VERSION 5.8 ;
BUSBITCHARS "[]" ;
DIVIDERCHAR "/" ;
UNITS
    DATABASE MICRONS 1000 ;
END UNITS

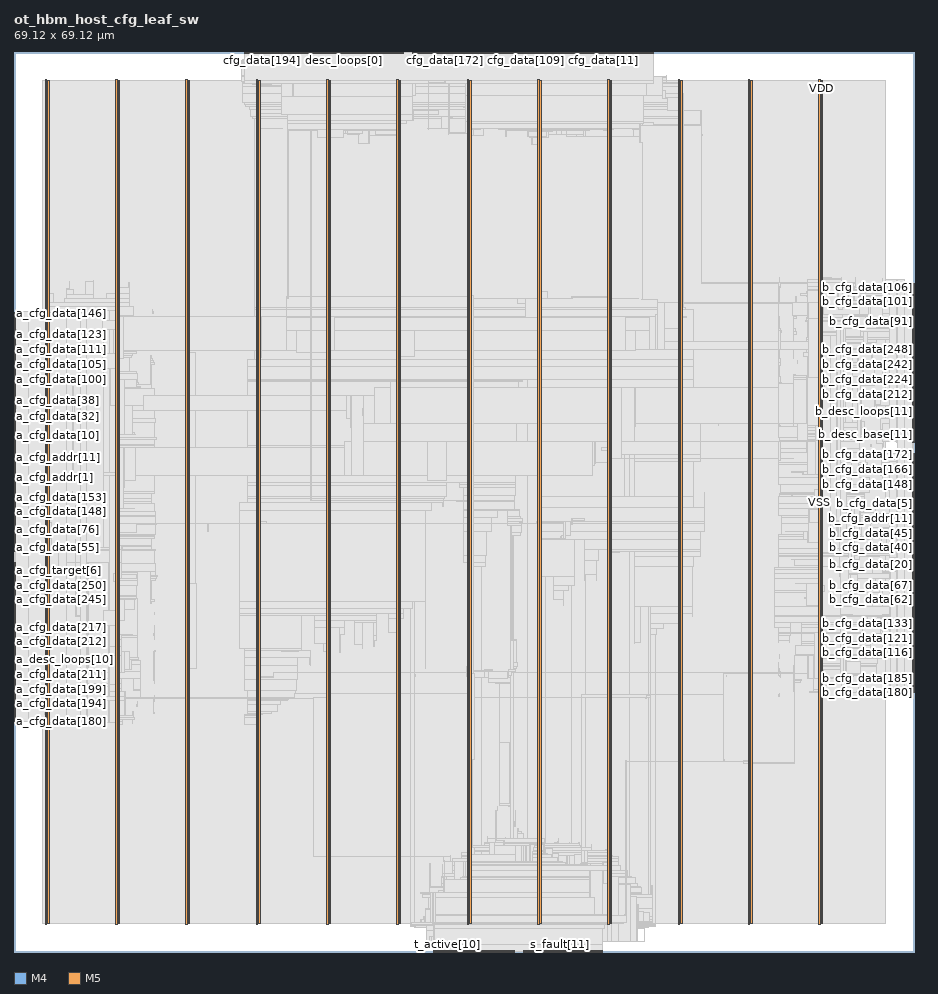
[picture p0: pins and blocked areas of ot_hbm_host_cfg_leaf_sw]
MACRO ot_hbm_host_cfg_leaf_sw
  FOREIGN ot_hbm_host_cfg_leaf_sw 0 0 ;
  CLASS BLOCK ;
  SIZE 69.12 BY 69.12 ;
  PIN a_cfg_addr[0]
    DIRECTION OUTPUT ;
    USE SIGNAL ;
    PORT
      LAYER M4 ;
        RECT  0 36.912 0.084 36.936 ;
    END
  END a_cfg_addr[0]
  PIN a_cfg_addr[10]
    DIRECTION OUTPUT ;
    USE SIGNAL ;
    PORT
      LAYER M4 ;
        RECT  0 37.872 0.084 37.896 ;
    END
  END a_cfg_addr[10]
  PIN a_cfg_addr[11]
    DIRECTION OUTPUT ;
    USE SIGNAL ;
    PORT
      LAYER M4 ;
        RECT  0 37.968 0.084 37.992 ;
    END
  END a_cfg_addr[11]
  PIN a_cfg_addr[1]
    DIRECTION OUTPUT ;
    USE SIGNAL ;
    PORT
      LAYER M4 ;
        RECT  0 37.008 0.084 37.032 ;
    END
  END a_cfg_addr[1]
  PIN a_cfg_addr[2]
    DIRECTION OUTPUT ;
    USE SIGNAL ;
    PORT
      LAYER M4 ;
        RECT  0 37.104 0.084 37.128 ;
    END
  END a_cfg_addr[2]
  PIN a_cfg_addr[3]
    DIRECTION OUTPUT ;
    USE SIGNAL ;
    PORT
      LAYER M4 ;
        RECT  0 37.2 0.084 37.224 ;
    END
  END a_cfg_addr[3]
  PIN a_cfg_addr[4]
    DIRECTION OUTPUT ;
    USE SIGNAL ;
    PORT
      LAYER M4 ;
        RECT  0 37.296 0.084 37.32 ;
    END
  END a_cfg_addr[4]
  PIN a_cfg_addr[5]
    DIRECTION OUTPUT ;
    USE SIGNAL ;
    PORT
      LAYER M4 ;
        RECT  0 37.392 0.084 37.416 ;
    END
  END a_cfg_addr[5]
  PIN a_cfg_addr[6]
    DIRECTION OUTPUT ;
    USE SIGNAL ;
    PORT
      LAYER M4 ;
        RECT  0 37.488 0.084 37.512 ;
    END
  END a_cfg_addr[6]
  PIN a_cfg_addr[7]
    DIRECTION OUTPUT ;
    USE SIGNAL ;
    PORT
      LAYER M4 ;
        RECT  0 37.584 0.084 37.608 ;
    END
  END a_cfg_addr[7]
  PIN a_cfg_addr[8]
    DIRECTION OUTPUT ;
    USE SIGNAL ;
    PORT
      LAYER M4 ;
        RECT  0 37.68 0.084 37.704 ;
    END
  END a_cfg_addr[8]
  PIN a_cfg_addr[9]
    DIRECTION OUTPUT ;
    USE SIGNAL ;
    PORT
      LAYER M4 ;
        RECT  0 37.776 0.084 37.8 ;
    END
  END a_cfg_addr[9]
  PIN a_cfg_data[0]
    DIRECTION OUTPUT ;
    USE SIGNAL ;
    PORT
      LAYER M4 ;
        RECT  0 38.064 0.084 38.088 ;
    END
  END a_cfg_data[0]
  PIN a_cfg_data[100]
    DIRECTION OUTPUT ;
    USE SIGNAL ;
    PORT
      LAYER M4 ;
        RECT  0 44.592 0.084 44.616 ;
    END
  END a_cfg_data[100]
  PIN a_cfg_data[101]
    DIRECTION OUTPUT ;
    USE SIGNAL ;
    PORT
      LAYER M4 ;
        RECT  0 44.688 0.084 44.712 ;
    END
  END a_cfg_data[101]
  PIN a_cfg_data[102]
    DIRECTION OUTPUT ;
    USE SIGNAL ;
    PORT
      LAYER M4 ;
        RECT  0 44.784 0.084 44.808 ;
    END
  END a_cfg_data[102]
  PIN a_cfg_data[103]
    DIRECTION OUTPUT ;
    USE SIGNAL ;
    PORT
      LAYER M4 ;
        RECT  0 44.88 0.084 44.904 ;
    END
  END a_cfg_data[103]
  PIN a_cfg_data[104]
    DIRECTION OUTPUT ;
    USE SIGNAL ;
    PORT
      LAYER M4 ;
        RECT  0 44.976 0.084 45 ;
    END
  END a_cfg_data[104]
  PIN a_cfg_data[105]
    DIRECTION OUTPUT ;
    USE SIGNAL ;
    PORT
      LAYER M4 ;
        RECT  0 45.072 0.084 45.096 ;
    END
  END a_cfg_data[105]
  PIN a_cfg_data[106]
    DIRECTION OUTPUT ;
    USE SIGNAL ;
    PORT
      LAYER M4 ;
        RECT  0 45.168 0.084 45.192 ;
    END
  END a_cfg_data[106]
  PIN a_cfg_data[107]
    DIRECTION OUTPUT ;
    USE SIGNAL ;
    PORT
      LAYER M4 ;
        RECT  0 45.264 0.084 45.288 ;
    END
  END a_cfg_data[107]
  PIN a_cfg_data[108]
    DIRECTION OUTPUT ;
    USE SIGNAL ;
    PORT
      LAYER M4 ;
        RECT  0 45.36 0.084 45.384 ;
    END
  END a_cfg_data[108]
  PIN a_cfg_data[109]
    DIRECTION OUTPUT ;
    USE SIGNAL ;
    PORT
      LAYER M4 ;
        RECT  0 45.456 0.084 45.48 ;
    END
  END a_cfg_data[109]
  PIN a_cfg_data[10]
    DIRECTION OUTPUT ;
    USE SIGNAL ;
    PORT
      LAYER M4 ;
        RECT  0 39.024 0.084 39.048 ;
    END
  END a_cfg_data[10]
  PIN a_cfg_data[110]
    DIRECTION OUTPUT ;
    USE SIGNAL ;
    PORT
      LAYER M4 ;
        RECT  0 45.552 0.084 45.576 ;
    END
  END a_cfg_data[110]
  PIN a_cfg_data[111]
    DIRECTION OUTPUT ;
    USE SIGNAL ;
    PORT
      LAYER M4 ;
        RECT  0 45.648 0.084 45.672 ;
    END
  END a_cfg_data[111]
  PIN a_cfg_data[112]
    DIRECTION OUTPUT ;
    USE SIGNAL ;
    PORT
      LAYER M4 ;
        RECT  0 45.744 0.084 45.768 ;
    END
  END a_cfg_data[112]
  PIN a_cfg_data[113]
    DIRECTION OUTPUT ;
    USE SIGNAL ;
    PORT
      LAYER M4 ;
        RECT  0 45.84 0.084 45.864 ;
    END
  END a_cfg_data[113]
  PIN a_cfg_data[114]
    DIRECTION OUTPUT ;
    USE SIGNAL ;
    PORT
      LAYER M4 ;
        RECT  0 45.936 0.084 45.96 ;
    END
  END a_cfg_data[114]
  PIN a_cfg_data[115]
    DIRECTION OUTPUT ;
    USE SIGNAL ;
    PORT
      LAYER M4 ;
        RECT  0 46.032 0.084 46.056 ;
    END
  END a_cfg_data[115]
  PIN a_cfg_data[116]
    DIRECTION OUTPUT ;
    USE SIGNAL ;
    PORT
      LAYER M4 ;
        RECT  0 46.128 0.084 46.152 ;
    END
  END a_cfg_data[116]
  PIN a_cfg_data[117]
    DIRECTION OUTPUT ;
    USE SIGNAL ;
    PORT
      LAYER M4 ;
        RECT  0 46.224 0.084 46.248 ;
    END
  END a_cfg_data[117]
  PIN a_cfg_data[118]
    DIRECTION OUTPUT ;
    USE SIGNAL ;
    PORT
      LAYER M4 ;
        RECT  0 46.32 0.084 46.344 ;
    END
  END a_cfg_data[118]
  PIN a_cfg_data[119]
    DIRECTION OUTPUT ;
    USE SIGNAL ;
    PORT
      LAYER M4 ;
        RECT  0 46.416 0.084 46.44 ;
    END
  END a_cfg_data[119]
  PIN a_cfg_data[11]
    DIRECTION OUTPUT ;
    USE SIGNAL ;
    PORT
      LAYER M4 ;
        RECT  0 39.12 0.084 39.144 ;
    END
  END a_cfg_data[11]
  PIN a_cfg_data[120]
    DIRECTION OUTPUT ;
    USE SIGNAL ;
    PORT
      LAYER M4 ;
        RECT  0 46.512 0.084 46.536 ;
    END
  END a_cfg_data[120]
  PIN a_cfg_data[121]
    DIRECTION OUTPUT ;
    USE SIGNAL ;
    PORT
      LAYER M4 ;
        RECT  0 46.608 0.084 46.632 ;
    END
  END a_cfg_data[121]
  PIN a_cfg_data[122]
    DIRECTION OUTPUT ;
    USE SIGNAL ;
    PORT
      LAYER M4 ;
        RECT  0 46.704 0.084 46.728 ;
    END
  END a_cfg_data[122]
  PIN a_cfg_data[123]
    DIRECTION OUTPUT ;
    USE SIGNAL ;
    PORT
      LAYER M4 ;
        RECT  0 46.8 0.084 46.824 ;
    END
  END a_cfg_data[123]
  PIN a_cfg_data[124]
    DIRECTION OUTPUT ;
    USE SIGNAL ;
    PORT
      LAYER M4 ;
        RECT  0 46.896 0.084 46.92 ;
    END
  END a_cfg_data[124]
  PIN a_cfg_data[125]
    DIRECTION OUTPUT ;
    USE SIGNAL ;
    PORT
      LAYER M4 ;
        RECT  0 46.992 0.084 47.016 ;
    END
  END a_cfg_data[125]
  PIN a_cfg_data[126]
    DIRECTION OUTPUT ;
    USE SIGNAL ;
    PORT
      LAYER M4 ;
        RECT  0 47.088 0.084 47.112 ;
    END
  END a_cfg_data[126]
  PIN a_cfg_data[127]
    DIRECTION OUTPUT ;
    USE SIGNAL ;
    PORT
      LAYER M4 ;
        RECT  0 47.184 0.084 47.208 ;
    END
  END a_cfg_data[127]
  PIN a_cfg_data[128]
    DIRECTION OUTPUT ;
    USE SIGNAL ;
    PORT
      LAYER M4 ;
        RECT  0 47.28 0.084 47.304 ;
    END
  END a_cfg_data[128]
  PIN a_cfg_data[129]
    DIRECTION OUTPUT ;
    USE SIGNAL ;
    PORT
      LAYER M4 ;
        RECT  0 47.376 0.084 47.4 ;
    END
  END a_cfg_data[129]
  PIN a_cfg_data[12]
    DIRECTION OUTPUT ;
    USE SIGNAL ;
    PORT
      LAYER M4 ;
        RECT  0 39.216 0.084 39.24 ;
    END
  END a_cfg_data[12]
  PIN a_cfg_data[130]
    DIRECTION OUTPUT ;
    USE SIGNAL ;
    PORT
      LAYER M4 ;
        RECT  0 47.472 0.084 47.496 ;
    END
  END a_cfg_data[130]
  PIN a_cfg_data[131]
    DIRECTION OUTPUT ;
    USE SIGNAL ;
    PORT
      LAYER M4 ;
        RECT  0 47.568 0.084 47.592 ;
    END
  END a_cfg_data[131]
  PIN a_cfg_data[132]
    DIRECTION OUTPUT ;
    USE SIGNAL ;
    PORT
      LAYER M4 ;
        RECT  0 47.664 0.084 47.688 ;
    END
  END a_cfg_data[132]
  PIN a_cfg_data[133]
    DIRECTION OUTPUT ;
    USE SIGNAL ;
    PORT
      LAYER M4 ;
        RECT  0 47.76 0.084 47.784 ;
    END
  END a_cfg_data[133]
  PIN a_cfg_data[134]
    DIRECTION OUTPUT ;
    USE SIGNAL ;
    PORT
      LAYER M4 ;
        RECT  0 47.856 0.084 47.88 ;
    END
  END a_cfg_data[134]
  PIN a_cfg_data[135]
    DIRECTION OUTPUT ;
    USE SIGNAL ;
    PORT
      LAYER M4 ;
        RECT  0 47.952 0.084 47.976 ;
    END
  END a_cfg_data[135]
  PIN a_cfg_data[136]
    DIRECTION OUTPUT ;
    USE SIGNAL ;
    PORT
      LAYER M4 ;
        RECT  0 48.048 0.084 48.072 ;
    END
  END a_cfg_data[136]
  PIN a_cfg_data[137]
    DIRECTION OUTPUT ;
    USE SIGNAL ;
    PORT
      LAYER M4 ;
        RECT  0 48.144 0.084 48.168 ;
    END
  END a_cfg_data[137]
  PIN a_cfg_data[138]
    DIRECTION OUTPUT ;
    USE SIGNAL ;
    PORT
      LAYER M4 ;
        RECT  0 48.24 0.084 48.264 ;
    END
  END a_cfg_data[138]
  PIN a_cfg_data[139]
    DIRECTION OUTPUT ;
    USE SIGNAL ;
    PORT
      LAYER M4 ;
        RECT  0 48.336 0.084 48.36 ;
    END
  END a_cfg_data[139]
  PIN a_cfg_data[13]
    DIRECTION OUTPUT ;
    USE SIGNAL ;
    PORT
      LAYER M4 ;
        RECT  0 39.312 0.084 39.336 ;
    END
  END a_cfg_data[13]
  PIN a_cfg_data[140]
    DIRECTION OUTPUT ;
    USE SIGNAL ;
    PORT
      LAYER M4 ;
        RECT  0 48.432 0.084 48.456 ;
    END
  END a_cfg_data[140]
  PIN a_cfg_data[141]
    DIRECTION OUTPUT ;
    USE SIGNAL ;
    PORT
      LAYER M4 ;
        RECT  0 48.528 0.084 48.552 ;
    END
  END a_cfg_data[141]
  PIN a_cfg_data[142]
    DIRECTION OUTPUT ;
    USE SIGNAL ;
    PORT
      LAYER M4 ;
        RECT  0 48.624 0.084 48.648 ;
    END
  END a_cfg_data[142]
  PIN a_cfg_data[143]
    DIRECTION OUTPUT ;
    USE SIGNAL ;
    PORT
      LAYER M4 ;
        RECT  0 48.72 0.084 48.744 ;
    END
  END a_cfg_data[143]
  PIN a_cfg_data[144]
    DIRECTION OUTPUT ;
    USE SIGNAL ;
    PORT
      LAYER M4 ;
        RECT  0 48.816 0.084 48.84 ;
    END
  END a_cfg_data[144]
  PIN a_cfg_data[145]
    DIRECTION OUTPUT ;
    USE SIGNAL ;
    PORT
      LAYER M4 ;
        RECT  0 48.912 0.084 48.936 ;
    END
  END a_cfg_data[145]
  PIN a_cfg_data[146]
    DIRECTION OUTPUT ;
    USE SIGNAL ;
    PORT
      LAYER M4 ;
        RECT  0 49.008 0.084 49.032 ;
    END
  END a_cfg_data[146]
  PIN a_cfg_data[147]
    DIRECTION OUTPUT ;
    USE SIGNAL ;
    PORT
      LAYER M4 ;
        RECT  0 49.104 0.084 49.128 ;
    END
  END a_cfg_data[147]
  PIN a_cfg_data[148]
    DIRECTION OUTPUT ;
    USE SIGNAL ;
    PORT
      LAYER M4 ;
        RECT  0 33.84 0.084 33.864 ;
    END
  END a_cfg_data[148]
  PIN a_cfg_data[149]
    DIRECTION OUTPUT ;
    USE SIGNAL ;
    PORT
      LAYER M4 ;
        RECT  0 33.936 0.084 33.96 ;
    END
  END a_cfg_data[149]
  PIN a_cfg_data[14]
    DIRECTION OUTPUT ;
    USE SIGNAL ;
    PORT
      LAYER M4 ;
        RECT  0 39.408 0.084 39.432 ;
    END
  END a_cfg_data[14]
  PIN a_cfg_data[150]
    DIRECTION OUTPUT ;
    USE SIGNAL ;
    PORT
      LAYER M4 ;
        RECT  0 34.032 0.084 34.056 ;
    END
  END a_cfg_data[150]
  PIN a_cfg_data[151]
    DIRECTION OUTPUT ;
    USE SIGNAL ;
    PORT
      LAYER M4 ;
        RECT  0 34.128 0.084 34.152 ;
    END
  END a_cfg_data[151]
  PIN a_cfg_data[152]
    DIRECTION OUTPUT ;
    USE SIGNAL ;
    PORT
      LAYER M4 ;
        RECT  0 34.224 0.084 34.248 ;
    END
  END a_cfg_data[152]
  PIN a_cfg_data[153]
    DIRECTION OUTPUT ;
    USE SIGNAL ;
    PORT
      LAYER M4 ;
        RECT  0 34.32 0.084 34.344 ;
    END
  END a_cfg_data[153]
  PIN a_cfg_data[154]
    DIRECTION OUTPUT ;
    USE SIGNAL ;
    PORT
      LAYER M4 ;
        RECT  0 34.416 0.084 34.44 ;
    END
  END a_cfg_data[154]
  PIN a_cfg_data[155]
    DIRECTION OUTPUT ;
    USE SIGNAL ;
    PORT
      LAYER M4 ;
        RECT  0 34.512 0.084 34.536 ;
    END
  END a_cfg_data[155]
  PIN a_cfg_data[156]
    DIRECTION OUTPUT ;
    USE SIGNAL ;
    PORT
      LAYER M4 ;
        RECT  0 34.608 0.084 34.632 ;
    END
  END a_cfg_data[156]
  PIN a_cfg_data[157]
    DIRECTION OUTPUT ;
    USE SIGNAL ;
    PORT
      LAYER M4 ;
        RECT  0 34.704 0.084 34.728 ;
    END
  END a_cfg_data[157]
  PIN a_cfg_data[158]
    DIRECTION OUTPUT ;
    USE SIGNAL ;
    PORT
      LAYER M4 ;
        RECT  0 34.8 0.084 34.824 ;
    END
  END a_cfg_data[158]
  PIN a_cfg_data[159]
    DIRECTION OUTPUT ;
    USE SIGNAL ;
    PORT
      LAYER M4 ;
        RECT  0 34.896 0.084 34.92 ;
    END
  END a_cfg_data[159]
  PIN a_cfg_data[15]
    DIRECTION OUTPUT ;
    USE SIGNAL ;
    PORT
      LAYER M4 ;
        RECT  0 39.504 0.084 39.528 ;
    END
  END a_cfg_data[15]
  PIN a_cfg_data[160]
    DIRECTION OUTPUT ;
    USE SIGNAL ;
    PORT
      LAYER M4 ;
        RECT  0 34.992 0.084 35.016 ;
    END
  END a_cfg_data[160]
  PIN a_cfg_data[161]
    DIRECTION OUTPUT ;
    USE SIGNAL ;
    PORT
      LAYER M4 ;
        RECT  0 35.088 0.084 35.112 ;
    END
  END a_cfg_data[161]
  PIN a_cfg_data[162]
    DIRECTION OUTPUT ;
    USE SIGNAL ;
    PORT
      LAYER M4 ;
        RECT  0 35.184 0.084 35.208 ;
    END
  END a_cfg_data[162]
  PIN a_cfg_data[163]
    DIRECTION OUTPUT ;
    USE SIGNAL ;
    PORT
      LAYER M4 ;
        RECT  0 35.28 0.084 35.304 ;
    END
  END a_cfg_data[163]
  PIN a_cfg_data[164]
    DIRECTION OUTPUT ;
    USE SIGNAL ;
    PORT
      LAYER M4 ;
        RECT  0 35.376 0.084 35.4 ;
    END
  END a_cfg_data[164]
  PIN a_cfg_data[165]
    DIRECTION OUTPUT ;
    USE SIGNAL ;
    PORT
      LAYER M4 ;
        RECT  0 35.472 0.084 35.496 ;
    END
  END a_cfg_data[165]
  PIN a_cfg_data[166]
    DIRECTION OUTPUT ;
    USE SIGNAL ;
    PORT
      LAYER M4 ;
        RECT  0 35.568 0.084 35.592 ;
    END
  END a_cfg_data[166]
  PIN a_cfg_data[167]
    DIRECTION OUTPUT ;
    USE SIGNAL ;
    PORT
      LAYER M4 ;
        RECT  0 35.664 0.084 35.688 ;
    END
  END a_cfg_data[167]
  PIN a_cfg_data[168]
    DIRECTION OUTPUT ;
    USE SIGNAL ;
    PORT
      LAYER M4 ;
        RECT  0 35.76 0.084 35.784 ;
    END
  END a_cfg_data[168]
  PIN a_cfg_data[169]
    DIRECTION OUTPUT ;
    USE SIGNAL ;
    PORT
      LAYER M4 ;
        RECT  0 35.856 0.084 35.88 ;
    END
  END a_cfg_data[169]
  PIN a_cfg_data[16]
    DIRECTION OUTPUT ;
    USE SIGNAL ;
    PORT
      LAYER M4 ;
        RECT  0 39.6 0.084 39.624 ;
    END
  END a_cfg_data[16]
  PIN a_cfg_data[170]
    DIRECTION OUTPUT ;
    USE SIGNAL ;
    PORT
      LAYER M4 ;
        RECT  0 35.952 0.084 35.976 ;
    END
  END a_cfg_data[170]
  PIN a_cfg_data[171]
    DIRECTION OUTPUT ;
    USE SIGNAL ;
    PORT
      LAYER M4 ;
        RECT  0 36.048 0.084 36.072 ;
    END
  END a_cfg_data[171]
  PIN a_cfg_data[172]
    DIRECTION OUTPUT ;
    USE SIGNAL ;
    PORT
      LAYER M4 ;
        RECT  0 36.144 0.084 36.168 ;
    END
  END a_cfg_data[172]
  PIN a_cfg_data[173]
    DIRECTION OUTPUT ;
    USE SIGNAL ;
    PORT
      LAYER M4 ;
        RECT  0 36.24 0.084 36.264 ;
    END
  END a_cfg_data[173]
  PIN a_cfg_data[174]
    DIRECTION OUTPUT ;
    USE SIGNAL ;
    PORT
      LAYER M4 ;
        RECT  0 36.336 0.084 36.36 ;
    END
  END a_cfg_data[174]
  PIN a_cfg_data[175]
    DIRECTION OUTPUT ;
    USE SIGNAL ;
    PORT
      LAYER M4 ;
        RECT  0 36.432 0.084 36.456 ;
    END
  END a_cfg_data[175]
  PIN a_cfg_data[176]
    DIRECTION OUTPUT ;
    USE SIGNAL ;
    PORT
      LAYER M4 ;
        RECT  0 36.528 0.084 36.552 ;
    END
  END a_cfg_data[176]
  PIN a_cfg_data[177]
    DIRECTION OUTPUT ;
    USE SIGNAL ;
    PORT
      LAYER M4 ;
        RECT  0 36.624 0.084 36.648 ;
    END
  END a_cfg_data[177]
  PIN a_cfg_data[178]
    DIRECTION OUTPUT ;
    USE SIGNAL ;
    PORT
      LAYER M4 ;
        RECT  0 36.72 0.084 36.744 ;
    END
  END a_cfg_data[178]
  PIN a_cfg_data[179]
    DIRECTION OUTPUT ;
    USE SIGNAL ;
    PORT
      LAYER M4 ;
        RECT  0 36.816 0.084 36.84 ;
    END
  END a_cfg_data[179]
  PIN a_cfg_data[17]
    DIRECTION OUTPUT ;
    USE SIGNAL ;
    PORT
      LAYER M4 ;
        RECT  0 39.696 0.084 39.72 ;
    END
  END a_cfg_data[17]
  PIN a_cfg_data[180]
    DIRECTION OUTPUT ;
    USE SIGNAL ;
    PORT
      LAYER M4 ;
        RECT  0 17.712 0.084 17.736 ;
    END
  END a_cfg_data[180]
  PIN a_cfg_data[181]
    DIRECTION OUTPUT ;
    USE SIGNAL ;
    PORT
      LAYER M4 ;
        RECT  0 17.808 0.084 17.832 ;
    END
  END a_cfg_data[181]
  PIN a_cfg_data[182]
    DIRECTION OUTPUT ;
    USE SIGNAL ;
    PORT
      LAYER M4 ;
        RECT  0 17.904 0.084 17.928 ;
    END
  END a_cfg_data[182]
  PIN a_cfg_data[183]
    DIRECTION OUTPUT ;
    USE SIGNAL ;
    PORT
      LAYER M4 ;
        RECT  0 18 0.084 18.024 ;
    END
  END a_cfg_data[183]
  PIN a_cfg_data[184]
    DIRECTION OUTPUT ;
    USE SIGNAL ;
    PORT
      LAYER M4 ;
        RECT  0 18.096 0.084 18.12 ;
    END
  END a_cfg_data[184]
  PIN a_cfg_data[185]
    DIRECTION OUTPUT ;
    USE SIGNAL ;
    PORT
      LAYER M4 ;
        RECT  0 18.192 0.084 18.216 ;
    END
  END a_cfg_data[185]
  PIN a_cfg_data[186]
    DIRECTION OUTPUT ;
    USE SIGNAL ;
    PORT
      LAYER M4 ;
        RECT  0 18.288 0.084 18.312 ;
    END
  END a_cfg_data[186]
  PIN a_cfg_data[187]
    DIRECTION OUTPUT ;
    USE SIGNAL ;
    PORT
      LAYER M4 ;
        RECT  0 18.384 0.084 18.408 ;
    END
  END a_cfg_data[187]
  PIN a_cfg_data[188]
    DIRECTION OUTPUT ;
    USE SIGNAL ;
    PORT
      LAYER M4 ;
        RECT  0 18.48 0.084 18.504 ;
    END
  END a_cfg_data[188]
  PIN a_cfg_data[189]
    DIRECTION OUTPUT ;
    USE SIGNAL ;
    PORT
      LAYER M4 ;
        RECT  0 18.576 0.084 18.6 ;
    END
  END a_cfg_data[189]
  PIN a_cfg_data[18]
    DIRECTION OUTPUT ;
    USE SIGNAL ;
    PORT
      LAYER M4 ;
        RECT  0 39.792 0.084 39.816 ;
    END
  END a_cfg_data[18]
  PIN a_cfg_data[190]
    DIRECTION OUTPUT ;
    USE SIGNAL ;
    PORT
      LAYER M4 ;
        RECT  0 18.672 0.084 18.696 ;
    END
  END a_cfg_data[190]
  PIN a_cfg_data[191]
    DIRECTION OUTPUT ;
    USE SIGNAL ;
    PORT
      LAYER M4 ;
        RECT  0 18.768 0.084 18.792 ;
    END
  END a_cfg_data[191]
  PIN a_cfg_data[192]
    DIRECTION OUTPUT ;
    USE SIGNAL ;
    PORT
      LAYER M4 ;
        RECT  0 18.864 0.084 18.888 ;
    END
  END a_cfg_data[192]
  PIN a_cfg_data[193]
    DIRECTION OUTPUT ;
    USE SIGNAL ;
    PORT
      LAYER M4 ;
        RECT  0 18.96 0.084 18.984 ;
    END
  END a_cfg_data[193]
  PIN a_cfg_data[194]
    DIRECTION OUTPUT ;
    USE SIGNAL ;
    PORT
      LAYER M4 ;
        RECT  0 19.056 0.084 19.08 ;
    END
  END a_cfg_data[194]
  PIN a_cfg_data[195]
    DIRECTION OUTPUT ;
    USE SIGNAL ;
    PORT
      LAYER M4 ;
        RECT  0 19.152 0.084 19.176 ;
    END
  END a_cfg_data[195]
  PIN a_cfg_data[196]
    DIRECTION OUTPUT ;
    USE SIGNAL ;
    PORT
      LAYER M4 ;
        RECT  0 19.248 0.084 19.272 ;
    END
  END a_cfg_data[196]
  PIN a_cfg_data[197]
    DIRECTION OUTPUT ;
    USE SIGNAL ;
    PORT
      LAYER M4 ;
        RECT  0 19.344 0.084 19.368 ;
    END
  END a_cfg_data[197]
  PIN a_cfg_data[198]
    DIRECTION OUTPUT ;
    USE SIGNAL ;
    PORT
      LAYER M4 ;
        RECT  0 19.44 0.084 19.464 ;
    END
  END a_cfg_data[198]
  PIN a_cfg_data[199]
    DIRECTION OUTPUT ;
    USE SIGNAL ;
    PORT
      LAYER M4 ;
        RECT  0 19.536 0.084 19.56 ;
    END
  END a_cfg_data[199]
  PIN a_cfg_data[19]
    DIRECTION OUTPUT ;
    USE SIGNAL ;
    PORT
      LAYER M4 ;
        RECT  0 39.888 0.084 39.912 ;
    END
  END a_cfg_data[19]
  PIN a_cfg_data[1]
    DIRECTION OUTPUT ;
    USE SIGNAL ;
    PORT
      LAYER M4 ;
        RECT  0 38.16 0.084 38.184 ;
    END
  END a_cfg_data[1]
  PIN a_cfg_data[200]
    DIRECTION OUTPUT ;
    USE SIGNAL ;
    PORT
      LAYER M4 ;
        RECT  0 19.632 0.084 19.656 ;
    END
  END a_cfg_data[200]
  PIN a_cfg_data[201]
    DIRECTION OUTPUT ;
    USE SIGNAL ;
    PORT
      LAYER M4 ;
        RECT  0 19.728 0.084 19.752 ;
    END
  END a_cfg_data[201]
  PIN a_cfg_data[202]
    DIRECTION OUTPUT ;
    USE SIGNAL ;
    PORT
      LAYER M4 ;
        RECT  0 19.824 0.084 19.848 ;
    END
  END a_cfg_data[202]
  PIN a_cfg_data[203]
    DIRECTION OUTPUT ;
    USE SIGNAL ;
    PORT
      LAYER M4 ;
        RECT  0 19.92 0.084 19.944 ;
    END
  END a_cfg_data[203]
  PIN a_cfg_data[204]
    DIRECTION OUTPUT ;
    USE SIGNAL ;
    PORT
      LAYER M4 ;
        RECT  0 20.016 0.084 20.04 ;
    END
  END a_cfg_data[204]
  PIN a_cfg_data[205]
    DIRECTION OUTPUT ;
    USE SIGNAL ;
    PORT
      LAYER M4 ;
        RECT  0 20.112 0.084 20.136 ;
    END
  END a_cfg_data[205]
  PIN a_cfg_data[206]
    DIRECTION OUTPUT ;
    USE SIGNAL ;
    PORT
      LAYER M4 ;
        RECT  0 20.208 0.084 20.232 ;
    END
  END a_cfg_data[206]
  PIN a_cfg_data[207]
    DIRECTION OUTPUT ;
    USE SIGNAL ;
    PORT
      LAYER M4 ;
        RECT  0 20.304 0.084 20.328 ;
    END
  END a_cfg_data[207]
  PIN a_cfg_data[208]
    DIRECTION OUTPUT ;
    USE SIGNAL ;
    PORT
      LAYER M4 ;
        RECT  0 20.4 0.084 20.424 ;
    END
  END a_cfg_data[208]
  PIN a_cfg_data[209]
    DIRECTION OUTPUT ;
    USE SIGNAL ;
    PORT
      LAYER M4 ;
        RECT  0 20.496 0.084 20.52 ;
    END
  END a_cfg_data[209]
  PIN a_cfg_data[20]
    DIRECTION OUTPUT ;
    USE SIGNAL ;
    PORT
      LAYER M4 ;
        RECT  0 39.984 0.084 40.008 ;
    END
  END a_cfg_data[20]
  PIN a_cfg_data[210]
    DIRECTION OUTPUT ;
    USE SIGNAL ;
    PORT
      LAYER M4 ;
        RECT  0 20.592 0.084 20.616 ;
    END
  END a_cfg_data[210]
  PIN a_cfg_data[211]
    DIRECTION OUTPUT ;
    USE SIGNAL ;
    PORT
      LAYER M4 ;
        RECT  0 20.688 0.084 20.712 ;
    END
  END a_cfg_data[211]
  PIN a_cfg_data[212]
    DIRECTION OUTPUT ;
    USE SIGNAL ;
    PORT
      LAYER M4 ;
        RECT  0 23.856 0.084 23.88 ;
    END
  END a_cfg_data[212]
  PIN a_cfg_data[213]
    DIRECTION OUTPUT ;
    USE SIGNAL ;
    PORT
      LAYER M4 ;
        RECT  0 23.952 0.084 23.976 ;
    END
  END a_cfg_data[213]
  PIN a_cfg_data[214]
    DIRECTION OUTPUT ;
    USE SIGNAL ;
    PORT
      LAYER M4 ;
        RECT  0 24.048 0.084 24.072 ;
    END
  END a_cfg_data[214]
  PIN a_cfg_data[215]
    DIRECTION OUTPUT ;
    USE SIGNAL ;
    PORT
      LAYER M4 ;
        RECT  0 24.144 0.084 24.168 ;
    END
  END a_cfg_data[215]
  PIN a_cfg_data[216]
    DIRECTION OUTPUT ;
    USE SIGNAL ;
    PORT
      LAYER M4 ;
        RECT  0 24.24 0.084 24.264 ;
    END
  END a_cfg_data[216]
  PIN a_cfg_data[217]
    DIRECTION OUTPUT ;
    USE SIGNAL ;
    PORT
      LAYER M4 ;
        RECT  0 24.336 0.084 24.36 ;
    END
  END a_cfg_data[217]
  PIN a_cfg_data[218]
    DIRECTION OUTPUT ;
    USE SIGNAL ;
    PORT
      LAYER M4 ;
        RECT  0 24.432 0.084 24.456 ;
    END
  END a_cfg_data[218]
  PIN a_cfg_data[219]
    DIRECTION OUTPUT ;
    USE SIGNAL ;
    PORT
      LAYER M4 ;
        RECT  0 24.528 0.084 24.552 ;
    END
  END a_cfg_data[219]
  PIN a_cfg_data[21]
    DIRECTION OUTPUT ;
    USE SIGNAL ;
    PORT
      LAYER M4 ;
        RECT  0 40.08 0.084 40.104 ;
    END
  END a_cfg_data[21]
  PIN a_cfg_data[220]
    DIRECTION OUTPUT ;
    USE SIGNAL ;
    PORT
      LAYER M4 ;
        RECT  0 24.624 0.084 24.648 ;
    END
  END a_cfg_data[220]
  PIN a_cfg_data[221]
    DIRECTION OUTPUT ;
    USE SIGNAL ;
    PORT
      LAYER M4 ;
        RECT  0 24.72 0.084 24.744 ;
    END
  END a_cfg_data[221]
  PIN a_cfg_data[222]
    DIRECTION OUTPUT ;
    USE SIGNAL ;
    PORT
      LAYER M4 ;
        RECT  0 24.816 0.084 24.84 ;
    END
  END a_cfg_data[222]
  PIN a_cfg_data[223]
    DIRECTION OUTPUT ;
    USE SIGNAL ;
    PORT
      LAYER M4 ;
        RECT  0 24.912 0.084 24.936 ;
    END
  END a_cfg_data[223]
  PIN a_cfg_data[224]
    DIRECTION OUTPUT ;
    USE SIGNAL ;
    PORT
      LAYER M4 ;
        RECT  0 25.008 0.084 25.032 ;
    END
  END a_cfg_data[224]
  PIN a_cfg_data[225]
    DIRECTION OUTPUT ;
    USE SIGNAL ;
    PORT
      LAYER M4 ;
        RECT  0 25.104 0.084 25.128 ;
    END
  END a_cfg_data[225]
  PIN a_cfg_data[226]
    DIRECTION OUTPUT ;
    USE SIGNAL ;
    PORT
      LAYER M4 ;
        RECT  0 25.2 0.084 25.224 ;
    END
  END a_cfg_data[226]
  PIN a_cfg_data[227]
    DIRECTION OUTPUT ;
    USE SIGNAL ;
    PORT
      LAYER M4 ;
        RECT  0 25.296 0.084 25.32 ;
    END
  END a_cfg_data[227]
  PIN a_cfg_data[228]
    DIRECTION OUTPUT ;
    USE SIGNAL ;
    PORT
      LAYER M4 ;
        RECT  0 25.392 0.084 25.416 ;
    END
  END a_cfg_data[228]
  PIN a_cfg_data[229]
    DIRECTION OUTPUT ;
    USE SIGNAL ;
    PORT
      LAYER M4 ;
        RECT  0 25.488 0.084 25.512 ;
    END
  END a_cfg_data[229]
  PIN a_cfg_data[22]
    DIRECTION OUTPUT ;
    USE SIGNAL ;
    PORT
      LAYER M4 ;
        RECT  0 40.176 0.084 40.2 ;
    END
  END a_cfg_data[22]
  PIN a_cfg_data[230]
    DIRECTION OUTPUT ;
    USE SIGNAL ;
    PORT
      LAYER M4 ;
        RECT  0 25.584 0.084 25.608 ;
    END
  END a_cfg_data[230]
  PIN a_cfg_data[231]
    DIRECTION OUTPUT ;
    USE SIGNAL ;
    PORT
      LAYER M4 ;
        RECT  0 25.68 0.084 25.704 ;
    END
  END a_cfg_data[231]
  PIN a_cfg_data[232]
    DIRECTION OUTPUT ;
    USE SIGNAL ;
    PORT
      LAYER M4 ;
        RECT  0 25.776 0.084 25.8 ;
    END
  END a_cfg_data[232]
  PIN a_cfg_data[233]
    DIRECTION OUTPUT ;
    USE SIGNAL ;
    PORT
      LAYER M4 ;
        RECT  0 25.872 0.084 25.896 ;
    END
  END a_cfg_data[233]
  PIN a_cfg_data[234]
    DIRECTION OUTPUT ;
    USE SIGNAL ;
    PORT
      LAYER M4 ;
        RECT  0 25.968 0.084 25.992 ;
    END
  END a_cfg_data[234]
  PIN a_cfg_data[235]
    DIRECTION OUTPUT ;
    USE SIGNAL ;
    PORT
      LAYER M4 ;
        RECT  0 26.064 0.084 26.088 ;
    END
  END a_cfg_data[235]
  PIN a_cfg_data[236]
    DIRECTION OUTPUT ;
    USE SIGNAL ;
    PORT
      LAYER M4 ;
        RECT  0 26.16 0.084 26.184 ;
    END
  END a_cfg_data[236]
  PIN a_cfg_data[237]
    DIRECTION OUTPUT ;
    USE SIGNAL ;
    PORT
      LAYER M4 ;
        RECT  0 26.256 0.084 26.28 ;
    END
  END a_cfg_data[237]
  PIN a_cfg_data[238]
    DIRECTION OUTPUT ;
    USE SIGNAL ;
    PORT
      LAYER M4 ;
        RECT  0 26.352 0.084 26.376 ;
    END
  END a_cfg_data[238]
  PIN a_cfg_data[239]
    DIRECTION OUTPUT ;
    USE SIGNAL ;
    PORT
      LAYER M4 ;
        RECT  0 26.448 0.084 26.472 ;
    END
  END a_cfg_data[239]
  PIN a_cfg_data[23]
    DIRECTION OUTPUT ;
    USE SIGNAL ;
    PORT
      LAYER M4 ;
        RECT  0 40.272 0.084 40.296 ;
    END
  END a_cfg_data[23]
  PIN a_cfg_data[240]
    DIRECTION OUTPUT ;
    USE SIGNAL ;
    PORT
      LAYER M4 ;
        RECT  0 26.544 0.084 26.568 ;
    END
  END a_cfg_data[240]
  PIN a_cfg_data[241]
    DIRECTION OUTPUT ;
    USE SIGNAL ;
    PORT
      LAYER M4 ;
        RECT  0 26.64 0.084 26.664 ;
    END
  END a_cfg_data[241]
  PIN a_cfg_data[242]
    DIRECTION OUTPUT ;
    USE SIGNAL ;
    PORT
      LAYER M4 ;
        RECT  0 26.736 0.084 26.76 ;
    END
  END a_cfg_data[242]
  PIN a_cfg_data[243]
    DIRECTION OUTPUT ;
    USE SIGNAL ;
    PORT
      LAYER M4 ;
        RECT  0 26.832 0.084 26.856 ;
    END
  END a_cfg_data[243]
  PIN a_cfg_data[244]
    DIRECTION OUTPUT ;
    USE SIGNAL ;
    PORT
      LAYER M4 ;
        RECT  0 26.928 0.084 26.952 ;
    END
  END a_cfg_data[244]
  PIN a_cfg_data[245]
    DIRECTION OUTPUT ;
    USE SIGNAL ;
    PORT
      LAYER M4 ;
        RECT  0 27.024 0.084 27.048 ;
    END
  END a_cfg_data[245]
  PIN a_cfg_data[246]
    DIRECTION OUTPUT ;
    USE SIGNAL ;
    PORT
      LAYER M4 ;
        RECT  0 27.12 0.084 27.144 ;
    END
  END a_cfg_data[246]
  PIN a_cfg_data[247]
    DIRECTION OUTPUT ;
    USE SIGNAL ;
    PORT
      LAYER M4 ;
        RECT  0 27.216 0.084 27.24 ;
    END
  END a_cfg_data[247]
  PIN a_cfg_data[248]
    DIRECTION OUTPUT ;
    USE SIGNAL ;
    PORT
      LAYER M4 ;
        RECT  0 27.312 0.084 27.336 ;
    END
  END a_cfg_data[248]
  PIN a_cfg_data[249]
    DIRECTION OUTPUT ;
    USE SIGNAL ;
    PORT
      LAYER M4 ;
        RECT  0 27.408 0.084 27.432 ;
    END
  END a_cfg_data[249]
  PIN a_cfg_data[24]
    DIRECTION OUTPUT ;
    USE SIGNAL ;
    PORT
      LAYER M4 ;
        RECT  0 40.368 0.084 40.392 ;
    END
  END a_cfg_data[24]
  PIN a_cfg_data[250]
    DIRECTION OUTPUT ;
    USE SIGNAL ;
    PORT
      LAYER M4 ;
        RECT  0 27.504 0.084 27.528 ;
    END
  END a_cfg_data[250]
  PIN a_cfg_data[251]
    DIRECTION OUTPUT ;
    USE SIGNAL ;
    PORT
      LAYER M4 ;
        RECT  0 27.6 0.084 27.624 ;
    END
  END a_cfg_data[251]
  PIN a_cfg_data[252]
    DIRECTION OUTPUT ;
    USE SIGNAL ;
    PORT
      LAYER M4 ;
        RECT  0 27.696 0.084 27.72 ;
    END
  END a_cfg_data[252]
  PIN a_cfg_data[253]
    DIRECTION OUTPUT ;
    USE SIGNAL ;
    PORT
      LAYER M4 ;
        RECT  0 27.792 0.084 27.816 ;
    END
  END a_cfg_data[253]
  PIN a_cfg_data[254]
    DIRECTION OUTPUT ;
    USE SIGNAL ;
    PORT
      LAYER M4 ;
        RECT  0 27.888 0.084 27.912 ;
    END
  END a_cfg_data[254]
  PIN a_cfg_data[255]
    DIRECTION OUTPUT ;
    USE SIGNAL ;
    PORT
      LAYER M4 ;
        RECT  0 27.984 0.084 28.008 ;
    END
  END a_cfg_data[255]
  PIN a_cfg_data[25]
    DIRECTION OUTPUT ;
    USE SIGNAL ;
    PORT
      LAYER M4 ;
        RECT  0 40.464 0.084 40.488 ;
    END
  END a_cfg_data[25]
  PIN a_cfg_data[26]
    DIRECTION OUTPUT ;
    USE SIGNAL ;
    PORT
      LAYER M4 ;
        RECT  0 40.56 0.084 40.584 ;
    END
  END a_cfg_data[26]
  PIN a_cfg_data[27]
    DIRECTION OUTPUT ;
    USE SIGNAL ;
    PORT
      LAYER M4 ;
        RECT  0 40.656 0.084 40.68 ;
    END
  END a_cfg_data[27]
  PIN a_cfg_data[28]
    DIRECTION OUTPUT ;
    USE SIGNAL ;
    PORT
      LAYER M4 ;
        RECT  0 40.752 0.084 40.776 ;
    END
  END a_cfg_data[28]
  PIN a_cfg_data[29]
    DIRECTION OUTPUT ;
    USE SIGNAL ;
    PORT
      LAYER M4 ;
        RECT  0 40.848 0.084 40.872 ;
    END
  END a_cfg_data[29]
  PIN a_cfg_data[2]
    DIRECTION OUTPUT ;
    USE SIGNAL ;
    PORT
      LAYER M4 ;
        RECT  0 38.256 0.084 38.28 ;
    END
  END a_cfg_data[2]
  PIN a_cfg_data[30]
    DIRECTION OUTPUT ;
    USE SIGNAL ;
    PORT
      LAYER M4 ;
        RECT  0 40.944 0.084 40.968 ;
    END
  END a_cfg_data[30]
  PIN a_cfg_data[31]
    DIRECTION OUTPUT ;
    USE SIGNAL ;
    PORT
      LAYER M4 ;
        RECT  0 41.04 0.084 41.064 ;
    END
  END a_cfg_data[31]
  PIN a_cfg_data[32]
    DIRECTION OUTPUT ;
    USE SIGNAL ;
    PORT
      LAYER M4 ;
        RECT  0 41.136 0.084 41.16 ;
    END
  END a_cfg_data[32]
  PIN a_cfg_data[33]
    DIRECTION OUTPUT ;
    USE SIGNAL ;
    PORT
      LAYER M4 ;
        RECT  0 41.232 0.084 41.256 ;
    END
  END a_cfg_data[33]
  PIN a_cfg_data[34]
    DIRECTION OUTPUT ;
    USE SIGNAL ;
    PORT
      LAYER M4 ;
        RECT  0 41.328 0.084 41.352 ;
    END
  END a_cfg_data[34]
  PIN a_cfg_data[35]
    DIRECTION OUTPUT ;
    USE SIGNAL ;
    PORT
      LAYER M4 ;
        RECT  0 41.424 0.084 41.448 ;
    END
  END a_cfg_data[35]
  PIN a_cfg_data[36]
    DIRECTION OUTPUT ;
    USE SIGNAL ;
    PORT
      LAYER M4 ;
        RECT  0 41.52 0.084 41.544 ;
    END
  END a_cfg_data[36]
  PIN a_cfg_data[37]
    DIRECTION OUTPUT ;
    USE SIGNAL ;
    PORT
      LAYER M4 ;
        RECT  0 41.616 0.084 41.64 ;
    END
  END a_cfg_data[37]
  PIN a_cfg_data[38]
    DIRECTION OUTPUT ;
    USE SIGNAL ;
    PORT
      LAYER M4 ;
        RECT  0 41.712 0.084 41.736 ;
    END
  END a_cfg_data[38]
  PIN a_cfg_data[39]
    DIRECTION OUTPUT ;
    USE SIGNAL ;
    PORT
      LAYER M4 ;
        RECT  0 41.808 0.084 41.832 ;
    END
  END a_cfg_data[39]
  PIN a_cfg_data[3]
    DIRECTION OUTPUT ;
    USE SIGNAL ;
    PORT
      LAYER M4 ;
        RECT  0 38.352 0.084 38.376 ;
    END
  END a_cfg_data[3]
  PIN a_cfg_data[40]
    DIRECTION OUTPUT ;
    USE SIGNAL ;
    PORT
      LAYER M4 ;
        RECT  0 41.904 0.084 41.928 ;
    END
  END a_cfg_data[40]
  PIN a_cfg_data[41]
    DIRECTION OUTPUT ;
    USE SIGNAL ;
    PORT
      LAYER M4 ;
        RECT  0 42 0.084 42.024 ;
    END
  END a_cfg_data[41]
  PIN a_cfg_data[42]
    DIRECTION OUTPUT ;
    USE SIGNAL ;
    PORT
      LAYER M4 ;
        RECT  0 42.096 0.084 42.12 ;
    END
  END a_cfg_data[42]
  PIN a_cfg_data[43]
    DIRECTION OUTPUT ;
    USE SIGNAL ;
    PORT
      LAYER M4 ;
        RECT  0 42.192 0.084 42.216 ;
    END
  END a_cfg_data[43]
  PIN a_cfg_data[44]
    DIRECTION OUTPUT ;
    USE SIGNAL ;
    PORT
      LAYER M4 ;
        RECT  0 42.288 0.084 42.312 ;
    END
  END a_cfg_data[44]
  PIN a_cfg_data[45]
    DIRECTION OUTPUT ;
    USE SIGNAL ;
    PORT
      LAYER M4 ;
        RECT  0 42.384 0.084 42.408 ;
    END
  END a_cfg_data[45]
  PIN a_cfg_data[46]
    DIRECTION OUTPUT ;
    USE SIGNAL ;
    PORT
      LAYER M4 ;
        RECT  0 42.48 0.084 42.504 ;
    END
  END a_cfg_data[46]
  PIN a_cfg_data[47]
    DIRECTION OUTPUT ;
    USE SIGNAL ;
    PORT
      LAYER M4 ;
        RECT  0 42.576 0.084 42.6 ;
    END
  END a_cfg_data[47]
  PIN a_cfg_data[48]
    DIRECTION OUTPUT ;
    USE SIGNAL ;
    PORT
      LAYER M4 ;
        RECT  0 42.672 0.084 42.696 ;
    END
  END a_cfg_data[48]
  PIN a_cfg_data[49]
    DIRECTION OUTPUT ;
    USE SIGNAL ;
    PORT
      LAYER M4 ;
        RECT  0 42.768 0.084 42.792 ;
    END
  END a_cfg_data[49]
  PIN a_cfg_data[4]
    DIRECTION OUTPUT ;
    USE SIGNAL ;
    PORT
      LAYER M4 ;
        RECT  0 38.448 0.084 38.472 ;
    END
  END a_cfg_data[4]
  PIN a_cfg_data[50]
    DIRECTION OUTPUT ;
    USE SIGNAL ;
    PORT
      LAYER M4 ;
        RECT  0 42.864 0.084 42.888 ;
    END
  END a_cfg_data[50]
  PIN a_cfg_data[51]
    DIRECTION OUTPUT ;
    USE SIGNAL ;
    PORT
      LAYER M4 ;
        RECT  0 42.96 0.084 42.984 ;
    END
  END a_cfg_data[51]
  PIN a_cfg_data[52]
    DIRECTION OUTPUT ;
    USE SIGNAL ;
    PORT
      LAYER M4 ;
        RECT  0 30.768 0.084 30.792 ;
    END
  END a_cfg_data[52]
  PIN a_cfg_data[53]
    DIRECTION OUTPUT ;
    USE SIGNAL ;
    PORT
      LAYER M4 ;
        RECT  0 30.864 0.084 30.888 ;
    END
  END a_cfg_data[53]
  PIN a_cfg_data[54]
    DIRECTION OUTPUT ;
    USE SIGNAL ;
    PORT
      LAYER M4 ;
        RECT  0 30.96 0.084 30.984 ;
    END
  END a_cfg_data[54]
  PIN a_cfg_data[55]
    DIRECTION OUTPUT ;
    USE SIGNAL ;
    PORT
      LAYER M4 ;
        RECT  0 31.056 0.084 31.08 ;
    END
  END a_cfg_data[55]
  PIN a_cfg_data[56]
    DIRECTION OUTPUT ;
    USE SIGNAL ;
    PORT
      LAYER M4 ;
        RECT  0 31.152 0.084 31.176 ;
    END
  END a_cfg_data[56]
  PIN a_cfg_data[57]
    DIRECTION OUTPUT ;
    USE SIGNAL ;
    PORT
      LAYER M4 ;
        RECT  0 31.248 0.084 31.272 ;
    END
  END a_cfg_data[57]
  PIN a_cfg_data[58]
    DIRECTION OUTPUT ;
    USE SIGNAL ;
    PORT
      LAYER M4 ;
        RECT  0 31.344 0.084 31.368 ;
    END
  END a_cfg_data[58]
  PIN a_cfg_data[59]
    DIRECTION OUTPUT ;
    USE SIGNAL ;
    PORT
      LAYER M4 ;
        RECT  0 31.44 0.084 31.464 ;
    END
  END a_cfg_data[59]
  PIN a_cfg_data[5]
    DIRECTION OUTPUT ;
    USE SIGNAL ;
    PORT
      LAYER M4 ;
        RECT  0 38.544 0.084 38.568 ;
    END
  END a_cfg_data[5]
  PIN a_cfg_data[60]
    DIRECTION OUTPUT ;
    USE SIGNAL ;
    PORT
      LAYER M4 ;
        RECT  0 31.536 0.084 31.56 ;
    END
  END a_cfg_data[60]
  PIN a_cfg_data[61]
    DIRECTION OUTPUT ;
    USE SIGNAL ;
    PORT
      LAYER M4 ;
        RECT  0 31.632 0.084 31.656 ;
    END
  END a_cfg_data[61]
  PIN a_cfg_data[62]
    DIRECTION OUTPUT ;
    USE SIGNAL ;
    PORT
      LAYER M4 ;
        RECT  0 31.728 0.084 31.752 ;
    END
  END a_cfg_data[62]
  PIN a_cfg_data[63]
    DIRECTION OUTPUT ;
    USE SIGNAL ;
    PORT
      LAYER M4 ;
        RECT  0 31.824 0.084 31.848 ;
    END
  END a_cfg_data[63]
  PIN a_cfg_data[64]
    DIRECTION OUTPUT ;
    USE SIGNAL ;
    PORT
      LAYER M4 ;
        RECT  0 31.92 0.084 31.944 ;
    END
  END a_cfg_data[64]
  PIN a_cfg_data[65]
    DIRECTION OUTPUT ;
    USE SIGNAL ;
    PORT
      LAYER M4 ;
        RECT  0 32.016 0.084 32.04 ;
    END
  END a_cfg_data[65]
  PIN a_cfg_data[66]
    DIRECTION OUTPUT ;
    USE SIGNAL ;
    PORT
      LAYER M4 ;
        RECT  0 32.112 0.084 32.136 ;
    END
  END a_cfg_data[66]
  PIN a_cfg_data[67]
    DIRECTION OUTPUT ;
    USE SIGNAL ;
    PORT
      LAYER M4 ;
        RECT  0 32.208 0.084 32.232 ;
    END
  END a_cfg_data[67]
  PIN a_cfg_data[68]
    DIRECTION OUTPUT ;
    USE SIGNAL ;
    PORT
      LAYER M4 ;
        RECT  0 32.304 0.084 32.328 ;
    END
  END a_cfg_data[68]
  PIN a_cfg_data[69]
    DIRECTION OUTPUT ;
    USE SIGNAL ;
    PORT
      LAYER M4 ;
        RECT  0 32.4 0.084 32.424 ;
    END
  END a_cfg_data[69]
  PIN a_cfg_data[6]
    DIRECTION OUTPUT ;
    USE SIGNAL ;
    PORT
      LAYER M4 ;
        RECT  0 38.64 0.084 38.664 ;
    END
  END a_cfg_data[6]
  PIN a_cfg_data[70]
    DIRECTION OUTPUT ;
    USE SIGNAL ;
    PORT
      LAYER M4 ;
        RECT  0 32.496 0.084 32.52 ;
    END
  END a_cfg_data[70]
  PIN a_cfg_data[71]
    DIRECTION OUTPUT ;
    USE SIGNAL ;
    PORT
      LAYER M4 ;
        RECT  0 32.592 0.084 32.616 ;
    END
  END a_cfg_data[71]
  PIN a_cfg_data[72]
    DIRECTION OUTPUT ;
    USE SIGNAL ;
    PORT
      LAYER M4 ;
        RECT  0 32.688 0.084 32.712 ;
    END
  END a_cfg_data[72]
  PIN a_cfg_data[73]
    DIRECTION OUTPUT ;
    USE SIGNAL ;
    PORT
      LAYER M4 ;
        RECT  0 32.784 0.084 32.808 ;
    END
  END a_cfg_data[73]
  PIN a_cfg_data[74]
    DIRECTION OUTPUT ;
    USE SIGNAL ;
    PORT
      LAYER M4 ;
        RECT  0 32.88 0.084 32.904 ;
    END
  END a_cfg_data[74]
  PIN a_cfg_data[75]
    DIRECTION OUTPUT ;
    USE SIGNAL ;
    PORT
      LAYER M4 ;
        RECT  0 32.976 0.084 33 ;
    END
  END a_cfg_data[75]
  PIN a_cfg_data[76]
    DIRECTION OUTPUT ;
    USE SIGNAL ;
    PORT
      LAYER M4 ;
        RECT  0 33.072 0.084 33.096 ;
    END
  END a_cfg_data[76]
  PIN a_cfg_data[77]
    DIRECTION OUTPUT ;
    USE SIGNAL ;
    PORT
      LAYER M4 ;
        RECT  0 33.168 0.084 33.192 ;
    END
  END a_cfg_data[77]
  PIN a_cfg_data[78]
    DIRECTION OUTPUT ;
    USE SIGNAL ;
    PORT
      LAYER M4 ;
        RECT  0 33.264 0.084 33.288 ;
    END
  END a_cfg_data[78]
  PIN a_cfg_data[79]
    DIRECTION OUTPUT ;
    USE SIGNAL ;
    PORT
      LAYER M4 ;
        RECT  0 33.36 0.084 33.384 ;
    END
  END a_cfg_data[79]
  PIN a_cfg_data[7]
    DIRECTION OUTPUT ;
    USE SIGNAL ;
    PORT
      LAYER M4 ;
        RECT  0 38.736 0.084 38.76 ;
    END
  END a_cfg_data[7]
  PIN a_cfg_data[80]
    DIRECTION OUTPUT ;
    USE SIGNAL ;
    PORT
      LAYER M4 ;
        RECT  0 33.456 0.084 33.48 ;
    END
  END a_cfg_data[80]
  PIN a_cfg_data[81]
    DIRECTION OUTPUT ;
    USE SIGNAL ;
    PORT
      LAYER M4 ;
        RECT  0 33.552 0.084 33.576 ;
    END
  END a_cfg_data[81]
  PIN a_cfg_data[82]
    DIRECTION OUTPUT ;
    USE SIGNAL ;
    PORT
      LAYER M4 ;
        RECT  0 33.648 0.084 33.672 ;
    END
  END a_cfg_data[82]
  PIN a_cfg_data[83]
    DIRECTION OUTPUT ;
    USE SIGNAL ;
    PORT
      LAYER M4 ;
        RECT  0 33.744 0.084 33.768 ;
    END
  END a_cfg_data[83]
  PIN a_cfg_data[84]
    DIRECTION OUTPUT ;
    USE SIGNAL ;
    PORT
      LAYER M4 ;
        RECT  0 43.056 0.084 43.08 ;
    END
  END a_cfg_data[84]
  PIN a_cfg_data[85]
    DIRECTION OUTPUT ;
    USE SIGNAL ;
    PORT
      LAYER M4 ;
        RECT  0 43.152 0.084 43.176 ;
    END
  END a_cfg_data[85]
  PIN a_cfg_data[86]
    DIRECTION OUTPUT ;
    USE SIGNAL ;
    PORT
      LAYER M4 ;
        RECT  0 43.248 0.084 43.272 ;
    END
  END a_cfg_data[86]
  PIN a_cfg_data[87]
    DIRECTION OUTPUT ;
    USE SIGNAL ;
    PORT
      LAYER M4 ;
        RECT  0 43.344 0.084 43.368 ;
    END
  END a_cfg_data[87]
  PIN a_cfg_data[88]
    DIRECTION OUTPUT ;
    USE SIGNAL ;
    PORT
      LAYER M4 ;
        RECT  0 43.44 0.084 43.464 ;
    END
  END a_cfg_data[88]
  PIN a_cfg_data[89]
    DIRECTION OUTPUT ;
    USE SIGNAL ;
    PORT
      LAYER M4 ;
        RECT  0 43.536 0.084 43.56 ;
    END
  END a_cfg_data[89]
  PIN a_cfg_data[8]
    DIRECTION OUTPUT ;
    USE SIGNAL ;
    PORT
      LAYER M4 ;
        RECT  0 38.832 0.084 38.856 ;
    END
  END a_cfg_data[8]
  PIN a_cfg_data[90]
    DIRECTION OUTPUT ;
    USE SIGNAL ;
    PORT
      LAYER M4 ;
        RECT  0 43.632 0.084 43.656 ;
    END
  END a_cfg_data[90]
  PIN a_cfg_data[91]
    DIRECTION OUTPUT ;
    USE SIGNAL ;
    PORT
      LAYER M4 ;
        RECT  0 43.728 0.084 43.752 ;
    END
  END a_cfg_data[91]
  PIN a_cfg_data[92]
    DIRECTION OUTPUT ;
    USE SIGNAL ;
    PORT
      LAYER M4 ;
        RECT  0 43.824 0.084 43.848 ;
    END
  END a_cfg_data[92]
  PIN a_cfg_data[93]
    DIRECTION OUTPUT ;
    USE SIGNAL ;
    PORT
      LAYER M4 ;
        RECT  0 43.92 0.084 43.944 ;
    END
  END a_cfg_data[93]
  PIN a_cfg_data[94]
    DIRECTION OUTPUT ;
    USE SIGNAL ;
    PORT
      LAYER M4 ;
        RECT  0 44.016 0.084 44.04 ;
    END
  END a_cfg_data[94]
  PIN a_cfg_data[95]
    DIRECTION OUTPUT ;
    USE SIGNAL ;
    PORT
      LAYER M4 ;
        RECT  0 44.112 0.084 44.136 ;
    END
  END a_cfg_data[95]
  PIN a_cfg_data[96]
    DIRECTION OUTPUT ;
    USE SIGNAL ;
    PORT
      LAYER M4 ;
        RECT  0 44.208 0.084 44.232 ;
    END
  END a_cfg_data[96]
  PIN a_cfg_data[97]
    DIRECTION OUTPUT ;
    USE SIGNAL ;
    PORT
      LAYER M4 ;
        RECT  0 44.304 0.084 44.328 ;
    END
  END a_cfg_data[97]
  PIN a_cfg_data[98]
    DIRECTION OUTPUT ;
    USE SIGNAL ;
    PORT
      LAYER M4 ;
        RECT  0 44.4 0.084 44.424 ;
    END
  END a_cfg_data[98]
  PIN a_cfg_data[99]
    DIRECTION OUTPUT ;
    USE SIGNAL ;
    PORT
      LAYER M4 ;
        RECT  0 44.496 0.084 44.52 ;
    END
  END a_cfg_data[99]
  PIN a_cfg_data[9]
    DIRECTION OUTPUT ;
    USE SIGNAL ;
    PORT
      LAYER M4 ;
        RECT  0 38.928 0.084 38.952 ;
    END
  END a_cfg_data[9]
  PIN a_cfg_target[0]
    DIRECTION OUTPUT ;
    USE SIGNAL ;
    PORT
      LAYER M4 ;
        RECT  0 28.08 0.084 28.104 ;
    END
  END a_cfg_target[0]
  PIN a_cfg_target[1]
    DIRECTION OUTPUT ;
    USE SIGNAL ;
    PORT
      LAYER M4 ;
        RECT  0 28.176 0.084 28.2 ;
    END
  END a_cfg_target[1]
  PIN a_cfg_target[2]
    DIRECTION OUTPUT ;
    USE SIGNAL ;
    PORT
      LAYER M4 ;
        RECT  0 28.272 0.084 28.296 ;
    END
  END a_cfg_target[2]
  PIN a_cfg_target[3]
    DIRECTION OUTPUT ;
    USE SIGNAL ;
    PORT
      LAYER M4 ;
        RECT  0 28.368 0.084 28.392 ;
    END
  END a_cfg_target[3]
  PIN a_cfg_target[4]
    DIRECTION OUTPUT ;
    USE SIGNAL ;
    PORT
      LAYER M4 ;
        RECT  0 28.464 0.084 28.488 ;
    END
  END a_cfg_target[4]
  PIN a_cfg_target[5]
    DIRECTION OUTPUT ;
    USE SIGNAL ;
    PORT
      LAYER M4 ;
        RECT  0 28.56 0.084 28.584 ;
    END
  END a_cfg_target[5]
  PIN a_cfg_target[6]
    DIRECTION OUTPUT ;
    USE SIGNAL ;
    PORT
      LAYER M4 ;
        RECT  0 28.656 0.084 28.68 ;
    END
  END a_cfg_target[6]
  PIN a_cfg_target[7]
    DIRECTION OUTPUT ;
    USE SIGNAL ;
    PORT
      LAYER M4 ;
        RECT  0 28.752 0.084 28.776 ;
    END
  END a_cfg_target[7]
  PIN a_cfg_v
    DIRECTION OUTPUT ;
    USE SIGNAL ;
    PORT
      LAYER M4 ;
        RECT  0 28.848 0.084 28.872 ;
    END
  END a_cfg_v
  PIN a_desc_base[0]
    DIRECTION OUTPUT ;
    USE SIGNAL ;
    PORT
      LAYER M4 ;
        RECT  0 28.944 0.084 28.968 ;
    END
  END a_desc_base[0]
  PIN a_desc_base[10]
    DIRECTION OUTPUT ;
    USE SIGNAL ;
    PORT
      LAYER M4 ;
        RECT  0 29.904 0.084 29.928 ;
    END
  END a_desc_base[10]
  PIN a_desc_base[11]
    DIRECTION OUTPUT ;
    USE SIGNAL ;
    PORT
      LAYER M4 ;
        RECT  0 20.784 0.084 20.808 ;
    END
  END a_desc_base[11]
  PIN a_desc_base[1]
    DIRECTION OUTPUT ;
    USE SIGNAL ;
    PORT
      LAYER M4 ;
        RECT  0 29.04 0.084 29.064 ;
    END
  END a_desc_base[1]
  PIN a_desc_base[2]
    DIRECTION OUTPUT ;
    USE SIGNAL ;
    PORT
      LAYER M4 ;
        RECT  0 29.136 0.084 29.16 ;
    END
  END a_desc_base[2]
  PIN a_desc_base[3]
    DIRECTION OUTPUT ;
    USE SIGNAL ;
    PORT
      LAYER M4 ;
        RECT  0 29.232 0.084 29.256 ;
    END
  END a_desc_base[3]
  PIN a_desc_base[4]
    DIRECTION OUTPUT ;
    USE SIGNAL ;
    PORT
      LAYER M4 ;
        RECT  0 29.328 0.084 29.352 ;
    END
  END a_desc_base[4]
  PIN a_desc_base[5]
    DIRECTION OUTPUT ;
    USE SIGNAL ;
    PORT
      LAYER M4 ;
        RECT  0 29.424 0.084 29.448 ;
    END
  END a_desc_base[5]
  PIN a_desc_base[6]
    DIRECTION OUTPUT ;
    USE SIGNAL ;
    PORT
      LAYER M4 ;
        RECT  0 29.52 0.084 29.544 ;
    END
  END a_desc_base[6]
  PIN a_desc_base[7]
    DIRECTION OUTPUT ;
    USE SIGNAL ;
    PORT
      LAYER M4 ;
        RECT  0 29.616 0.084 29.64 ;
    END
  END a_desc_base[7]
  PIN a_desc_base[8]
    DIRECTION OUTPUT ;
    USE SIGNAL ;
    PORT
      LAYER M4 ;
        RECT  0 29.712 0.084 29.736 ;
    END
  END a_desc_base[8]
  PIN a_desc_base[9]
    DIRECTION OUTPUT ;
    USE SIGNAL ;
    PORT
      LAYER M4 ;
        RECT  0 29.808 0.084 29.832 ;
    END
  END a_desc_base[9]
  PIN a_desc_limit[0]
    DIRECTION OUTPUT ;
    USE SIGNAL ;
    PORT
      LAYER M4 ;
        RECT  0 20.88 0.084 20.904 ;
    END
  END a_desc_limit[0]
  PIN a_desc_limit[10]
    DIRECTION OUTPUT ;
    USE SIGNAL ;
    PORT
      LAYER M4 ;
        RECT  0 21.84 0.084 21.864 ;
    END
  END a_desc_limit[10]
  PIN a_desc_limit[11]
    DIRECTION OUTPUT ;
    USE SIGNAL ;
    PORT
      LAYER M4 ;
        RECT  0 21.936 0.084 21.96 ;
    END
  END a_desc_limit[11]
  PIN a_desc_limit[12]
    DIRECTION OUTPUT ;
    USE SIGNAL ;
    PORT
      LAYER M4 ;
        RECT  0 22.032 0.084 22.056 ;
    END
  END a_desc_limit[12]
  PIN a_desc_limit[1]
    DIRECTION OUTPUT ;
    USE SIGNAL ;
    PORT
      LAYER M4 ;
        RECT  0 20.976 0.084 21 ;
    END
  END a_desc_limit[1]
  PIN a_desc_limit[2]
    DIRECTION OUTPUT ;
    USE SIGNAL ;
    PORT
      LAYER M4 ;
        RECT  0 21.072 0.084 21.096 ;
    END
  END a_desc_limit[2]
  PIN a_desc_limit[3]
    DIRECTION OUTPUT ;
    USE SIGNAL ;
    PORT
      LAYER M4 ;
        RECT  0 21.168 0.084 21.192 ;
    END
  END a_desc_limit[3]
  PIN a_desc_limit[4]
    DIRECTION OUTPUT ;
    USE SIGNAL ;
    PORT
      LAYER M4 ;
        RECT  0 21.264 0.084 21.288 ;
    END
  END a_desc_limit[4]
  PIN a_desc_limit[5]
    DIRECTION OUTPUT ;
    USE SIGNAL ;
    PORT
      LAYER M4 ;
        RECT  0 21.36 0.084 21.384 ;
    END
  END a_desc_limit[5]
  PIN a_desc_limit[6]
    DIRECTION OUTPUT ;
    USE SIGNAL ;
    PORT
      LAYER M4 ;
        RECT  0 21.456 0.084 21.48 ;
    END
  END a_desc_limit[6]
  PIN a_desc_limit[7]
    DIRECTION OUTPUT ;
    USE SIGNAL ;
    PORT
      LAYER M4 ;
        RECT  0 21.552 0.084 21.576 ;
    END
  END a_desc_limit[7]
  PIN a_desc_limit[8]
    DIRECTION OUTPUT ;
    USE SIGNAL ;
    PORT
      LAYER M4 ;
        RECT  0 21.648 0.084 21.672 ;
    END
  END a_desc_limit[8]
  PIN a_desc_limit[9]
    DIRECTION OUTPUT ;
    USE SIGNAL ;
    PORT
      LAYER M4 ;
        RECT  0 21.744 0.084 21.768 ;
    END
  END a_desc_limit[9]
  PIN a_desc_loops[0]
    DIRECTION OUTPUT ;
    USE SIGNAL ;
    PORT
      LAYER M4 ;
        RECT  0 22.128 0.084 22.152 ;
    END
  END a_desc_loops[0]
  PIN a_desc_loops[10]
    DIRECTION OUTPUT ;
    USE SIGNAL ;
    PORT
      LAYER M4 ;
        RECT  0 23.088 0.084 23.112 ;
    END
  END a_desc_loops[10]
  PIN a_desc_loops[11]
    DIRECTION OUTPUT ;
    USE SIGNAL ;
    PORT
      LAYER M4 ;
        RECT  0 23.184 0.084 23.208 ;
    END
  END a_desc_loops[11]
  PIN a_desc_loops[12]
    DIRECTION OUTPUT ;
    USE SIGNAL ;
    PORT
      LAYER M4 ;
        RECT  0 23.28 0.084 23.304 ;
    END
  END a_desc_loops[12]
  PIN a_desc_loops[13]
    DIRECTION OUTPUT ;
    USE SIGNAL ;
    PORT
      LAYER M4 ;
        RECT  0 23.376 0.084 23.4 ;
    END
  END a_desc_loops[13]
  PIN a_desc_loops[14]
    DIRECTION OUTPUT ;
    USE SIGNAL ;
    PORT
      LAYER M4 ;
        RECT  0 23.472 0.084 23.496 ;
    END
  END a_desc_loops[14]
  PIN a_desc_loops[15]
    DIRECTION OUTPUT ;
    USE SIGNAL ;
    PORT
      LAYER M4 ;
        RECT  0 23.568 0.084 23.592 ;
    END
  END a_desc_loops[15]
  PIN a_desc_loops[1]
    DIRECTION OUTPUT ;
    USE SIGNAL ;
    PORT
      LAYER M4 ;
        RECT  0 22.224 0.084 22.248 ;
    END
  END a_desc_loops[1]
  PIN a_desc_loops[2]
    DIRECTION OUTPUT ;
    USE SIGNAL ;
    PORT
      LAYER M4 ;
        RECT  0 22.32 0.084 22.344 ;
    END
  END a_desc_loops[2]
  PIN a_desc_loops[3]
    DIRECTION OUTPUT ;
    USE SIGNAL ;
    PORT
      LAYER M4 ;
        RECT  0 22.416 0.084 22.44 ;
    END
  END a_desc_loops[3]
  PIN a_desc_loops[4]
    DIRECTION OUTPUT ;
    USE SIGNAL ;
    PORT
      LAYER M4 ;
        RECT  0 22.512 0.084 22.536 ;
    END
  END a_desc_loops[4]
  PIN a_desc_loops[5]
    DIRECTION OUTPUT ;
    USE SIGNAL ;
    PORT
      LAYER M4 ;
        RECT  0 22.608 0.084 22.632 ;
    END
  END a_desc_loops[5]
  PIN a_desc_loops[6]
    DIRECTION OUTPUT ;
    USE SIGNAL ;
    PORT
      LAYER M4 ;
        RECT  0 22.704 0.084 22.728 ;
    END
  END a_desc_loops[6]
  PIN a_desc_loops[7]
    DIRECTION OUTPUT ;
    USE SIGNAL ;
    PORT
      LAYER M4 ;
        RECT  0 22.8 0.084 22.824 ;
    END
  END a_desc_loops[7]
  PIN a_desc_loops[8]
    DIRECTION OUTPUT ;
    USE SIGNAL ;
    PORT
      LAYER M4 ;
        RECT  0 22.896 0.084 22.92 ;
    END
  END a_desc_loops[8]
  PIN a_desc_loops[9]
    DIRECTION OUTPUT ;
    USE SIGNAL ;
    PORT
      LAYER M4 ;
        RECT  0 22.992 0.084 23.016 ;
    END
  END a_desc_loops[9]
  PIN a_desc_v
    DIRECTION OUTPUT ;
    USE SIGNAL ;
    PORT
      LAYER M4 ;
        RECT  0 23.664 0.084 23.688 ;
    END
  END a_desc_v
  PIN a_launch_v
    DIRECTION OUTPUT ;
    USE SIGNAL ;
    PORT
      LAYER M4 ;
        RECT  0 23.76 0.084 23.784 ;
    END
  END a_launch_v
  PIN b_cfg_addr[0]
    DIRECTION OUTPUT ;
    USE SIGNAL ;
    PORT
      LAYER M4 ;
        RECT  69.036 32.208 69.12 32.232 ;
    END
  END b_cfg_addr[0]
  PIN b_cfg_addr[10]
    DIRECTION OUTPUT ;
    USE SIGNAL ;
    PORT
      LAYER M4 ;
        RECT  69.036 33.168 69.12 33.192 ;
    END
  END b_cfg_addr[10]
  PIN b_cfg_addr[11]
    DIRECTION OUTPUT ;
    USE SIGNAL ;
    PORT
      LAYER M4 ;
        RECT  69.036 33.264 69.12 33.288 ;
    END
  END b_cfg_addr[11]
  PIN b_cfg_addr[1]
    DIRECTION OUTPUT ;
    USE SIGNAL ;
    PORT
      LAYER M4 ;
        RECT  69.036 32.304 69.12 32.328 ;
    END
  END b_cfg_addr[1]
  PIN b_cfg_addr[2]
    DIRECTION OUTPUT ;
    USE SIGNAL ;
    PORT
      LAYER M4 ;
        RECT  69.036 32.4 69.12 32.424 ;
    END
  END b_cfg_addr[2]
  PIN b_cfg_addr[3]
    DIRECTION OUTPUT ;
    USE SIGNAL ;
    PORT
      LAYER M4 ;
        RECT  69.036 32.496 69.12 32.52 ;
    END
  END b_cfg_addr[3]
  PIN b_cfg_addr[4]
    DIRECTION OUTPUT ;
    USE SIGNAL ;
    PORT
      LAYER M4 ;
        RECT  69.036 32.592 69.12 32.616 ;
    END
  END b_cfg_addr[4]
  PIN b_cfg_addr[5]
    DIRECTION OUTPUT ;
    USE SIGNAL ;
    PORT
      LAYER M4 ;
        RECT  69.036 32.688 69.12 32.712 ;
    END
  END b_cfg_addr[5]
  PIN b_cfg_addr[6]
    DIRECTION OUTPUT ;
    USE SIGNAL ;
    PORT
      LAYER M4 ;
        RECT  69.036 32.784 69.12 32.808 ;
    END
  END b_cfg_addr[6]
  PIN b_cfg_addr[7]
    DIRECTION OUTPUT ;
    USE SIGNAL ;
    PORT
      LAYER M4 ;
        RECT  69.036 32.88 69.12 32.904 ;
    END
  END b_cfg_addr[7]
  PIN b_cfg_addr[8]
    DIRECTION OUTPUT ;
    USE SIGNAL ;
    PORT
      LAYER M4 ;
        RECT  69.036 32.976 69.12 33 ;
    END
  END b_cfg_addr[8]
  PIN b_cfg_addr[9]
    DIRECTION OUTPUT ;
    USE SIGNAL ;
    PORT
      LAYER M4 ;
        RECT  69.036 33.072 69.12 33.096 ;
    END
  END b_cfg_addr[9]
  PIN b_cfg_data[0]
    DIRECTION OUTPUT ;
    USE SIGNAL ;
    PORT
      LAYER M4 ;
        RECT  69.036 33.36 69.12 33.384 ;
    END
  END b_cfg_data[0]
  PIN b_cfg_data[100]
    DIRECTION OUTPUT ;
    USE SIGNAL ;
    PORT
      LAYER M4 ;
        RECT  69.036 49.872 69.12 49.896 ;
    END
  END b_cfg_data[100]
  PIN b_cfg_data[101]
    DIRECTION OUTPUT ;
    USE SIGNAL ;
    PORT
      LAYER M4 ;
        RECT  69.036 49.968 69.12 49.992 ;
    END
  END b_cfg_data[101]
  PIN b_cfg_data[102]
    DIRECTION OUTPUT ;
    USE SIGNAL ;
    PORT
      LAYER M4 ;
        RECT  69.036 50.064 69.12 50.088 ;
    END
  END b_cfg_data[102]
  PIN b_cfg_data[103]
    DIRECTION OUTPUT ;
    USE SIGNAL ;
    PORT
      LAYER M4 ;
        RECT  69.036 50.16 69.12 50.184 ;
    END
  END b_cfg_data[103]
  PIN b_cfg_data[104]
    DIRECTION OUTPUT ;
    USE SIGNAL ;
    PORT
      LAYER M4 ;
        RECT  69.036 50.256 69.12 50.28 ;
    END
  END b_cfg_data[104]
  PIN b_cfg_data[105]
    DIRECTION OUTPUT ;
    USE SIGNAL ;
    PORT
      LAYER M4 ;
        RECT  69.036 50.352 69.12 50.376 ;
    END
  END b_cfg_data[105]
  PIN b_cfg_data[106]
    DIRECTION OUTPUT ;
    USE SIGNAL ;
    PORT
      LAYER M4 ;
        RECT  69.036 50.448 69.12 50.472 ;
    END
  END b_cfg_data[106]
  PIN b_cfg_data[107]
    DIRECTION OUTPUT ;
    USE SIGNAL ;
    PORT
      LAYER M4 ;
        RECT  69.036 50.544 69.12 50.568 ;
    END
  END b_cfg_data[107]
  PIN b_cfg_data[108]
    DIRECTION OUTPUT ;
    USE SIGNAL ;
    PORT
      LAYER M4 ;
        RECT  69.036 50.64 69.12 50.664 ;
    END
  END b_cfg_data[108]
  PIN b_cfg_data[109]
    DIRECTION OUTPUT ;
    USE SIGNAL ;
    PORT
      LAYER M4 ;
        RECT  69.036 50.736 69.12 50.76 ;
    END
  END b_cfg_data[109]
  PIN b_cfg_data[10]
    DIRECTION OUTPUT ;
    USE SIGNAL ;
    PORT
      LAYER M4 ;
        RECT  69.036 34.32 69.12 34.344 ;
    END
  END b_cfg_data[10]
  PIN b_cfg_data[110]
    DIRECTION OUTPUT ;
    USE SIGNAL ;
    PORT
      LAYER M4 ;
        RECT  69.036 50.832 69.12 50.856 ;
    END
  END b_cfg_data[110]
  PIN b_cfg_data[111]
    DIRECTION OUTPUT ;
    USE SIGNAL ;
    PORT
      LAYER M4 ;
        RECT  69.036 50.928 69.12 50.952 ;
    END
  END b_cfg_data[111]
  PIN b_cfg_data[112]
    DIRECTION OUTPUT ;
    USE SIGNAL ;
    PORT
      LAYER M4 ;
        RECT  69.036 51.024 69.12 51.048 ;
    END
  END b_cfg_data[112]
  PIN b_cfg_data[113]
    DIRECTION OUTPUT ;
    USE SIGNAL ;
    PORT
      LAYER M4 ;
        RECT  69.036 51.12 69.12 51.144 ;
    END
  END b_cfg_data[113]
  PIN b_cfg_data[114]
    DIRECTION OUTPUT ;
    USE SIGNAL ;
    PORT
      LAYER M4 ;
        RECT  69.036 51.216 69.12 51.24 ;
    END
  END b_cfg_data[114]
  PIN b_cfg_data[115]
    DIRECTION OUTPUT ;
    USE SIGNAL ;
    PORT
      LAYER M4 ;
        RECT  69.036 51.312 69.12 51.336 ;
    END
  END b_cfg_data[115]
  PIN b_cfg_data[116]
    DIRECTION OUTPUT ;
    USE SIGNAL ;
    PORT
      LAYER M4 ;
        RECT  69.036 22.992 69.12 23.016 ;
    END
  END b_cfg_data[116]
  PIN b_cfg_data[117]
    DIRECTION OUTPUT ;
    USE SIGNAL ;
    PORT
      LAYER M4 ;
        RECT  69.036 23.088 69.12 23.112 ;
    END
  END b_cfg_data[117]
  PIN b_cfg_data[118]
    DIRECTION OUTPUT ;
    USE SIGNAL ;
    PORT
      LAYER M4 ;
        RECT  69.036 23.184 69.12 23.208 ;
    END
  END b_cfg_data[118]
  PIN b_cfg_data[119]
    DIRECTION OUTPUT ;
    USE SIGNAL ;
    PORT
      LAYER M4 ;
        RECT  69.036 23.28 69.12 23.304 ;
    END
  END b_cfg_data[119]
  PIN b_cfg_data[11]
    DIRECTION OUTPUT ;
    USE SIGNAL ;
    PORT
      LAYER M4 ;
        RECT  69.036 34.416 69.12 34.44 ;
    END
  END b_cfg_data[11]
  PIN b_cfg_data[120]
    DIRECTION OUTPUT ;
    USE SIGNAL ;
    PORT
      LAYER M4 ;
        RECT  69.036 23.376 69.12 23.4 ;
    END
  END b_cfg_data[120]
  PIN b_cfg_data[121]
    DIRECTION OUTPUT ;
    USE SIGNAL ;
    PORT
      LAYER M4 ;
        RECT  69.036 23.472 69.12 23.496 ;
    END
  END b_cfg_data[121]
  PIN b_cfg_data[122]
    DIRECTION OUTPUT ;
    USE SIGNAL ;
    PORT
      LAYER M4 ;
        RECT  69.036 23.568 69.12 23.592 ;
    END
  END b_cfg_data[122]
  PIN b_cfg_data[123]
    DIRECTION OUTPUT ;
    USE SIGNAL ;
    PORT
      LAYER M4 ;
        RECT  69.036 23.664 69.12 23.688 ;
    END
  END b_cfg_data[123]
  PIN b_cfg_data[124]
    DIRECTION OUTPUT ;
    USE SIGNAL ;
    PORT
      LAYER M4 ;
        RECT  69.036 23.76 69.12 23.784 ;
    END
  END b_cfg_data[124]
  PIN b_cfg_data[125]
    DIRECTION OUTPUT ;
    USE SIGNAL ;
    PORT
      LAYER M4 ;
        RECT  69.036 23.856 69.12 23.88 ;
    END
  END b_cfg_data[125]
  PIN b_cfg_data[126]
    DIRECTION OUTPUT ;
    USE SIGNAL ;
    PORT
      LAYER M4 ;
        RECT  69.036 23.952 69.12 23.976 ;
    END
  END b_cfg_data[126]
  PIN b_cfg_data[127]
    DIRECTION OUTPUT ;
    USE SIGNAL ;
    PORT
      LAYER M4 ;
        RECT  69.036 24.048 69.12 24.072 ;
    END
  END b_cfg_data[127]
  PIN b_cfg_data[128]
    DIRECTION OUTPUT ;
    USE SIGNAL ;
    PORT
      LAYER M4 ;
        RECT  69.036 24.144 69.12 24.168 ;
    END
  END b_cfg_data[128]
  PIN b_cfg_data[129]
    DIRECTION OUTPUT ;
    USE SIGNAL ;
    PORT
      LAYER M4 ;
        RECT  69.036 24.24 69.12 24.264 ;
    END
  END b_cfg_data[129]
  PIN b_cfg_data[12]
    DIRECTION OUTPUT ;
    USE SIGNAL ;
    PORT
      LAYER M4 ;
        RECT  69.036 34.512 69.12 34.536 ;
    END
  END b_cfg_data[12]
  PIN b_cfg_data[130]
    DIRECTION OUTPUT ;
    USE SIGNAL ;
    PORT
      LAYER M4 ;
        RECT  69.036 24.336 69.12 24.36 ;
    END
  END b_cfg_data[130]
  PIN b_cfg_data[131]
    DIRECTION OUTPUT ;
    USE SIGNAL ;
    PORT
      LAYER M4 ;
        RECT  69.036 24.432 69.12 24.456 ;
    END
  END b_cfg_data[131]
  PIN b_cfg_data[132]
    DIRECTION OUTPUT ;
    USE SIGNAL ;
    PORT
      LAYER M4 ;
        RECT  69.036 24.528 69.12 24.552 ;
    END
  END b_cfg_data[132]
  PIN b_cfg_data[133]
    DIRECTION OUTPUT ;
    USE SIGNAL ;
    PORT
      LAYER M4 ;
        RECT  69.036 24.624 69.12 24.648 ;
    END
  END b_cfg_data[133]
  PIN b_cfg_data[134]
    DIRECTION OUTPUT ;
    USE SIGNAL ;
    PORT
      LAYER M4 ;
        RECT  69.036 24.72 69.12 24.744 ;
    END
  END b_cfg_data[134]
  PIN b_cfg_data[135]
    DIRECTION OUTPUT ;
    USE SIGNAL ;
    PORT
      LAYER M4 ;
        RECT  69.036 24.816 69.12 24.84 ;
    END
  END b_cfg_data[135]
  PIN b_cfg_data[136]
    DIRECTION OUTPUT ;
    USE SIGNAL ;
    PORT
      LAYER M4 ;
        RECT  69.036 24.912 69.12 24.936 ;
    END
  END b_cfg_data[136]
  PIN b_cfg_data[137]
    DIRECTION OUTPUT ;
    USE SIGNAL ;
    PORT
      LAYER M4 ;
        RECT  69.036 25.008 69.12 25.032 ;
    END
  END b_cfg_data[137]
  PIN b_cfg_data[138]
    DIRECTION OUTPUT ;
    USE SIGNAL ;
    PORT
      LAYER M4 ;
        RECT  69.036 25.104 69.12 25.128 ;
    END
  END b_cfg_data[138]
  PIN b_cfg_data[139]
    DIRECTION OUTPUT ;
    USE SIGNAL ;
    PORT
      LAYER M4 ;
        RECT  69.036 25.2 69.12 25.224 ;
    END
  END b_cfg_data[139]
  PIN b_cfg_data[13]
    DIRECTION OUTPUT ;
    USE SIGNAL ;
    PORT
      LAYER M4 ;
        RECT  69.036 34.608 69.12 34.632 ;
    END
  END b_cfg_data[13]
  PIN b_cfg_data[140]
    DIRECTION OUTPUT ;
    USE SIGNAL ;
    PORT
      LAYER M4 ;
        RECT  69.036 25.296 69.12 25.32 ;
    END
  END b_cfg_data[140]
  PIN b_cfg_data[141]
    DIRECTION OUTPUT ;
    USE SIGNAL ;
    PORT
      LAYER M4 ;
        RECT  69.036 25.392 69.12 25.416 ;
    END
  END b_cfg_data[141]
  PIN b_cfg_data[142]
    DIRECTION OUTPUT ;
    USE SIGNAL ;
    PORT
      LAYER M4 ;
        RECT  69.036 25.488 69.12 25.512 ;
    END
  END b_cfg_data[142]
  PIN b_cfg_data[143]
    DIRECTION OUTPUT ;
    USE SIGNAL ;
    PORT
      LAYER M4 ;
        RECT  69.036 25.584 69.12 25.608 ;
    END
  END b_cfg_data[143]
  PIN b_cfg_data[144]
    DIRECTION OUTPUT ;
    USE SIGNAL ;
    PORT
      LAYER M4 ;
        RECT  69.036 25.68 69.12 25.704 ;
    END
  END b_cfg_data[144]
  PIN b_cfg_data[145]
    DIRECTION OUTPUT ;
    USE SIGNAL ;
    PORT
      LAYER M4 ;
        RECT  69.036 25.776 69.12 25.8 ;
    END
  END b_cfg_data[145]
  PIN b_cfg_data[146]
    DIRECTION OUTPUT ;
    USE SIGNAL ;
    PORT
      LAYER M4 ;
        RECT  69.036 25.872 69.12 25.896 ;
    END
  END b_cfg_data[146]
  PIN b_cfg_data[147]
    DIRECTION OUTPUT ;
    USE SIGNAL ;
    PORT
      LAYER M4 ;
        RECT  69.036 25.968 69.12 25.992 ;
    END
  END b_cfg_data[147]
  PIN b_cfg_data[148]
    DIRECTION OUTPUT ;
    USE SIGNAL ;
    PORT
      LAYER M4 ;
        RECT  69.036 35.28 69.12 35.304 ;
    END
  END b_cfg_data[148]
  PIN b_cfg_data[149]
    DIRECTION OUTPUT ;
    USE SIGNAL ;
    PORT
      LAYER M4 ;
        RECT  69.036 35.376 69.12 35.4 ;
    END
  END b_cfg_data[149]
  PIN b_cfg_data[14]
    DIRECTION OUTPUT ;
    USE SIGNAL ;
    PORT
      LAYER M4 ;
        RECT  69.036 34.704 69.12 34.728 ;
    END
  END b_cfg_data[14]
  PIN b_cfg_data[150]
    DIRECTION OUTPUT ;
    USE SIGNAL ;
    PORT
      LAYER M4 ;
        RECT  69.036 35.472 69.12 35.496 ;
    END
  END b_cfg_data[150]
  PIN b_cfg_data[151]
    DIRECTION OUTPUT ;
    USE SIGNAL ;
    PORT
      LAYER M4 ;
        RECT  69.036 35.568 69.12 35.592 ;
    END
  END b_cfg_data[151]
  PIN b_cfg_data[152]
    DIRECTION OUTPUT ;
    USE SIGNAL ;
    PORT
      LAYER M4 ;
        RECT  69.036 35.664 69.12 35.688 ;
    END
  END b_cfg_data[152]
  PIN b_cfg_data[153]
    DIRECTION OUTPUT ;
    USE SIGNAL ;
    PORT
      LAYER M4 ;
        RECT  69.036 35.76 69.12 35.784 ;
    END
  END b_cfg_data[153]
  PIN b_cfg_data[154]
    DIRECTION OUTPUT ;
    USE SIGNAL ;
    PORT
      LAYER M4 ;
        RECT  69.036 35.856 69.12 35.88 ;
    END
  END b_cfg_data[154]
  PIN b_cfg_data[155]
    DIRECTION OUTPUT ;
    USE SIGNAL ;
    PORT
      LAYER M4 ;
        RECT  69.036 35.952 69.12 35.976 ;
    END
  END b_cfg_data[155]
  PIN b_cfg_data[156]
    DIRECTION OUTPUT ;
    USE SIGNAL ;
    PORT
      LAYER M4 ;
        RECT  69.036 36.048 69.12 36.072 ;
    END
  END b_cfg_data[156]
  PIN b_cfg_data[157]
    DIRECTION OUTPUT ;
    USE SIGNAL ;
    PORT
      LAYER M4 ;
        RECT  69.036 36.144 69.12 36.168 ;
    END
  END b_cfg_data[157]
  PIN b_cfg_data[158]
    DIRECTION OUTPUT ;
    USE SIGNAL ;
    PORT
      LAYER M4 ;
        RECT  69.036 36.24 69.12 36.264 ;
    END
  END b_cfg_data[158]
  PIN b_cfg_data[159]
    DIRECTION OUTPUT ;
    USE SIGNAL ;
    PORT
      LAYER M4 ;
        RECT  69.036 36.336 69.12 36.36 ;
    END
  END b_cfg_data[159]
  PIN b_cfg_data[15]
    DIRECTION OUTPUT ;
    USE SIGNAL ;
    PORT
      LAYER M4 ;
        RECT  69.036 34.8 69.12 34.824 ;
    END
  END b_cfg_data[15]
  PIN b_cfg_data[160]
    DIRECTION OUTPUT ;
    USE SIGNAL ;
    PORT
      LAYER M4 ;
        RECT  69.036 36.432 69.12 36.456 ;
    END
  END b_cfg_data[160]
  PIN b_cfg_data[161]
    DIRECTION OUTPUT ;
    USE SIGNAL ;
    PORT
      LAYER M4 ;
        RECT  69.036 36.528 69.12 36.552 ;
    END
  END b_cfg_data[161]
  PIN b_cfg_data[162]
    DIRECTION OUTPUT ;
    USE SIGNAL ;
    PORT
      LAYER M4 ;
        RECT  69.036 36.624 69.12 36.648 ;
    END
  END b_cfg_data[162]
  PIN b_cfg_data[163]
    DIRECTION OUTPUT ;
    USE SIGNAL ;
    PORT
      LAYER M4 ;
        RECT  69.036 36.72 69.12 36.744 ;
    END
  END b_cfg_data[163]
  PIN b_cfg_data[164]
    DIRECTION OUTPUT ;
    USE SIGNAL ;
    PORT
      LAYER M4 ;
        RECT  69.036 36.816 69.12 36.84 ;
    END
  END b_cfg_data[164]
  PIN b_cfg_data[165]
    DIRECTION OUTPUT ;
    USE SIGNAL ;
    PORT
      LAYER M4 ;
        RECT  69.036 36.912 69.12 36.936 ;
    END
  END b_cfg_data[165]
  PIN b_cfg_data[166]
    DIRECTION OUTPUT ;
    USE SIGNAL ;
    PORT
      LAYER M4 ;
        RECT  69.036 37.008 69.12 37.032 ;
    END
  END b_cfg_data[166]
  PIN b_cfg_data[167]
    DIRECTION OUTPUT ;
    USE SIGNAL ;
    PORT
      LAYER M4 ;
        RECT  69.036 37.104 69.12 37.128 ;
    END
  END b_cfg_data[167]
  PIN b_cfg_data[168]
    DIRECTION OUTPUT ;
    USE SIGNAL ;
    PORT
      LAYER M4 ;
        RECT  69.036 37.2 69.12 37.224 ;
    END
  END b_cfg_data[168]
  PIN b_cfg_data[169]
    DIRECTION OUTPUT ;
    USE SIGNAL ;
    PORT
      LAYER M4 ;
        RECT  69.036 37.296 69.12 37.32 ;
    END
  END b_cfg_data[169]
  PIN b_cfg_data[16]
    DIRECTION OUTPUT ;
    USE SIGNAL ;
    PORT
      LAYER M4 ;
        RECT  69.036 34.896 69.12 34.92 ;
    END
  END b_cfg_data[16]
  PIN b_cfg_data[170]
    DIRECTION OUTPUT ;
    USE SIGNAL ;
    PORT
      LAYER M4 ;
        RECT  69.036 37.392 69.12 37.416 ;
    END
  END b_cfg_data[170]
  PIN b_cfg_data[171]
    DIRECTION OUTPUT ;
    USE SIGNAL ;
    PORT
      LAYER M4 ;
        RECT  69.036 37.488 69.12 37.512 ;
    END
  END b_cfg_data[171]
  PIN b_cfg_data[172]
    DIRECTION OUTPUT ;
    USE SIGNAL ;
    PORT
      LAYER M4 ;
        RECT  69.036 37.584 69.12 37.608 ;
    END
  END b_cfg_data[172]
  PIN b_cfg_data[173]
    DIRECTION OUTPUT ;
    USE SIGNAL ;
    PORT
      LAYER M4 ;
        RECT  69.036 37.68 69.12 37.704 ;
    END
  END b_cfg_data[173]
  PIN b_cfg_data[174]
    DIRECTION OUTPUT ;
    USE SIGNAL ;
    PORT
      LAYER M4 ;
        RECT  69.036 37.776 69.12 37.8 ;
    END
  END b_cfg_data[174]
  PIN b_cfg_data[175]
    DIRECTION OUTPUT ;
    USE SIGNAL ;
    PORT
      LAYER M4 ;
        RECT  69.036 37.872 69.12 37.896 ;
    END
  END b_cfg_data[175]
  PIN b_cfg_data[176]
    DIRECTION OUTPUT ;
    USE SIGNAL ;
    PORT
      LAYER M4 ;
        RECT  69.036 37.968 69.12 37.992 ;
    END
  END b_cfg_data[176]
  PIN b_cfg_data[177]
    DIRECTION OUTPUT ;
    USE SIGNAL ;
    PORT
      LAYER M4 ;
        RECT  69.036 38.064 69.12 38.088 ;
    END
  END b_cfg_data[177]
  PIN b_cfg_data[178]
    DIRECTION OUTPUT ;
    USE SIGNAL ;
    PORT
      LAYER M4 ;
        RECT  69.036 38.16 69.12 38.184 ;
    END
  END b_cfg_data[178]
  PIN b_cfg_data[179]
    DIRECTION OUTPUT ;
    USE SIGNAL ;
    PORT
      LAYER M4 ;
        RECT  69.036 38.256 69.12 38.28 ;
    END
  END b_cfg_data[179]
  PIN b_cfg_data[17]
    DIRECTION OUTPUT ;
    USE SIGNAL ;
    PORT
      LAYER M4 ;
        RECT  69.036 34.992 69.12 35.016 ;
    END
  END b_cfg_data[17]
  PIN b_cfg_data[180]
    DIRECTION OUTPUT ;
    USE SIGNAL ;
    PORT
      LAYER M4 ;
        RECT  69.036 19.92 69.12 19.944 ;
    END
  END b_cfg_data[180]
  PIN b_cfg_data[181]
    DIRECTION OUTPUT ;
    USE SIGNAL ;
    PORT
      LAYER M4 ;
        RECT  69.036 20.016 69.12 20.04 ;
    END
  END b_cfg_data[181]
  PIN b_cfg_data[182]
    DIRECTION OUTPUT ;
    USE SIGNAL ;
    PORT
      LAYER M4 ;
        RECT  69.036 20.112 69.12 20.136 ;
    END
  END b_cfg_data[182]
  PIN b_cfg_data[183]
    DIRECTION OUTPUT ;
    USE SIGNAL ;
    PORT
      LAYER M4 ;
        RECT  69.036 20.208 69.12 20.232 ;
    END
  END b_cfg_data[183]
  PIN b_cfg_data[184]
    DIRECTION OUTPUT ;
    USE SIGNAL ;
    PORT
      LAYER M4 ;
        RECT  69.036 20.304 69.12 20.328 ;
    END
  END b_cfg_data[184]
  PIN b_cfg_data[185]
    DIRECTION OUTPUT ;
    USE SIGNAL ;
    PORT
      LAYER M4 ;
        RECT  69.036 20.4 69.12 20.424 ;
    END
  END b_cfg_data[185]
  PIN b_cfg_data[186]
    DIRECTION OUTPUT ;
    USE SIGNAL ;
    PORT
      LAYER M4 ;
        RECT  69.036 20.496 69.12 20.52 ;
    END
  END b_cfg_data[186]
  PIN b_cfg_data[187]
    DIRECTION OUTPUT ;
    USE SIGNAL ;
    PORT
      LAYER M4 ;
        RECT  69.036 20.592 69.12 20.616 ;
    END
  END b_cfg_data[187]
  PIN b_cfg_data[188]
    DIRECTION OUTPUT ;
    USE SIGNAL ;
    PORT
      LAYER M4 ;
        RECT  69.036 20.688 69.12 20.712 ;
    END
  END b_cfg_data[188]
  PIN b_cfg_data[189]
    DIRECTION OUTPUT ;
    USE SIGNAL ;
    PORT
      LAYER M4 ;
        RECT  69.036 20.784 69.12 20.808 ;
    END
  END b_cfg_data[189]
  PIN b_cfg_data[18]
    DIRECTION OUTPUT ;
    USE SIGNAL ;
    PORT
      LAYER M4 ;
        RECT  69.036 35.088 69.12 35.112 ;
    END
  END b_cfg_data[18]
  PIN b_cfg_data[190]
    DIRECTION OUTPUT ;
    USE SIGNAL ;
    PORT
      LAYER M4 ;
        RECT  69.036 20.88 69.12 20.904 ;
    END
  END b_cfg_data[190]
  PIN b_cfg_data[191]
    DIRECTION OUTPUT ;
    USE SIGNAL ;
    PORT
      LAYER M4 ;
        RECT  69.036 20.976 69.12 21 ;
    END
  END b_cfg_data[191]
  PIN b_cfg_data[192]
    DIRECTION OUTPUT ;
    USE SIGNAL ;
    PORT
      LAYER M4 ;
        RECT  69.036 21.072 69.12 21.096 ;
    END
  END b_cfg_data[192]
  PIN b_cfg_data[193]
    DIRECTION OUTPUT ;
    USE SIGNAL ;
    PORT
      LAYER M4 ;
        RECT  69.036 21.168 69.12 21.192 ;
    END
  END b_cfg_data[193]
  PIN b_cfg_data[194]
    DIRECTION OUTPUT ;
    USE SIGNAL ;
    PORT
      LAYER M4 ;
        RECT  69.036 21.264 69.12 21.288 ;
    END
  END b_cfg_data[194]
  PIN b_cfg_data[195]
    DIRECTION OUTPUT ;
    USE SIGNAL ;
    PORT
      LAYER M4 ;
        RECT  69.036 21.36 69.12 21.384 ;
    END
  END b_cfg_data[195]
  PIN b_cfg_data[196]
    DIRECTION OUTPUT ;
    USE SIGNAL ;
    PORT
      LAYER M4 ;
        RECT  69.036 21.456 69.12 21.48 ;
    END
  END b_cfg_data[196]
  PIN b_cfg_data[197]
    DIRECTION OUTPUT ;
    USE SIGNAL ;
    PORT
      LAYER M4 ;
        RECT  69.036 21.552 69.12 21.576 ;
    END
  END b_cfg_data[197]
  PIN b_cfg_data[198]
    DIRECTION OUTPUT ;
    USE SIGNAL ;
    PORT
      LAYER M4 ;
        RECT  69.036 21.648 69.12 21.672 ;
    END
  END b_cfg_data[198]
  PIN b_cfg_data[199]
    DIRECTION OUTPUT ;
    USE SIGNAL ;
    PORT
      LAYER M4 ;
        RECT  69.036 21.744 69.12 21.768 ;
    END
  END b_cfg_data[199]
  PIN b_cfg_data[19]
    DIRECTION OUTPUT ;
    USE SIGNAL ;
    PORT
      LAYER M4 ;
        RECT  69.036 35.184 69.12 35.208 ;
    END
  END b_cfg_data[19]
  PIN b_cfg_data[1]
    DIRECTION OUTPUT ;
    USE SIGNAL ;
    PORT
      LAYER M4 ;
        RECT  69.036 33.456 69.12 33.48 ;
    END
  END b_cfg_data[1]
  PIN b_cfg_data[200]
    DIRECTION OUTPUT ;
    USE SIGNAL ;
    PORT
      LAYER M4 ;
        RECT  69.036 21.84 69.12 21.864 ;
    END
  END b_cfg_data[200]
  PIN b_cfg_data[201]
    DIRECTION OUTPUT ;
    USE SIGNAL ;
    PORT
      LAYER M4 ;
        RECT  69.036 21.936 69.12 21.96 ;
    END
  END b_cfg_data[201]
  PIN b_cfg_data[202]
    DIRECTION OUTPUT ;
    USE SIGNAL ;
    PORT
      LAYER M4 ;
        RECT  69.036 22.032 69.12 22.056 ;
    END
  END b_cfg_data[202]
  PIN b_cfg_data[203]
    DIRECTION OUTPUT ;
    USE SIGNAL ;
    PORT
      LAYER M4 ;
        RECT  69.036 22.128 69.12 22.152 ;
    END
  END b_cfg_data[203]
  PIN b_cfg_data[204]
    DIRECTION OUTPUT ;
    USE SIGNAL ;
    PORT
      LAYER M4 ;
        RECT  69.036 22.224 69.12 22.248 ;
    END
  END b_cfg_data[204]
  PIN b_cfg_data[205]
    DIRECTION OUTPUT ;
    USE SIGNAL ;
    PORT
      LAYER M4 ;
        RECT  69.036 22.32 69.12 22.344 ;
    END
  END b_cfg_data[205]
  PIN b_cfg_data[206]
    DIRECTION OUTPUT ;
    USE SIGNAL ;
    PORT
      LAYER M4 ;
        RECT  69.036 22.416 69.12 22.44 ;
    END
  END b_cfg_data[206]
  PIN b_cfg_data[207]
    DIRECTION OUTPUT ;
    USE SIGNAL ;
    PORT
      LAYER M4 ;
        RECT  69.036 22.512 69.12 22.536 ;
    END
  END b_cfg_data[207]
  PIN b_cfg_data[208]
    DIRECTION OUTPUT ;
    USE SIGNAL ;
    PORT
      LAYER M4 ;
        RECT  69.036 22.608 69.12 22.632 ;
    END
  END b_cfg_data[208]
  PIN b_cfg_data[209]
    DIRECTION OUTPUT ;
    USE SIGNAL ;
    PORT
      LAYER M4 ;
        RECT  69.036 22.704 69.12 22.728 ;
    END
  END b_cfg_data[209]
  PIN b_cfg_data[20]
    DIRECTION OUTPUT ;
    USE SIGNAL ;
    PORT
      LAYER M4 ;
        RECT  69.036 29.136 69.12 29.16 ;
    END
  END b_cfg_data[20]
  PIN b_cfg_data[210]
    DIRECTION OUTPUT ;
    USE SIGNAL ;
    PORT
      LAYER M4 ;
        RECT  69.036 22.8 69.12 22.824 ;
    END
  END b_cfg_data[210]
  PIN b_cfg_data[211]
    DIRECTION OUTPUT ;
    USE SIGNAL ;
    PORT
      LAYER M4 ;
        RECT  69.036 22.896 69.12 22.92 ;
    END
  END b_cfg_data[211]
  PIN b_cfg_data[212]
    DIRECTION OUTPUT ;
    USE SIGNAL ;
    PORT
      LAYER M4 ;
        RECT  69.036 42.192 69.12 42.216 ;
    END
  END b_cfg_data[212]
  PIN b_cfg_data[213]
    DIRECTION OUTPUT ;
    USE SIGNAL ;
    PORT
      LAYER M4 ;
        RECT  69.036 42.288 69.12 42.312 ;
    END
  END b_cfg_data[213]
  PIN b_cfg_data[214]
    DIRECTION OUTPUT ;
    USE SIGNAL ;
    PORT
      LAYER M4 ;
        RECT  69.036 42.384 69.12 42.408 ;
    END
  END b_cfg_data[214]
  PIN b_cfg_data[215]
    DIRECTION OUTPUT ;
    USE SIGNAL ;
    PORT
      LAYER M4 ;
        RECT  69.036 42.48 69.12 42.504 ;
    END
  END b_cfg_data[215]
  PIN b_cfg_data[216]
    DIRECTION OUTPUT ;
    USE SIGNAL ;
    PORT
      LAYER M4 ;
        RECT  69.036 42.576 69.12 42.6 ;
    END
  END b_cfg_data[216]
  PIN b_cfg_data[217]
    DIRECTION OUTPUT ;
    USE SIGNAL ;
    PORT
      LAYER M4 ;
        RECT  69.036 42.672 69.12 42.696 ;
    END
  END b_cfg_data[217]
  PIN b_cfg_data[218]
    DIRECTION OUTPUT ;
    USE SIGNAL ;
    PORT
      LAYER M4 ;
        RECT  69.036 42.768 69.12 42.792 ;
    END
  END b_cfg_data[218]
  PIN b_cfg_data[219]
    DIRECTION OUTPUT ;
    USE SIGNAL ;
    PORT
      LAYER M4 ;
        RECT  69.036 42.864 69.12 42.888 ;
    END
  END b_cfg_data[219]
  PIN b_cfg_data[21]
    DIRECTION OUTPUT ;
    USE SIGNAL ;
    PORT
      LAYER M4 ;
        RECT  69.036 29.232 69.12 29.256 ;
    END
  END b_cfg_data[21]
  PIN b_cfg_data[220]
    DIRECTION OUTPUT ;
    USE SIGNAL ;
    PORT
      LAYER M4 ;
        RECT  69.036 42.96 69.12 42.984 ;
    END
  END b_cfg_data[220]
  PIN b_cfg_data[221]
    DIRECTION OUTPUT ;
    USE SIGNAL ;
    PORT
      LAYER M4 ;
        RECT  69.036 43.056 69.12 43.08 ;
    END
  END b_cfg_data[221]
  PIN b_cfg_data[222]
    DIRECTION OUTPUT ;
    USE SIGNAL ;
    PORT
      LAYER M4 ;
        RECT  69.036 43.152 69.12 43.176 ;
    END
  END b_cfg_data[222]
  PIN b_cfg_data[223]
    DIRECTION OUTPUT ;
    USE SIGNAL ;
    PORT
      LAYER M4 ;
        RECT  69.036 43.248 69.12 43.272 ;
    END
  END b_cfg_data[223]
  PIN b_cfg_data[224]
    DIRECTION OUTPUT ;
    USE SIGNAL ;
    PORT
      LAYER M4 ;
        RECT  69.036 43.344 69.12 43.368 ;
    END
  END b_cfg_data[224]
  PIN b_cfg_data[225]
    DIRECTION OUTPUT ;
    USE SIGNAL ;
    PORT
      LAYER M4 ;
        RECT  69.036 43.44 69.12 43.464 ;
    END
  END b_cfg_data[225]
  PIN b_cfg_data[226]
    DIRECTION OUTPUT ;
    USE SIGNAL ;
    PORT
      LAYER M4 ;
        RECT  69.036 43.536 69.12 43.56 ;
    END
  END b_cfg_data[226]
  PIN b_cfg_data[227]
    DIRECTION OUTPUT ;
    USE SIGNAL ;
    PORT
      LAYER M4 ;
        RECT  69.036 43.632 69.12 43.656 ;
    END
  END b_cfg_data[227]
  PIN b_cfg_data[228]
    DIRECTION OUTPUT ;
    USE SIGNAL ;
    PORT
      LAYER M4 ;
        RECT  69.036 43.728 69.12 43.752 ;
    END
  END b_cfg_data[228]
  PIN b_cfg_data[229]
    DIRECTION OUTPUT ;
    USE SIGNAL ;
    PORT
      LAYER M4 ;
        RECT  69.036 43.824 69.12 43.848 ;
    END
  END b_cfg_data[229]
  PIN b_cfg_data[22]
    DIRECTION OUTPUT ;
    USE SIGNAL ;
    PORT
      LAYER M4 ;
        RECT  69.036 29.328 69.12 29.352 ;
    END
  END b_cfg_data[22]
  PIN b_cfg_data[230]
    DIRECTION OUTPUT ;
    USE SIGNAL ;
    PORT
      LAYER M4 ;
        RECT  69.036 43.92 69.12 43.944 ;
    END
  END b_cfg_data[230]
  PIN b_cfg_data[231]
    DIRECTION OUTPUT ;
    USE SIGNAL ;
    PORT
      LAYER M4 ;
        RECT  69.036 44.016 69.12 44.04 ;
    END
  END b_cfg_data[231]
  PIN b_cfg_data[232]
    DIRECTION OUTPUT ;
    USE SIGNAL ;
    PORT
      LAYER M4 ;
        RECT  69.036 44.112 69.12 44.136 ;
    END
  END b_cfg_data[232]
  PIN b_cfg_data[233]
    DIRECTION OUTPUT ;
    USE SIGNAL ;
    PORT
      LAYER M4 ;
        RECT  69.036 44.208 69.12 44.232 ;
    END
  END b_cfg_data[233]
  PIN b_cfg_data[234]
    DIRECTION OUTPUT ;
    USE SIGNAL ;
    PORT
      LAYER M4 ;
        RECT  69.036 44.304 69.12 44.328 ;
    END
  END b_cfg_data[234]
  PIN b_cfg_data[235]
    DIRECTION OUTPUT ;
    USE SIGNAL ;
    PORT
      LAYER M4 ;
        RECT  69.036 44.4 69.12 44.424 ;
    END
  END b_cfg_data[235]
  PIN b_cfg_data[236]
    DIRECTION OUTPUT ;
    USE SIGNAL ;
    PORT
      LAYER M4 ;
        RECT  69.036 44.496 69.12 44.52 ;
    END
  END b_cfg_data[236]
  PIN b_cfg_data[237]
    DIRECTION OUTPUT ;
    USE SIGNAL ;
    PORT
      LAYER M4 ;
        RECT  69.036 44.592 69.12 44.616 ;
    END
  END b_cfg_data[237]
  PIN b_cfg_data[238]
    DIRECTION OUTPUT ;
    USE SIGNAL ;
    PORT
      LAYER M4 ;
        RECT  69.036 44.688 69.12 44.712 ;
    END
  END b_cfg_data[238]
  PIN b_cfg_data[239]
    DIRECTION OUTPUT ;
    USE SIGNAL ;
    PORT
      LAYER M4 ;
        RECT  69.036 44.784 69.12 44.808 ;
    END
  END b_cfg_data[239]
  PIN b_cfg_data[23]
    DIRECTION OUTPUT ;
    USE SIGNAL ;
    PORT
      LAYER M4 ;
        RECT  69.036 29.424 69.12 29.448 ;
    END
  END b_cfg_data[23]
  PIN b_cfg_data[240]
    DIRECTION OUTPUT ;
    USE SIGNAL ;
    PORT
      LAYER M4 ;
        RECT  69.036 44.88 69.12 44.904 ;
    END
  END b_cfg_data[240]
  PIN b_cfg_data[241]
    DIRECTION OUTPUT ;
    USE SIGNAL ;
    PORT
      LAYER M4 ;
        RECT  69.036 44.976 69.12 45 ;
    END
  END b_cfg_data[241]
  PIN b_cfg_data[242]
    DIRECTION OUTPUT ;
    USE SIGNAL ;
    PORT
      LAYER M4 ;
        RECT  69.036 45.072 69.12 45.096 ;
    END
  END b_cfg_data[242]
  PIN b_cfg_data[243]
    DIRECTION OUTPUT ;
    USE SIGNAL ;
    PORT
      LAYER M4 ;
        RECT  69.036 45.168 69.12 45.192 ;
    END
  END b_cfg_data[243]
  PIN b_cfg_data[244]
    DIRECTION OUTPUT ;
    USE SIGNAL ;
    PORT
      LAYER M4 ;
        RECT  69.036 45.264 69.12 45.288 ;
    END
  END b_cfg_data[244]
  PIN b_cfg_data[245]
    DIRECTION OUTPUT ;
    USE SIGNAL ;
    PORT
      LAYER M4 ;
        RECT  69.036 45.36 69.12 45.384 ;
    END
  END b_cfg_data[245]
  PIN b_cfg_data[246]
    DIRECTION OUTPUT ;
    USE SIGNAL ;
    PORT
      LAYER M4 ;
        RECT  69.036 45.456 69.12 45.48 ;
    END
  END b_cfg_data[246]
  PIN b_cfg_data[247]
    DIRECTION OUTPUT ;
    USE SIGNAL ;
    PORT
      LAYER M4 ;
        RECT  69.036 45.552 69.12 45.576 ;
    END
  END b_cfg_data[247]
  PIN b_cfg_data[248]
    DIRECTION OUTPUT ;
    USE SIGNAL ;
    PORT
      LAYER M4 ;
        RECT  69.036 45.648 69.12 45.672 ;
    END
  END b_cfg_data[248]
  PIN b_cfg_data[249]
    DIRECTION OUTPUT ;
    USE SIGNAL ;
    PORT
      LAYER M4 ;
        RECT  69.036 45.744 69.12 45.768 ;
    END
  END b_cfg_data[249]
  PIN b_cfg_data[24]
    DIRECTION OUTPUT ;
    USE SIGNAL ;
    PORT
      LAYER M4 ;
        RECT  69.036 29.52 69.12 29.544 ;
    END
  END b_cfg_data[24]
  PIN b_cfg_data[250]
    DIRECTION OUTPUT ;
    USE SIGNAL ;
    PORT
      LAYER M4 ;
        RECT  69.036 45.84 69.12 45.864 ;
    END
  END b_cfg_data[250]
  PIN b_cfg_data[251]
    DIRECTION OUTPUT ;
    USE SIGNAL ;
    PORT
      LAYER M4 ;
        RECT  69.036 45.936 69.12 45.96 ;
    END
  END b_cfg_data[251]
  PIN b_cfg_data[252]
    DIRECTION OUTPUT ;
    USE SIGNAL ;
    PORT
      LAYER M4 ;
        RECT  69.036 46.032 69.12 46.056 ;
    END
  END b_cfg_data[252]
  PIN b_cfg_data[253]
    DIRECTION OUTPUT ;
    USE SIGNAL ;
    PORT
      LAYER M4 ;
        RECT  69.036 46.128 69.12 46.152 ;
    END
  END b_cfg_data[253]
  PIN b_cfg_data[254]
    DIRECTION OUTPUT ;
    USE SIGNAL ;
    PORT
      LAYER M4 ;
        RECT  69.036 46.224 69.12 46.248 ;
    END
  END b_cfg_data[254]
  PIN b_cfg_data[255]
    DIRECTION OUTPUT ;
    USE SIGNAL ;
    PORT
      LAYER M4 ;
        RECT  69.036 46.32 69.12 46.344 ;
    END
  END b_cfg_data[255]
  PIN b_cfg_data[25]
    DIRECTION OUTPUT ;
    USE SIGNAL ;
    PORT
      LAYER M4 ;
        RECT  69.036 29.616 69.12 29.64 ;
    END
  END b_cfg_data[25]
  PIN b_cfg_data[26]
    DIRECTION OUTPUT ;
    USE SIGNAL ;
    PORT
      LAYER M4 ;
        RECT  69.036 29.712 69.12 29.736 ;
    END
  END b_cfg_data[26]
  PIN b_cfg_data[27]
    DIRECTION OUTPUT ;
    USE SIGNAL ;
    PORT
      LAYER M4 ;
        RECT  69.036 29.808 69.12 29.832 ;
    END
  END b_cfg_data[27]
  PIN b_cfg_data[28]
    DIRECTION OUTPUT ;
    USE SIGNAL ;
    PORT
      LAYER M4 ;
        RECT  69.036 29.904 69.12 29.928 ;
    END
  END b_cfg_data[28]
  PIN b_cfg_data[29]
    DIRECTION OUTPUT ;
    USE SIGNAL ;
    PORT
      LAYER M4 ;
        RECT  69.036 30 69.12 30.024 ;
    END
  END b_cfg_data[29]
  PIN b_cfg_data[2]
    DIRECTION OUTPUT ;
    USE SIGNAL ;
    PORT
      LAYER M4 ;
        RECT  69.036 33.552 69.12 33.576 ;
    END
  END b_cfg_data[2]
  PIN b_cfg_data[30]
    DIRECTION OUTPUT ;
    USE SIGNAL ;
    PORT
      LAYER M4 ;
        RECT  69.036 30.096 69.12 30.12 ;
    END
  END b_cfg_data[30]
  PIN b_cfg_data[31]
    DIRECTION OUTPUT ;
    USE SIGNAL ;
    PORT
      LAYER M4 ;
        RECT  69.036 30.192 69.12 30.216 ;
    END
  END b_cfg_data[31]
  PIN b_cfg_data[32]
    DIRECTION OUTPUT ;
    USE SIGNAL ;
    PORT
      LAYER M4 ;
        RECT  69.036 30.288 69.12 30.312 ;
    END
  END b_cfg_data[32]
  PIN b_cfg_data[33]
    DIRECTION OUTPUT ;
    USE SIGNAL ;
    PORT
      LAYER M4 ;
        RECT  69.036 30.384 69.12 30.408 ;
    END
  END b_cfg_data[33]
  PIN b_cfg_data[34]
    DIRECTION OUTPUT ;
    USE SIGNAL ;
    PORT
      LAYER M4 ;
        RECT  69.036 30.48 69.12 30.504 ;
    END
  END b_cfg_data[34]
  PIN b_cfg_data[35]
    DIRECTION OUTPUT ;
    USE SIGNAL ;
    PORT
      LAYER M4 ;
        RECT  69.036 30.576 69.12 30.6 ;
    END
  END b_cfg_data[35]
  PIN b_cfg_data[36]
    DIRECTION OUTPUT ;
    USE SIGNAL ;
    PORT
      LAYER M4 ;
        RECT  69.036 30.672 69.12 30.696 ;
    END
  END b_cfg_data[36]
  PIN b_cfg_data[37]
    DIRECTION OUTPUT ;
    USE SIGNAL ;
    PORT
      LAYER M4 ;
        RECT  69.036 30.768 69.12 30.792 ;
    END
  END b_cfg_data[37]
  PIN b_cfg_data[38]
    DIRECTION OUTPUT ;
    USE SIGNAL ;
    PORT
      LAYER M4 ;
        RECT  69.036 30.864 69.12 30.888 ;
    END
  END b_cfg_data[38]
  PIN b_cfg_data[39]
    DIRECTION OUTPUT ;
    USE SIGNAL ;
    PORT
      LAYER M4 ;
        RECT  69.036 30.96 69.12 30.984 ;
    END
  END b_cfg_data[39]
  PIN b_cfg_data[3]
    DIRECTION OUTPUT ;
    USE SIGNAL ;
    PORT
      LAYER M4 ;
        RECT  69.036 33.648 69.12 33.672 ;
    END
  END b_cfg_data[3]
  PIN b_cfg_data[40]
    DIRECTION OUTPUT ;
    USE SIGNAL ;
    PORT
      LAYER M4 ;
        RECT  69.036 31.056 69.12 31.08 ;
    END
  END b_cfg_data[40]
  PIN b_cfg_data[41]
    DIRECTION OUTPUT ;
    USE SIGNAL ;
    PORT
      LAYER M4 ;
        RECT  69.036 31.152 69.12 31.176 ;
    END
  END b_cfg_data[41]
  PIN b_cfg_data[42]
    DIRECTION OUTPUT ;
    USE SIGNAL ;
    PORT
      LAYER M4 ;
        RECT  69.036 31.248 69.12 31.272 ;
    END
  END b_cfg_data[42]
  PIN b_cfg_data[43]
    DIRECTION OUTPUT ;
    USE SIGNAL ;
    PORT
      LAYER M4 ;
        RECT  69.036 31.344 69.12 31.368 ;
    END
  END b_cfg_data[43]
  PIN b_cfg_data[44]
    DIRECTION OUTPUT ;
    USE SIGNAL ;
    PORT
      LAYER M4 ;
        RECT  69.036 31.44 69.12 31.464 ;
    END
  END b_cfg_data[44]
  PIN b_cfg_data[45]
    DIRECTION OUTPUT ;
    USE SIGNAL ;
    PORT
      LAYER M4 ;
        RECT  69.036 31.536 69.12 31.56 ;
    END
  END b_cfg_data[45]
  PIN b_cfg_data[46]
    DIRECTION OUTPUT ;
    USE SIGNAL ;
    PORT
      LAYER M4 ;
        RECT  69.036 31.632 69.12 31.656 ;
    END
  END b_cfg_data[46]
  PIN b_cfg_data[47]
    DIRECTION OUTPUT ;
    USE SIGNAL ;
    PORT
      LAYER M4 ;
        RECT  69.036 31.728 69.12 31.752 ;
    END
  END b_cfg_data[47]
  PIN b_cfg_data[48]
    DIRECTION OUTPUT ;
    USE SIGNAL ;
    PORT
      LAYER M4 ;
        RECT  69.036 31.824 69.12 31.848 ;
    END
  END b_cfg_data[48]
  PIN b_cfg_data[49]
    DIRECTION OUTPUT ;
    USE SIGNAL ;
    PORT
      LAYER M4 ;
        RECT  69.036 31.92 69.12 31.944 ;
    END
  END b_cfg_data[49]
  PIN b_cfg_data[4]
    DIRECTION OUTPUT ;
    USE SIGNAL ;
    PORT
      LAYER M4 ;
        RECT  69.036 33.744 69.12 33.768 ;
    END
  END b_cfg_data[4]
  PIN b_cfg_data[50]
    DIRECTION OUTPUT ;
    USE SIGNAL ;
    PORT
      LAYER M4 ;
        RECT  69.036 32.016 69.12 32.04 ;
    END
  END b_cfg_data[50]
  PIN b_cfg_data[51]
    DIRECTION OUTPUT ;
    USE SIGNAL ;
    PORT
      LAYER M4 ;
        RECT  69.036 32.112 69.12 32.136 ;
    END
  END b_cfg_data[51]
  PIN b_cfg_data[52]
    DIRECTION OUTPUT ;
    USE SIGNAL ;
    PORT
      LAYER M4 ;
        RECT  69.036 26.064 69.12 26.088 ;
    END
  END b_cfg_data[52]
  PIN b_cfg_data[53]
    DIRECTION OUTPUT ;
    USE SIGNAL ;
    PORT
      LAYER M4 ;
        RECT  69.036 26.16 69.12 26.184 ;
    END
  END b_cfg_data[53]
  PIN b_cfg_data[54]
    DIRECTION OUTPUT ;
    USE SIGNAL ;
    PORT
      LAYER M4 ;
        RECT  69.036 26.256 69.12 26.28 ;
    END
  END b_cfg_data[54]
  PIN b_cfg_data[55]
    DIRECTION OUTPUT ;
    USE SIGNAL ;
    PORT
      LAYER M4 ;
        RECT  69.036 26.352 69.12 26.376 ;
    END
  END b_cfg_data[55]
  PIN b_cfg_data[56]
    DIRECTION OUTPUT ;
    USE SIGNAL ;
    PORT
      LAYER M4 ;
        RECT  69.036 26.448 69.12 26.472 ;
    END
  END b_cfg_data[56]
  PIN b_cfg_data[57]
    DIRECTION OUTPUT ;
    USE SIGNAL ;
    PORT
      LAYER M4 ;
        RECT  69.036 26.544 69.12 26.568 ;
    END
  END b_cfg_data[57]
  PIN b_cfg_data[58]
    DIRECTION OUTPUT ;
    USE SIGNAL ;
    PORT
      LAYER M4 ;
        RECT  69.036 26.64 69.12 26.664 ;
    END
  END b_cfg_data[58]
  PIN b_cfg_data[59]
    DIRECTION OUTPUT ;
    USE SIGNAL ;
    PORT
      LAYER M4 ;
        RECT  69.036 26.736 69.12 26.76 ;
    END
  END b_cfg_data[59]
  PIN b_cfg_data[5]
    DIRECTION OUTPUT ;
    USE SIGNAL ;
    PORT
      LAYER M4 ;
        RECT  69.036 33.84 69.12 33.864 ;
    END
  END b_cfg_data[5]
  PIN b_cfg_data[60]
    DIRECTION OUTPUT ;
    USE SIGNAL ;
    PORT
      LAYER M4 ;
        RECT  69.036 26.832 69.12 26.856 ;
    END
  END b_cfg_data[60]
  PIN b_cfg_data[61]
    DIRECTION OUTPUT ;
    USE SIGNAL ;
    PORT
      LAYER M4 ;
        RECT  69.036 26.928 69.12 26.952 ;
    END
  END b_cfg_data[61]
  PIN b_cfg_data[62]
    DIRECTION OUTPUT ;
    USE SIGNAL ;
    PORT
      LAYER M4 ;
        RECT  69.036 27.024 69.12 27.048 ;
    END
  END b_cfg_data[62]
  PIN b_cfg_data[63]
    DIRECTION OUTPUT ;
    USE SIGNAL ;
    PORT
      LAYER M4 ;
        RECT  69.036 27.12 69.12 27.144 ;
    END
  END b_cfg_data[63]
  PIN b_cfg_data[64]
    DIRECTION OUTPUT ;
    USE SIGNAL ;
    PORT
      LAYER M4 ;
        RECT  69.036 27.216 69.12 27.24 ;
    END
  END b_cfg_data[64]
  PIN b_cfg_data[65]
    DIRECTION OUTPUT ;
    USE SIGNAL ;
    PORT
      LAYER M4 ;
        RECT  69.036 27.312 69.12 27.336 ;
    END
  END b_cfg_data[65]
  PIN b_cfg_data[66]
    DIRECTION OUTPUT ;
    USE SIGNAL ;
    PORT
      LAYER M4 ;
        RECT  69.036 27.408 69.12 27.432 ;
    END
  END b_cfg_data[66]
  PIN b_cfg_data[67]
    DIRECTION OUTPUT ;
    USE SIGNAL ;
    PORT
      LAYER M4 ;
        RECT  69.036 27.504 69.12 27.528 ;
    END
  END b_cfg_data[67]
  PIN b_cfg_data[68]
    DIRECTION OUTPUT ;
    USE SIGNAL ;
    PORT
      LAYER M4 ;
        RECT  69.036 27.6 69.12 27.624 ;
    END
  END b_cfg_data[68]
  PIN b_cfg_data[69]
    DIRECTION OUTPUT ;
    USE SIGNAL ;
    PORT
      LAYER M4 ;
        RECT  69.036 27.696 69.12 27.72 ;
    END
  END b_cfg_data[69]
  PIN b_cfg_data[6]
    DIRECTION OUTPUT ;
    USE SIGNAL ;
    PORT
      LAYER M4 ;
        RECT  69.036 33.936 69.12 33.96 ;
    END
  END b_cfg_data[6]
  PIN b_cfg_data[70]
    DIRECTION OUTPUT ;
    USE SIGNAL ;
    PORT
      LAYER M4 ;
        RECT  69.036 27.792 69.12 27.816 ;
    END
  END b_cfg_data[70]
  PIN b_cfg_data[71]
    DIRECTION OUTPUT ;
    USE SIGNAL ;
    PORT
      LAYER M4 ;
        RECT  69.036 27.888 69.12 27.912 ;
    END
  END b_cfg_data[71]
  PIN b_cfg_data[72]
    DIRECTION OUTPUT ;
    USE SIGNAL ;
    PORT
      LAYER M4 ;
        RECT  69.036 27.984 69.12 28.008 ;
    END
  END b_cfg_data[72]
  PIN b_cfg_data[73]
    DIRECTION OUTPUT ;
    USE SIGNAL ;
    PORT
      LAYER M4 ;
        RECT  69.036 28.08 69.12 28.104 ;
    END
  END b_cfg_data[73]
  PIN b_cfg_data[74]
    DIRECTION OUTPUT ;
    USE SIGNAL ;
    PORT
      LAYER M4 ;
        RECT  69.036 28.176 69.12 28.2 ;
    END
  END b_cfg_data[74]
  PIN b_cfg_data[75]
    DIRECTION OUTPUT ;
    USE SIGNAL ;
    PORT
      LAYER M4 ;
        RECT  69.036 28.272 69.12 28.296 ;
    END
  END b_cfg_data[75]
  PIN b_cfg_data[76]
    DIRECTION OUTPUT ;
    USE SIGNAL ;
    PORT
      LAYER M4 ;
        RECT  69.036 28.368 69.12 28.392 ;
    END
  END b_cfg_data[76]
  PIN b_cfg_data[77]
    DIRECTION OUTPUT ;
    USE SIGNAL ;
    PORT
      LAYER M4 ;
        RECT  69.036 28.464 69.12 28.488 ;
    END
  END b_cfg_data[77]
  PIN b_cfg_data[78]
    DIRECTION OUTPUT ;
    USE SIGNAL ;
    PORT
      LAYER M4 ;
        RECT  69.036 28.56 69.12 28.584 ;
    END
  END b_cfg_data[78]
  PIN b_cfg_data[79]
    DIRECTION OUTPUT ;
    USE SIGNAL ;
    PORT
      LAYER M4 ;
        RECT  69.036 28.656 69.12 28.68 ;
    END
  END b_cfg_data[79]
  PIN b_cfg_data[7]
    DIRECTION OUTPUT ;
    USE SIGNAL ;
    PORT
      LAYER M4 ;
        RECT  69.036 34.032 69.12 34.056 ;
    END
  END b_cfg_data[7]
  PIN b_cfg_data[80]
    DIRECTION OUTPUT ;
    USE SIGNAL ;
    PORT
      LAYER M4 ;
        RECT  69.036 28.752 69.12 28.776 ;
    END
  END b_cfg_data[80]
  PIN b_cfg_data[81]
    DIRECTION OUTPUT ;
    USE SIGNAL ;
    PORT
      LAYER M4 ;
        RECT  69.036 28.848 69.12 28.872 ;
    END
  END b_cfg_data[81]
  PIN b_cfg_data[82]
    DIRECTION OUTPUT ;
    USE SIGNAL ;
    PORT
      LAYER M4 ;
        RECT  69.036 28.944 69.12 28.968 ;
    END
  END b_cfg_data[82]
  PIN b_cfg_data[83]
    DIRECTION OUTPUT ;
    USE SIGNAL ;
    PORT
      LAYER M4 ;
        RECT  69.036 29.04 69.12 29.064 ;
    END
  END b_cfg_data[83]
  PIN b_cfg_data[84]
    DIRECTION OUTPUT ;
    USE SIGNAL ;
    PORT
      LAYER M4 ;
        RECT  69.036 48.336 69.12 48.36 ;
    END
  END b_cfg_data[84]
  PIN b_cfg_data[85]
    DIRECTION OUTPUT ;
    USE SIGNAL ;
    PORT
      LAYER M4 ;
        RECT  69.036 48.432 69.12 48.456 ;
    END
  END b_cfg_data[85]
  PIN b_cfg_data[86]
    DIRECTION OUTPUT ;
    USE SIGNAL ;
    PORT
      LAYER M4 ;
        RECT  69.036 48.528 69.12 48.552 ;
    END
  END b_cfg_data[86]
  PIN b_cfg_data[87]
    DIRECTION OUTPUT ;
    USE SIGNAL ;
    PORT
      LAYER M4 ;
        RECT  69.036 48.624 69.12 48.648 ;
    END
  END b_cfg_data[87]
  PIN b_cfg_data[88]
    DIRECTION OUTPUT ;
    USE SIGNAL ;
    PORT
      LAYER M4 ;
        RECT  69.036 48.72 69.12 48.744 ;
    END
  END b_cfg_data[88]
  PIN b_cfg_data[89]
    DIRECTION OUTPUT ;
    USE SIGNAL ;
    PORT
      LAYER M4 ;
        RECT  69.036 48.816 69.12 48.84 ;
    END
  END b_cfg_data[89]
  PIN b_cfg_data[8]
    DIRECTION OUTPUT ;
    USE SIGNAL ;
    PORT
      LAYER M4 ;
        RECT  69.036 34.128 69.12 34.152 ;
    END
  END b_cfg_data[8]
  PIN b_cfg_data[90]
    DIRECTION OUTPUT ;
    USE SIGNAL ;
    PORT
      LAYER M4 ;
        RECT  69.036 48.912 69.12 48.936 ;
    END
  END b_cfg_data[90]
  PIN b_cfg_data[91]
    DIRECTION OUTPUT ;
    USE SIGNAL ;
    PORT
      LAYER M4 ;
        RECT  69.036 49.008 69.12 49.032 ;
    END
  END b_cfg_data[91]
  PIN b_cfg_data[92]
    DIRECTION OUTPUT ;
    USE SIGNAL ;
    PORT
      LAYER M4 ;
        RECT  69.036 49.104 69.12 49.128 ;
    END
  END b_cfg_data[92]
  PIN b_cfg_data[93]
    DIRECTION OUTPUT ;
    USE SIGNAL ;
    PORT
      LAYER M4 ;
        RECT  69.036 49.2 69.12 49.224 ;
    END
  END b_cfg_data[93]
  PIN b_cfg_data[94]
    DIRECTION OUTPUT ;
    USE SIGNAL ;
    PORT
      LAYER M4 ;
        RECT  69.036 49.296 69.12 49.32 ;
    END
  END b_cfg_data[94]
  PIN b_cfg_data[95]
    DIRECTION OUTPUT ;
    USE SIGNAL ;
    PORT
      LAYER M4 ;
        RECT  69.036 49.392 69.12 49.416 ;
    END
  END b_cfg_data[95]
  PIN b_cfg_data[96]
    DIRECTION OUTPUT ;
    USE SIGNAL ;
    PORT
      LAYER M4 ;
        RECT  69.036 49.488 69.12 49.512 ;
    END
  END b_cfg_data[96]
  PIN b_cfg_data[97]
    DIRECTION OUTPUT ;
    USE SIGNAL ;
    PORT
      LAYER M4 ;
        RECT  69.036 49.584 69.12 49.608 ;
    END
  END b_cfg_data[97]
  PIN b_cfg_data[98]
    DIRECTION OUTPUT ;
    USE SIGNAL ;
    PORT
      LAYER M4 ;
        RECT  69.036 49.68 69.12 49.704 ;
    END
  END b_cfg_data[98]
  PIN b_cfg_data[99]
    DIRECTION OUTPUT ;
    USE SIGNAL ;
    PORT
      LAYER M4 ;
        RECT  69.036 49.776 69.12 49.8 ;
    END
  END b_cfg_data[99]
  PIN b_cfg_data[9]
    DIRECTION OUTPUT ;
    USE SIGNAL ;
    PORT
      LAYER M4 ;
        RECT  69.036 34.224 69.12 34.248 ;
    END
  END b_cfg_data[9]
  PIN b_cfg_target[0]
    DIRECTION OUTPUT ;
    USE SIGNAL ;
    PORT
      LAYER M4 ;
        RECT  69.036 46.416 69.12 46.44 ;
    END
  END b_cfg_target[0]
  PIN b_cfg_target[1]
    DIRECTION OUTPUT ;
    USE SIGNAL ;
    PORT
      LAYER M4 ;
        RECT  69.036 46.512 69.12 46.536 ;
    END
  END b_cfg_target[1]
  PIN b_cfg_target[2]
    DIRECTION OUTPUT ;
    USE SIGNAL ;
    PORT
      LAYER M4 ;
        RECT  69.036 46.608 69.12 46.632 ;
    END
  END b_cfg_target[2]
  PIN b_cfg_target[3]
    DIRECTION OUTPUT ;
    USE SIGNAL ;
    PORT
      LAYER M4 ;
        RECT  69.036 46.704 69.12 46.728 ;
    END
  END b_cfg_target[3]
  PIN b_cfg_target[4]
    DIRECTION OUTPUT ;
    USE SIGNAL ;
    PORT
      LAYER M4 ;
        RECT  69.036 46.8 69.12 46.824 ;
    END
  END b_cfg_target[4]
  PIN b_cfg_target[5]
    DIRECTION OUTPUT ;
    USE SIGNAL ;
    PORT
      LAYER M4 ;
        RECT  69.036 46.896 69.12 46.92 ;
    END
  END b_cfg_target[5]
  PIN b_cfg_target[6]
    DIRECTION OUTPUT ;
    USE SIGNAL ;
    PORT
      LAYER M4 ;
        RECT  69.036 46.992 69.12 47.016 ;
    END
  END b_cfg_target[6]
  PIN b_cfg_target[7]
    DIRECTION OUTPUT ;
    USE SIGNAL ;
    PORT
      LAYER M4 ;
        RECT  69.036 47.088 69.12 47.112 ;
    END
  END b_cfg_target[7]
  PIN b_cfg_v
    DIRECTION OUTPUT ;
    USE SIGNAL ;
    PORT
      LAYER M4 ;
        RECT  69.036 47.184 69.12 47.208 ;
    END
  END b_cfg_v
  PIN b_desc_base[0]
    DIRECTION OUTPUT ;
    USE SIGNAL ;
    PORT
      LAYER M4 ;
        RECT  69.036 47.28 69.12 47.304 ;
    END
  END b_desc_base[0]
  PIN b_desc_base[10]
    DIRECTION OUTPUT ;
    USE SIGNAL ;
    PORT
      LAYER M4 ;
        RECT  69.036 48.24 69.12 48.264 ;
    END
  END b_desc_base[10]
  PIN b_desc_base[11]
    DIRECTION OUTPUT ;
    USE SIGNAL ;
    PORT
      LAYER M4 ;
        RECT  69.036 39.12 69.12 39.144 ;
    END
  END b_desc_base[11]
  PIN b_desc_base[1]
    DIRECTION OUTPUT ;
    USE SIGNAL ;
    PORT
      LAYER M4 ;
        RECT  69.036 47.376 69.12 47.4 ;
    END
  END b_desc_base[1]
  PIN b_desc_base[2]
    DIRECTION OUTPUT ;
    USE SIGNAL ;
    PORT
      LAYER M4 ;
        RECT  69.036 47.472 69.12 47.496 ;
    END
  END b_desc_base[2]
  PIN b_desc_base[3]
    DIRECTION OUTPUT ;
    USE SIGNAL ;
    PORT
      LAYER M4 ;
        RECT  69.036 47.568 69.12 47.592 ;
    END
  END b_desc_base[3]
  PIN b_desc_base[4]
    DIRECTION OUTPUT ;
    USE SIGNAL ;
    PORT
      LAYER M4 ;
        RECT  69.036 47.664 69.12 47.688 ;
    END
  END b_desc_base[4]
  PIN b_desc_base[5]
    DIRECTION OUTPUT ;
    USE SIGNAL ;
    PORT
      LAYER M4 ;
        RECT  69.036 47.76 69.12 47.784 ;
    END
  END b_desc_base[5]
  PIN b_desc_base[6]
    DIRECTION OUTPUT ;
    USE SIGNAL ;
    PORT
      LAYER M4 ;
        RECT  69.036 47.856 69.12 47.88 ;
    END
  END b_desc_base[6]
  PIN b_desc_base[7]
    DIRECTION OUTPUT ;
    USE SIGNAL ;
    PORT
      LAYER M4 ;
        RECT  69.036 47.952 69.12 47.976 ;
    END
  END b_desc_base[7]
  PIN b_desc_base[8]
    DIRECTION OUTPUT ;
    USE SIGNAL ;
    PORT
      LAYER M4 ;
        RECT  69.036 48.048 69.12 48.072 ;
    END
  END b_desc_base[8]
  PIN b_desc_base[9]
    DIRECTION OUTPUT ;
    USE SIGNAL ;
    PORT
      LAYER M4 ;
        RECT  69.036 48.144 69.12 48.168 ;
    END
  END b_desc_base[9]
  PIN b_desc_limit[0]
    DIRECTION OUTPUT ;
    USE SIGNAL ;
    PORT
      LAYER M4 ;
        RECT  69.036 39.216 69.12 39.24 ;
    END
  END b_desc_limit[0]
  PIN b_desc_limit[10]
    DIRECTION OUTPUT ;
    USE SIGNAL ;
    PORT
      LAYER M4 ;
        RECT  69.036 40.176 69.12 40.2 ;
    END
  END b_desc_limit[10]
  PIN b_desc_limit[11]
    DIRECTION OUTPUT ;
    USE SIGNAL ;
    PORT
      LAYER M4 ;
        RECT  69.036 40.272 69.12 40.296 ;
    END
  END b_desc_limit[11]
  PIN b_desc_limit[12]
    DIRECTION OUTPUT ;
    USE SIGNAL ;
    PORT
      LAYER M4 ;
        RECT  69.036 40.368 69.12 40.392 ;
    END
  END b_desc_limit[12]
  PIN b_desc_limit[1]
    DIRECTION OUTPUT ;
    USE SIGNAL ;
    PORT
      LAYER M4 ;
        RECT  69.036 39.312 69.12 39.336 ;
    END
  END b_desc_limit[1]
  PIN b_desc_limit[2]
    DIRECTION OUTPUT ;
    USE SIGNAL ;
    PORT
      LAYER M4 ;
        RECT  69.036 39.408 69.12 39.432 ;
    END
  END b_desc_limit[2]
  PIN b_desc_limit[3]
    DIRECTION OUTPUT ;
    USE SIGNAL ;
    PORT
      LAYER M4 ;
        RECT  69.036 39.504 69.12 39.528 ;
    END
  END b_desc_limit[3]
  PIN b_desc_limit[4]
    DIRECTION OUTPUT ;
    USE SIGNAL ;
    PORT
      LAYER M4 ;
        RECT  69.036 39.6 69.12 39.624 ;
    END
  END b_desc_limit[4]
  PIN b_desc_limit[5]
    DIRECTION OUTPUT ;
    USE SIGNAL ;
    PORT
      LAYER M4 ;
        RECT  69.036 39.696 69.12 39.72 ;
    END
  END b_desc_limit[5]
  PIN b_desc_limit[6]
    DIRECTION OUTPUT ;
    USE SIGNAL ;
    PORT
      LAYER M4 ;
        RECT  69.036 39.792 69.12 39.816 ;
    END
  END b_desc_limit[6]
  PIN b_desc_limit[7]
    DIRECTION OUTPUT ;
    USE SIGNAL ;
    PORT
      LAYER M4 ;
        RECT  69.036 39.888 69.12 39.912 ;
    END
  END b_desc_limit[7]
  PIN b_desc_limit[8]
    DIRECTION OUTPUT ;
    USE SIGNAL ;
    PORT
      LAYER M4 ;
        RECT  69.036 39.984 69.12 40.008 ;
    END
  END b_desc_limit[8]
  PIN b_desc_limit[9]
    DIRECTION OUTPUT ;
    USE SIGNAL ;
    PORT
      LAYER M4 ;
        RECT  69.036 40.08 69.12 40.104 ;
    END
  END b_desc_limit[9]
  PIN b_desc_loops[0]
    DIRECTION OUTPUT ;
    USE SIGNAL ;
    PORT
      LAYER M4 ;
        RECT  69.036 40.464 69.12 40.488 ;
    END
  END b_desc_loops[0]
  PIN b_desc_loops[10]
    DIRECTION OUTPUT ;
    USE SIGNAL ;
    PORT
      LAYER M4 ;
        RECT  69.036 41.424 69.12 41.448 ;
    END
  END b_desc_loops[10]
  PIN b_desc_loops[11]
    DIRECTION OUTPUT ;
    USE SIGNAL ;
    PORT
      LAYER M4 ;
        RECT  69.036 41.52 69.12 41.544 ;
    END
  END b_desc_loops[11]
  PIN b_desc_loops[12]
    DIRECTION OUTPUT ;
    USE SIGNAL ;
    PORT
      LAYER M4 ;
        RECT  69.036 41.616 69.12 41.64 ;
    END
  END b_desc_loops[12]
  PIN b_desc_loops[13]
    DIRECTION OUTPUT ;
    USE SIGNAL ;
    PORT
      LAYER M4 ;
        RECT  69.036 41.712 69.12 41.736 ;
    END
  END b_desc_loops[13]
  PIN b_desc_loops[14]
    DIRECTION OUTPUT ;
    USE SIGNAL ;
    PORT
      LAYER M4 ;
        RECT  69.036 41.808 69.12 41.832 ;
    END
  END b_desc_loops[14]
  PIN b_desc_loops[15]
    DIRECTION OUTPUT ;
    USE SIGNAL ;
    PORT
      LAYER M4 ;
        RECT  69.036 41.904 69.12 41.928 ;
    END
  END b_desc_loops[15]
  PIN b_desc_loops[1]
    DIRECTION OUTPUT ;
    USE SIGNAL ;
    PORT
      LAYER M4 ;
        RECT  69.036 40.56 69.12 40.584 ;
    END
  END b_desc_loops[1]
  PIN b_desc_loops[2]
    DIRECTION OUTPUT ;
    USE SIGNAL ;
    PORT
      LAYER M4 ;
        RECT  69.036 40.656 69.12 40.68 ;
    END
  END b_desc_loops[2]
  PIN b_desc_loops[3]
    DIRECTION OUTPUT ;
    USE SIGNAL ;
    PORT
      LAYER M4 ;
        RECT  69.036 40.752 69.12 40.776 ;
    END
  END b_desc_loops[3]
  PIN b_desc_loops[4]
    DIRECTION OUTPUT ;
    USE SIGNAL ;
    PORT
      LAYER M4 ;
        RECT  69.036 40.848 69.12 40.872 ;
    END
  END b_desc_loops[4]
  PIN b_desc_loops[5]
    DIRECTION OUTPUT ;
    USE SIGNAL ;
    PORT
      LAYER M4 ;
        RECT  69.036 40.944 69.12 40.968 ;
    END
  END b_desc_loops[5]
  PIN b_desc_loops[6]
    DIRECTION OUTPUT ;
    USE SIGNAL ;
    PORT
      LAYER M4 ;
        RECT  69.036 41.04 69.12 41.064 ;
    END
  END b_desc_loops[6]
  PIN b_desc_loops[7]
    DIRECTION OUTPUT ;
    USE SIGNAL ;
    PORT
      LAYER M4 ;
        RECT  69.036 41.136 69.12 41.16 ;
    END
  END b_desc_loops[7]
  PIN b_desc_loops[8]
    DIRECTION OUTPUT ;
    USE SIGNAL ;
    PORT
      LAYER M4 ;
        RECT  69.036 41.232 69.12 41.256 ;
    END
  END b_desc_loops[8]
  PIN b_desc_loops[9]
    DIRECTION OUTPUT ;
    USE SIGNAL ;
    PORT
      LAYER M4 ;
        RECT  69.036 41.328 69.12 41.352 ;
    END
  END b_desc_loops[9]
  PIN b_desc_v
    DIRECTION OUTPUT ;
    USE SIGNAL ;
    PORT
      LAYER M4 ;
        RECT  69.036 42 69.12 42.024 ;
    END
  END b_desc_v
  PIN b_launch_v
    DIRECTION OUTPUT ;
    USE SIGNAL ;
    PORT
      LAYER M4 ;
        RECT  69.036 42.096 69.12 42.12 ;
    END
  END b_launch_v
  PIN cfg_addr[0]
    DIRECTION INPUT ;
    USE SIGNAL ;
    PORT
      LAYER M5 ;
        RECT  43.056 69.036 43.08 69.12 ;
    END
  END cfg_addr[0]
  PIN cfg_addr[10]
    DIRECTION INPUT ;
    USE SIGNAL ;
    PORT
      LAYER M5 ;
        RECT  44.016 69.036 44.04 69.12 ;
    END
  END cfg_addr[10]
  PIN cfg_addr[11]
    DIRECTION INPUT ;
    USE SIGNAL ;
    PORT
      LAYER M5 ;
        RECT  44.112 69.036 44.136 69.12 ;
    END
  END cfg_addr[11]
  PIN cfg_addr[1]
    DIRECTION INPUT ;
    USE SIGNAL ;
    PORT
      LAYER M5 ;
        RECT  43.152 69.036 43.176 69.12 ;
    END
  END cfg_addr[1]
  PIN cfg_addr[2]
    DIRECTION INPUT ;
    USE SIGNAL ;
    PORT
      LAYER M5 ;
        RECT  43.248 69.036 43.272 69.12 ;
    END
  END cfg_addr[2]
  PIN cfg_addr[3]
    DIRECTION INPUT ;
    USE SIGNAL ;
    PORT
      LAYER M5 ;
        RECT  43.344 69.036 43.368 69.12 ;
    END
  END cfg_addr[3]
  PIN cfg_addr[4]
    DIRECTION INPUT ;
    USE SIGNAL ;
    PORT
      LAYER M5 ;
        RECT  43.44 69.036 43.464 69.12 ;
    END
  END cfg_addr[4]
  PIN cfg_addr[5]
    DIRECTION INPUT ;
    USE SIGNAL ;
    PORT
      LAYER M5 ;
        RECT  43.536 69.036 43.56 69.12 ;
    END
  END cfg_addr[5]
  PIN cfg_addr[6]
    DIRECTION INPUT ;
    USE SIGNAL ;
    PORT
      LAYER M5 ;
        RECT  43.632 69.036 43.656 69.12 ;
    END
  END cfg_addr[6]
  PIN cfg_addr[7]
    DIRECTION INPUT ;
    USE SIGNAL ;
    PORT
      LAYER M5 ;
        RECT  43.728 69.036 43.752 69.12 ;
    END
  END cfg_addr[7]
  PIN cfg_addr[8]
    DIRECTION INPUT ;
    USE SIGNAL ;
    PORT
      LAYER M5 ;
        RECT  43.824 69.036 43.848 69.12 ;
    END
  END cfg_addr[8]
  PIN cfg_addr[9]
    DIRECTION INPUT ;
    USE SIGNAL ;
    PORT
      LAYER M5 ;
        RECT  43.92 69.036 43.944 69.12 ;
    END
  END cfg_addr[9]
  PIN cfg_data[0]
    DIRECTION INPUT ;
    USE SIGNAL ;
    PORT
      LAYER M5 ;
        RECT  44.208 69.036 44.232 69.12 ;
    END
  END cfg_data[0]
  PIN cfg_data[100]
    DIRECTION INPUT ;
    USE SIGNAL ;
    PORT
      LAYER M5 ;
        RECT  38.448 69.036 38.472 69.12 ;
    END
  END cfg_data[100]
  PIN cfg_data[101]
    DIRECTION INPUT ;
    USE SIGNAL ;
    PORT
      LAYER M5 ;
        RECT  38.544 69.036 38.568 69.12 ;
    END
  END cfg_data[101]
  PIN cfg_data[102]
    DIRECTION INPUT ;
    USE SIGNAL ;
    PORT
      LAYER M5 ;
        RECT  38.64 69.036 38.664 69.12 ;
    END
  END cfg_data[102]
  PIN cfg_data[103]
    DIRECTION INPUT ;
    USE SIGNAL ;
    PORT
      LAYER M5 ;
        RECT  38.736 69.036 38.76 69.12 ;
    END
  END cfg_data[103]
  PIN cfg_data[104]
    DIRECTION INPUT ;
    USE SIGNAL ;
    PORT
      LAYER M5 ;
        RECT  38.832 69.036 38.856 69.12 ;
    END
  END cfg_data[104]
  PIN cfg_data[105]
    DIRECTION INPUT ;
    USE SIGNAL ;
    PORT
      LAYER M5 ;
        RECT  38.928 69.036 38.952 69.12 ;
    END
  END cfg_data[105]
  PIN cfg_data[106]
    DIRECTION INPUT ;
    USE SIGNAL ;
    PORT
      LAYER M5 ;
        RECT  39.024 69.036 39.048 69.12 ;
    END
  END cfg_data[106]
  PIN cfg_data[107]
    DIRECTION INPUT ;
    USE SIGNAL ;
    PORT
      LAYER M5 ;
        RECT  39.12 69.036 39.144 69.12 ;
    END
  END cfg_data[107]
  PIN cfg_data[108]
    DIRECTION INPUT ;
    USE SIGNAL ;
    PORT
      LAYER M5 ;
        RECT  39.216 69.036 39.24 69.12 ;
    END
  END cfg_data[108]
  PIN cfg_data[109]
    DIRECTION INPUT ;
    USE SIGNAL ;
    PORT
      LAYER M5 ;
        RECT  39.312 69.036 39.336 69.12 ;
    END
  END cfg_data[109]
  PIN cfg_data[10]
    DIRECTION INPUT ;
    USE SIGNAL ;
    PORT
      LAYER M5 ;
        RECT  45.168 69.036 45.192 69.12 ;
    END
  END cfg_data[10]
  PIN cfg_data[110]
    DIRECTION INPUT ;
    USE SIGNAL ;
    PORT
      LAYER M5 ;
        RECT  39.408 69.036 39.432 69.12 ;
    END
  END cfg_data[110]
  PIN cfg_data[111]
    DIRECTION INPUT ;
    USE SIGNAL ;
    PORT
      LAYER M5 ;
        RECT  39.504 69.036 39.528 69.12 ;
    END
  END cfg_data[111]
  PIN cfg_data[112]
    DIRECTION INPUT ;
    USE SIGNAL ;
    PORT
      LAYER M5 ;
        RECT  39.6 69.036 39.624 69.12 ;
    END
  END cfg_data[112]
  PIN cfg_data[113]
    DIRECTION INPUT ;
    USE SIGNAL ;
    PORT
      LAYER M5 ;
        RECT  39.696 69.036 39.72 69.12 ;
    END
  END cfg_data[113]
  PIN cfg_data[114]
    DIRECTION INPUT ;
    USE SIGNAL ;
    PORT
      LAYER M5 ;
        RECT  39.792 69.036 39.816 69.12 ;
    END
  END cfg_data[114]
  PIN cfg_data[115]
    DIRECTION INPUT ;
    USE SIGNAL ;
    PORT
      LAYER M5 ;
        RECT  39.888 69.036 39.912 69.12 ;
    END
  END cfg_data[115]
  PIN cfg_data[116]
    DIRECTION INPUT ;
    USE SIGNAL ;
    PORT
      LAYER M5 ;
        RECT  46.128 69.036 46.152 69.12 ;
    END
  END cfg_data[116]
  PIN cfg_data[117]
    DIRECTION INPUT ;
    USE SIGNAL ;
    PORT
      LAYER M5 ;
        RECT  46.224 69.036 46.248 69.12 ;
    END
  END cfg_data[117]
  PIN cfg_data[118]
    DIRECTION INPUT ;
    USE SIGNAL ;
    PORT
      LAYER M5 ;
        RECT  46.32 69.036 46.344 69.12 ;
    END
  END cfg_data[118]
  PIN cfg_data[119]
    DIRECTION INPUT ;
    USE SIGNAL ;
    PORT
      LAYER M5 ;
        RECT  46.416 69.036 46.44 69.12 ;
    END
  END cfg_data[119]
  PIN cfg_data[11]
    DIRECTION INPUT ;
    USE SIGNAL ;
    PORT
      LAYER M5 ;
        RECT  45.264 69.036 45.288 69.12 ;
    END
  END cfg_data[11]
  PIN cfg_data[120]
    DIRECTION INPUT ;
    USE SIGNAL ;
    PORT
      LAYER M5 ;
        RECT  46.512 69.036 46.536 69.12 ;
    END
  END cfg_data[120]
  PIN cfg_data[121]
    DIRECTION INPUT ;
    USE SIGNAL ;
    PORT
      LAYER M5 ;
        RECT  46.608 69.036 46.632 69.12 ;
    END
  END cfg_data[121]
  PIN cfg_data[122]
    DIRECTION INPUT ;
    USE SIGNAL ;
    PORT
      LAYER M5 ;
        RECT  46.704 69.036 46.728 69.12 ;
    END
  END cfg_data[122]
  PIN cfg_data[123]
    DIRECTION INPUT ;
    USE SIGNAL ;
    PORT
      LAYER M5 ;
        RECT  46.8 69.036 46.824 69.12 ;
    END
  END cfg_data[123]
  PIN cfg_data[124]
    DIRECTION INPUT ;
    USE SIGNAL ;
    PORT
      LAYER M5 ;
        RECT  46.896 69.036 46.92 69.12 ;
    END
  END cfg_data[124]
  PIN cfg_data[125]
    DIRECTION INPUT ;
    USE SIGNAL ;
    PORT
      LAYER M5 ;
        RECT  46.992 69.036 47.016 69.12 ;
    END
  END cfg_data[125]
  PIN cfg_data[126]
    DIRECTION INPUT ;
    USE SIGNAL ;
    PORT
      LAYER M5 ;
        RECT  47.088 69.036 47.112 69.12 ;
    END
  END cfg_data[126]
  PIN cfg_data[127]
    DIRECTION INPUT ;
    USE SIGNAL ;
    PORT
      LAYER M5 ;
        RECT  47.184 69.036 47.208 69.12 ;
    END
  END cfg_data[127]
  PIN cfg_data[128]
    DIRECTION INPUT ;
    USE SIGNAL ;
    PORT
      LAYER M5 ;
        RECT  47.28 69.036 47.304 69.12 ;
    END
  END cfg_data[128]
  PIN cfg_data[129]
    DIRECTION INPUT ;
    USE SIGNAL ;
    PORT
      LAYER M5 ;
        RECT  47.376 69.036 47.4 69.12 ;
    END
  END cfg_data[129]
  PIN cfg_data[12]
    DIRECTION INPUT ;
    USE SIGNAL ;
    PORT
      LAYER M5 ;
        RECT  45.36 69.036 45.384 69.12 ;
    END
  END cfg_data[12]
  PIN cfg_data[130]
    DIRECTION INPUT ;
    USE SIGNAL ;
    PORT
      LAYER M5 ;
        RECT  47.472 69.036 47.496 69.12 ;
    END
  END cfg_data[130]
  PIN cfg_data[131]
    DIRECTION INPUT ;
    USE SIGNAL ;
    PORT
      LAYER M5 ;
        RECT  47.568 69.036 47.592 69.12 ;
    END
  END cfg_data[131]
  PIN cfg_data[132]
    DIRECTION INPUT ;
    USE SIGNAL ;
    PORT
      LAYER M5 ;
        RECT  47.664 69.036 47.688 69.12 ;
    END
  END cfg_data[132]
  PIN cfg_data[133]
    DIRECTION INPUT ;
    USE SIGNAL ;
    PORT
      LAYER M5 ;
        RECT  47.76 69.036 47.784 69.12 ;
    END
  END cfg_data[133]
  PIN cfg_data[134]
    DIRECTION INPUT ;
    USE SIGNAL ;
    PORT
      LAYER M5 ;
        RECT  47.856 69.036 47.88 69.12 ;
    END
  END cfg_data[134]
  PIN cfg_data[135]
    DIRECTION INPUT ;
    USE SIGNAL ;
    PORT
      LAYER M5 ;
        RECT  47.952 69.036 47.976 69.12 ;
    END
  END cfg_data[135]
  PIN cfg_data[136]
    DIRECTION INPUT ;
    USE SIGNAL ;
    PORT
      LAYER M5 ;
        RECT  48.048 69.036 48.072 69.12 ;
    END
  END cfg_data[136]
  PIN cfg_data[137]
    DIRECTION INPUT ;
    USE SIGNAL ;
    PORT
      LAYER M5 ;
        RECT  48.144 69.036 48.168 69.12 ;
    END
  END cfg_data[137]
  PIN cfg_data[138]
    DIRECTION INPUT ;
    USE SIGNAL ;
    PORT
      LAYER M5 ;
        RECT  48.24 69.036 48.264 69.12 ;
    END
  END cfg_data[138]
  PIN cfg_data[139]
    DIRECTION INPUT ;
    USE SIGNAL ;
    PORT
      LAYER M5 ;
        RECT  48.336 69.036 48.36 69.12 ;
    END
  END cfg_data[139]
  PIN cfg_data[13]
    DIRECTION INPUT ;
    USE SIGNAL ;
    PORT
      LAYER M5 ;
        RECT  45.456 69.036 45.48 69.12 ;
    END
  END cfg_data[13]
  PIN cfg_data[140]
    DIRECTION INPUT ;
    USE SIGNAL ;
    PORT
      LAYER M5 ;
        RECT  48.432 69.036 48.456 69.12 ;
    END
  END cfg_data[140]
  PIN cfg_data[141]
    DIRECTION INPUT ;
    USE SIGNAL ;
    PORT
      LAYER M5 ;
        RECT  48.528 69.036 48.552 69.12 ;
    END
  END cfg_data[141]
  PIN cfg_data[142]
    DIRECTION INPUT ;
    USE SIGNAL ;
    PORT
      LAYER M5 ;
        RECT  48.624 69.036 48.648 69.12 ;
    END
  END cfg_data[142]
  PIN cfg_data[143]
    DIRECTION INPUT ;
    USE SIGNAL ;
    PORT
      LAYER M5 ;
        RECT  48.72 69.036 48.744 69.12 ;
    END
  END cfg_data[143]
  PIN cfg_data[144]
    DIRECTION INPUT ;
    USE SIGNAL ;
    PORT
      LAYER M5 ;
        RECT  48.816 69.036 48.84 69.12 ;
    END
  END cfg_data[144]
  PIN cfg_data[145]
    DIRECTION INPUT ;
    USE SIGNAL ;
    PORT
      LAYER M5 ;
        RECT  48.912 69.036 48.936 69.12 ;
    END
  END cfg_data[145]
  PIN cfg_data[146]
    DIRECTION INPUT ;
    USE SIGNAL ;
    PORT
      LAYER M5 ;
        RECT  49.008 69.036 49.032 69.12 ;
    END
  END cfg_data[146]
  PIN cfg_data[147]
    DIRECTION INPUT ;
    USE SIGNAL ;
    PORT
      LAYER M5 ;
        RECT  49.104 69.036 49.128 69.12 ;
    END
  END cfg_data[147]
  PIN cfg_data[148]
    DIRECTION INPUT ;
    USE SIGNAL ;
    PORT
      LAYER M5 ;
        RECT  30.768 69.036 30.792 69.12 ;
    END
  END cfg_data[148]
  PIN cfg_data[149]
    DIRECTION INPUT ;
    USE SIGNAL ;
    PORT
      LAYER M5 ;
        RECT  30.864 69.036 30.888 69.12 ;
    END
  END cfg_data[149]
  PIN cfg_data[14]
    DIRECTION INPUT ;
    USE SIGNAL ;
    PORT
      LAYER M5 ;
        RECT  45.552 69.036 45.576 69.12 ;
    END
  END cfg_data[14]
  PIN cfg_data[150]
    DIRECTION INPUT ;
    USE SIGNAL ;
    PORT
      LAYER M5 ;
        RECT  30.96 69.036 30.984 69.12 ;
    END
  END cfg_data[150]
  PIN cfg_data[151]
    DIRECTION INPUT ;
    USE SIGNAL ;
    PORT
      LAYER M5 ;
        RECT  31.056 69.036 31.08 69.12 ;
    END
  END cfg_data[151]
  PIN cfg_data[152]
    DIRECTION INPUT ;
    USE SIGNAL ;
    PORT
      LAYER M5 ;
        RECT  31.152 69.036 31.176 69.12 ;
    END
  END cfg_data[152]
  PIN cfg_data[153]
    DIRECTION INPUT ;
    USE SIGNAL ;
    PORT
      LAYER M5 ;
        RECT  31.248 69.036 31.272 69.12 ;
    END
  END cfg_data[153]
  PIN cfg_data[154]
    DIRECTION INPUT ;
    USE SIGNAL ;
    PORT
      LAYER M5 ;
        RECT  31.344 69.036 31.368 69.12 ;
    END
  END cfg_data[154]
  PIN cfg_data[155]
    DIRECTION INPUT ;
    USE SIGNAL ;
    PORT
      LAYER M5 ;
        RECT  31.44 69.036 31.464 69.12 ;
    END
  END cfg_data[155]
  PIN cfg_data[156]
    DIRECTION INPUT ;
    USE SIGNAL ;
    PORT
      LAYER M5 ;
        RECT  31.536 69.036 31.56 69.12 ;
    END
  END cfg_data[156]
  PIN cfg_data[157]
    DIRECTION INPUT ;
    USE SIGNAL ;
    PORT
      LAYER M5 ;
        RECT  31.632 69.036 31.656 69.12 ;
    END
  END cfg_data[157]
  PIN cfg_data[158]
    DIRECTION INPUT ;
    USE SIGNAL ;
    PORT
      LAYER M5 ;
        RECT  31.728 69.036 31.752 69.12 ;
    END
  END cfg_data[158]
  PIN cfg_data[159]
    DIRECTION INPUT ;
    USE SIGNAL ;
    PORT
      LAYER M5 ;
        RECT  31.824 69.036 31.848 69.12 ;
    END
  END cfg_data[159]
  PIN cfg_data[15]
    DIRECTION INPUT ;
    USE SIGNAL ;
    PORT
      LAYER M5 ;
        RECT  45.648 69.036 45.672 69.12 ;
    END
  END cfg_data[15]
  PIN cfg_data[160]
    DIRECTION INPUT ;
    USE SIGNAL ;
    PORT
      LAYER M5 ;
        RECT  31.92 69.036 31.944 69.12 ;
    END
  END cfg_data[160]
  PIN cfg_data[161]
    DIRECTION INPUT ;
    USE SIGNAL ;
    PORT
      LAYER M5 ;
        RECT  32.016 69.036 32.04 69.12 ;
    END
  END cfg_data[161]
  PIN cfg_data[162]
    DIRECTION INPUT ;
    USE SIGNAL ;
    PORT
      LAYER M5 ;
        RECT  32.112 69.036 32.136 69.12 ;
    END
  END cfg_data[162]
  PIN cfg_data[163]
    DIRECTION INPUT ;
    USE SIGNAL ;
    PORT
      LAYER M5 ;
        RECT  32.208 69.036 32.232 69.12 ;
    END
  END cfg_data[163]
  PIN cfg_data[164]
    DIRECTION INPUT ;
    USE SIGNAL ;
    PORT
      LAYER M5 ;
        RECT  32.304 69.036 32.328 69.12 ;
    END
  END cfg_data[164]
  PIN cfg_data[165]
    DIRECTION INPUT ;
    USE SIGNAL ;
    PORT
      LAYER M5 ;
        RECT  32.4 69.036 32.424 69.12 ;
    END
  END cfg_data[165]
  PIN cfg_data[166]
    DIRECTION INPUT ;
    USE SIGNAL ;
    PORT
      LAYER M5 ;
        RECT  32.496 69.036 32.52 69.12 ;
    END
  END cfg_data[166]
  PIN cfg_data[167]
    DIRECTION INPUT ;
    USE SIGNAL ;
    PORT
      LAYER M5 ;
        RECT  32.592 69.036 32.616 69.12 ;
    END
  END cfg_data[167]
  PIN cfg_data[168]
    DIRECTION INPUT ;
    USE SIGNAL ;
    PORT
      LAYER M5 ;
        RECT  32.688 69.036 32.712 69.12 ;
    END
  END cfg_data[168]
  PIN cfg_data[169]
    DIRECTION INPUT ;
    USE SIGNAL ;
    PORT
      LAYER M5 ;
        RECT  32.784 69.036 32.808 69.12 ;
    END
  END cfg_data[169]
  PIN cfg_data[16]
    DIRECTION INPUT ;
    USE SIGNAL ;
    PORT
      LAYER M5 ;
        RECT  45.744 69.036 45.768 69.12 ;
    END
  END cfg_data[16]
  PIN cfg_data[170]
    DIRECTION INPUT ;
    USE SIGNAL ;
    PORT
      LAYER M5 ;
        RECT  32.88 69.036 32.904 69.12 ;
    END
  END cfg_data[170]
  PIN cfg_data[171]
    DIRECTION INPUT ;
    USE SIGNAL ;
    PORT
      LAYER M5 ;
        RECT  32.976 69.036 33 69.12 ;
    END
  END cfg_data[171]
  PIN cfg_data[172]
    DIRECTION INPUT ;
    USE SIGNAL ;
    PORT
      LAYER M5 ;
        RECT  33.072 69.036 33.096 69.12 ;
    END
  END cfg_data[172]
  PIN cfg_data[173]
    DIRECTION INPUT ;
    USE SIGNAL ;
    PORT
      LAYER M5 ;
        RECT  33.168 69.036 33.192 69.12 ;
    END
  END cfg_data[173]
  PIN cfg_data[174]
    DIRECTION INPUT ;
    USE SIGNAL ;
    PORT
      LAYER M5 ;
        RECT  33.264 69.036 33.288 69.12 ;
    END
  END cfg_data[174]
  PIN cfg_data[175]
    DIRECTION INPUT ;
    USE SIGNAL ;
    PORT
      LAYER M5 ;
        RECT  33.36 69.036 33.384 69.12 ;
    END
  END cfg_data[175]
  PIN cfg_data[176]
    DIRECTION INPUT ;
    USE SIGNAL ;
    PORT
      LAYER M5 ;
        RECT  33.456 69.036 33.48 69.12 ;
    END
  END cfg_data[176]
  PIN cfg_data[177]
    DIRECTION INPUT ;
    USE SIGNAL ;
    PORT
      LAYER M5 ;
        RECT  33.552 69.036 33.576 69.12 ;
    END
  END cfg_data[177]
  PIN cfg_data[178]
    DIRECTION INPUT ;
    USE SIGNAL ;
    PORT
      LAYER M5 ;
        RECT  33.648 69.036 33.672 69.12 ;
    END
  END cfg_data[178]
  PIN cfg_data[179]
    DIRECTION INPUT ;
    USE SIGNAL ;
    PORT
      LAYER M5 ;
        RECT  33.744 69.036 33.768 69.12 ;
    END
  END cfg_data[179]
  PIN cfg_data[17]
    DIRECTION INPUT ;
    USE SIGNAL ;
    PORT
      LAYER M5 ;
        RECT  45.84 69.036 45.864 69.12 ;
    END
  END cfg_data[17]
  PIN cfg_data[180]
    DIRECTION INPUT ;
    USE SIGNAL ;
    PORT
      LAYER M5 ;
        RECT  17.712 69.036 17.736 69.12 ;
    END
  END cfg_data[180]
  PIN cfg_data[181]
    DIRECTION INPUT ;
    USE SIGNAL ;
    PORT
      LAYER M5 ;
        RECT  17.808 69.036 17.832 69.12 ;
    END
  END cfg_data[181]
  PIN cfg_data[182]
    DIRECTION INPUT ;
    USE SIGNAL ;
    PORT
      LAYER M5 ;
        RECT  17.904 69.036 17.928 69.12 ;
    END
  END cfg_data[182]
  PIN cfg_data[183]
    DIRECTION INPUT ;
    USE SIGNAL ;
    PORT
      LAYER M5 ;
        RECT  18 69.036 18.024 69.12 ;
    END
  END cfg_data[183]
  PIN cfg_data[184]
    DIRECTION INPUT ;
    USE SIGNAL ;
    PORT
      LAYER M5 ;
        RECT  18.096 69.036 18.12 69.12 ;
    END
  END cfg_data[184]
  PIN cfg_data[185]
    DIRECTION INPUT ;
    USE SIGNAL ;
    PORT
      LAYER M5 ;
        RECT  18.192 69.036 18.216 69.12 ;
    END
  END cfg_data[185]
  PIN cfg_data[186]
    DIRECTION INPUT ;
    USE SIGNAL ;
    PORT
      LAYER M5 ;
        RECT  18.288 69.036 18.312 69.12 ;
    END
  END cfg_data[186]
  PIN cfg_data[187]
    DIRECTION INPUT ;
    USE SIGNAL ;
    PORT
      LAYER M5 ;
        RECT  18.384 69.036 18.408 69.12 ;
    END
  END cfg_data[187]
  PIN cfg_data[188]
    DIRECTION INPUT ;
    USE SIGNAL ;
    PORT
      LAYER M5 ;
        RECT  18.48 69.036 18.504 69.12 ;
    END
  END cfg_data[188]
  PIN cfg_data[189]
    DIRECTION INPUT ;
    USE SIGNAL ;
    PORT
      LAYER M5 ;
        RECT  18.576 69.036 18.6 69.12 ;
    END
  END cfg_data[189]
  PIN cfg_data[18]
    DIRECTION INPUT ;
    USE SIGNAL ;
    PORT
      LAYER M5 ;
        RECT  45.936 69.036 45.96 69.12 ;
    END
  END cfg_data[18]
  PIN cfg_data[190]
    DIRECTION INPUT ;
    USE SIGNAL ;
    PORT
      LAYER M5 ;
        RECT  18.672 69.036 18.696 69.12 ;
    END
  END cfg_data[190]
  PIN cfg_data[191]
    DIRECTION INPUT ;
    USE SIGNAL ;
    PORT
      LAYER M5 ;
        RECT  18.768 69.036 18.792 69.12 ;
    END
  END cfg_data[191]
  PIN cfg_data[192]
    DIRECTION INPUT ;
    USE SIGNAL ;
    PORT
      LAYER M5 ;
        RECT  18.864 69.036 18.888 69.12 ;
    END
  END cfg_data[192]
  PIN cfg_data[193]
    DIRECTION INPUT ;
    USE SIGNAL ;
    PORT
      LAYER M5 ;
        RECT  18.96 69.036 18.984 69.12 ;
    END
  END cfg_data[193]
  PIN cfg_data[194]
    DIRECTION INPUT ;
    USE SIGNAL ;
    PORT
      LAYER M5 ;
        RECT  19.056 69.036 19.08 69.12 ;
    END
  END cfg_data[194]
  PIN cfg_data[195]
    DIRECTION INPUT ;
    USE SIGNAL ;
    PORT
      LAYER M5 ;
        RECT  19.152 69.036 19.176 69.12 ;
    END
  END cfg_data[195]
  PIN cfg_data[196]
    DIRECTION INPUT ;
    USE SIGNAL ;
    PORT
      LAYER M5 ;
        RECT  19.248 69.036 19.272 69.12 ;
    END
  END cfg_data[196]
  PIN cfg_data[197]
    DIRECTION INPUT ;
    USE SIGNAL ;
    PORT
      LAYER M5 ;
        RECT  19.344 69.036 19.368 69.12 ;
    END
  END cfg_data[197]
  PIN cfg_data[198]
    DIRECTION INPUT ;
    USE SIGNAL ;
    PORT
      LAYER M5 ;
        RECT  19.44 69.036 19.464 69.12 ;
    END
  END cfg_data[198]
  PIN cfg_data[199]
    DIRECTION INPUT ;
    USE SIGNAL ;
    PORT
      LAYER M5 ;
        RECT  19.536 69.036 19.56 69.12 ;
    END
  END cfg_data[199]
  PIN cfg_data[19]
    DIRECTION INPUT ;
    USE SIGNAL ;
    PORT
      LAYER M5 ;
        RECT  46.032 69.036 46.056 69.12 ;
    END
  END cfg_data[19]
  PIN cfg_data[1]
    DIRECTION INPUT ;
    USE SIGNAL ;
    PORT
      LAYER M5 ;
        RECT  44.304 69.036 44.328 69.12 ;
    END
  END cfg_data[1]
  PIN cfg_data[200]
    DIRECTION INPUT ;
    USE SIGNAL ;
    PORT
      LAYER M5 ;
        RECT  19.632 69.036 19.656 69.12 ;
    END
  END cfg_data[200]
  PIN cfg_data[201]
    DIRECTION INPUT ;
    USE SIGNAL ;
    PORT
      LAYER M5 ;
        RECT  19.728 69.036 19.752 69.12 ;
    END
  END cfg_data[201]
  PIN cfg_data[202]
    DIRECTION INPUT ;
    USE SIGNAL ;
    PORT
      LAYER M5 ;
        RECT  19.824 69.036 19.848 69.12 ;
    END
  END cfg_data[202]
  PIN cfg_data[203]
    DIRECTION INPUT ;
    USE SIGNAL ;
    PORT
      LAYER M5 ;
        RECT  19.92 69.036 19.944 69.12 ;
    END
  END cfg_data[203]
  PIN cfg_data[204]
    DIRECTION INPUT ;
    USE SIGNAL ;
    PORT
      LAYER M5 ;
        RECT  20.016 69.036 20.04 69.12 ;
    END
  END cfg_data[204]
  PIN cfg_data[205]
    DIRECTION INPUT ;
    USE SIGNAL ;
    PORT
      LAYER M5 ;
        RECT  20.112 69.036 20.136 69.12 ;
    END
  END cfg_data[205]
  PIN cfg_data[206]
    DIRECTION INPUT ;
    USE SIGNAL ;
    PORT
      LAYER M5 ;
        RECT  20.208 69.036 20.232 69.12 ;
    END
  END cfg_data[206]
  PIN cfg_data[207]
    DIRECTION INPUT ;
    USE SIGNAL ;
    PORT
      LAYER M5 ;
        RECT  20.304 69.036 20.328 69.12 ;
    END
  END cfg_data[207]
  PIN cfg_data[208]
    DIRECTION INPUT ;
    USE SIGNAL ;
    PORT
      LAYER M5 ;
        RECT  20.4 69.036 20.424 69.12 ;
    END
  END cfg_data[208]
  PIN cfg_data[209]
    DIRECTION INPUT ;
    USE SIGNAL ;
    PORT
      LAYER M5 ;
        RECT  20.496 69.036 20.52 69.12 ;
    END
  END cfg_data[209]
  PIN cfg_data[20]
    DIRECTION INPUT ;
    USE SIGNAL ;
    PORT
      LAYER M5 ;
        RECT  33.84 69.036 33.864 69.12 ;
    END
  END cfg_data[20]
  PIN cfg_data[210]
    DIRECTION INPUT ;
    USE SIGNAL ;
    PORT
      LAYER M5 ;
        RECT  20.592 69.036 20.616 69.12 ;
    END
  END cfg_data[210]
  PIN cfg_data[211]
    DIRECTION INPUT ;
    USE SIGNAL ;
    PORT
      LAYER M5 ;
        RECT  20.688 69.036 20.712 69.12 ;
    END
  END cfg_data[211]
  PIN cfg_data[212]
    DIRECTION INPUT ;
    USE SIGNAL ;
    PORT
      LAYER M5 ;
        RECT  26.928 69.036 26.952 69.12 ;
    END
  END cfg_data[212]
  PIN cfg_data[213]
    DIRECTION INPUT ;
    USE SIGNAL ;
    PORT
      LAYER M5 ;
        RECT  27.024 69.036 27.048 69.12 ;
    END
  END cfg_data[213]
  PIN cfg_data[214]
    DIRECTION INPUT ;
    USE SIGNAL ;
    PORT
      LAYER M5 ;
        RECT  27.12 69.036 27.144 69.12 ;
    END
  END cfg_data[214]
  PIN cfg_data[215]
    DIRECTION INPUT ;
    USE SIGNAL ;
    PORT
      LAYER M5 ;
        RECT  27.216 69.036 27.24 69.12 ;
    END
  END cfg_data[215]
  PIN cfg_data[216]
    DIRECTION INPUT ;
    USE SIGNAL ;
    PORT
      LAYER M5 ;
        RECT  27.312 69.036 27.336 69.12 ;
    END
  END cfg_data[216]
  PIN cfg_data[217]
    DIRECTION INPUT ;
    USE SIGNAL ;
    PORT
      LAYER M5 ;
        RECT  27.408 69.036 27.432 69.12 ;
    END
  END cfg_data[217]
  PIN cfg_data[218]
    DIRECTION INPUT ;
    USE SIGNAL ;
    PORT
      LAYER M5 ;
        RECT  27.504 69.036 27.528 69.12 ;
    END
  END cfg_data[218]
  PIN cfg_data[219]
    DIRECTION INPUT ;
    USE SIGNAL ;
    PORT
      LAYER M5 ;
        RECT  27.6 69.036 27.624 69.12 ;
    END
  END cfg_data[219]
  PIN cfg_data[21]
    DIRECTION INPUT ;
    USE SIGNAL ;
    PORT
      LAYER M5 ;
        RECT  33.936 69.036 33.96 69.12 ;
    END
  END cfg_data[21]
  PIN cfg_data[220]
    DIRECTION INPUT ;
    USE SIGNAL ;
    PORT
      LAYER M5 ;
        RECT  27.696 69.036 27.72 69.12 ;
    END
  END cfg_data[220]
  PIN cfg_data[221]
    DIRECTION INPUT ;
    USE SIGNAL ;
    PORT
      LAYER M5 ;
        RECT  27.792 69.036 27.816 69.12 ;
    END
  END cfg_data[221]
  PIN cfg_data[222]
    DIRECTION INPUT ;
    USE SIGNAL ;
    PORT
      LAYER M5 ;
        RECT  27.888 69.036 27.912 69.12 ;
    END
  END cfg_data[222]
  PIN cfg_data[223]
    DIRECTION INPUT ;
    USE SIGNAL ;
    PORT
      LAYER M5 ;
        RECT  27.984 69.036 28.008 69.12 ;
    END
  END cfg_data[223]
  PIN cfg_data[224]
    DIRECTION INPUT ;
    USE SIGNAL ;
    PORT
      LAYER M5 ;
        RECT  28.08 69.036 28.104 69.12 ;
    END
  END cfg_data[224]
  PIN cfg_data[225]
    DIRECTION INPUT ;
    USE SIGNAL ;
    PORT
      LAYER M5 ;
        RECT  28.176 69.036 28.2 69.12 ;
    END
  END cfg_data[225]
  PIN cfg_data[226]
    DIRECTION INPUT ;
    USE SIGNAL ;
    PORT
      LAYER M5 ;
        RECT  28.272 69.036 28.296 69.12 ;
    END
  END cfg_data[226]
  PIN cfg_data[227]
    DIRECTION INPUT ;
    USE SIGNAL ;
    PORT
      LAYER M5 ;
        RECT  28.368 69.036 28.392 69.12 ;
    END
  END cfg_data[227]
  PIN cfg_data[228]
    DIRECTION INPUT ;
    USE SIGNAL ;
    PORT
      LAYER M5 ;
        RECT  28.464 69.036 28.488 69.12 ;
    END
  END cfg_data[228]
  PIN cfg_data[229]
    DIRECTION INPUT ;
    USE SIGNAL ;
    PORT
      LAYER M5 ;
        RECT  28.56 69.036 28.584 69.12 ;
    END
  END cfg_data[229]
  PIN cfg_data[22]
    DIRECTION INPUT ;
    USE SIGNAL ;
    PORT
      LAYER M5 ;
        RECT  34.032 69.036 34.056 69.12 ;
    END
  END cfg_data[22]
  PIN cfg_data[230]
    DIRECTION INPUT ;
    USE SIGNAL ;
    PORT
      LAYER M5 ;
        RECT  28.656 69.036 28.68 69.12 ;
    END
  END cfg_data[230]
  PIN cfg_data[231]
    DIRECTION INPUT ;
    USE SIGNAL ;
    PORT
      LAYER M5 ;
        RECT  28.752 69.036 28.776 69.12 ;
    END
  END cfg_data[231]
  PIN cfg_data[232]
    DIRECTION INPUT ;
    USE SIGNAL ;
    PORT
      LAYER M5 ;
        RECT  28.848 69.036 28.872 69.12 ;
    END
  END cfg_data[232]
  PIN cfg_data[233]
    DIRECTION INPUT ;
    USE SIGNAL ;
    PORT
      LAYER M5 ;
        RECT  28.944 69.036 28.968 69.12 ;
    END
  END cfg_data[233]
  PIN cfg_data[234]
    DIRECTION INPUT ;
    USE SIGNAL ;
    PORT
      LAYER M5 ;
        RECT  29.04 69.036 29.064 69.12 ;
    END
  END cfg_data[234]
  PIN cfg_data[235]
    DIRECTION INPUT ;
    USE SIGNAL ;
    PORT
      LAYER M5 ;
        RECT  29.136 69.036 29.16 69.12 ;
    END
  END cfg_data[235]
  PIN cfg_data[236]
    DIRECTION INPUT ;
    USE SIGNAL ;
    PORT
      LAYER M5 ;
        RECT  29.232 69.036 29.256 69.12 ;
    END
  END cfg_data[236]
  PIN cfg_data[237]
    DIRECTION INPUT ;
    USE SIGNAL ;
    PORT
      LAYER M5 ;
        RECT  29.328 69.036 29.352 69.12 ;
    END
  END cfg_data[237]
  PIN cfg_data[238]
    DIRECTION INPUT ;
    USE SIGNAL ;
    PORT
      LAYER M5 ;
        RECT  29.424 69.036 29.448 69.12 ;
    END
  END cfg_data[238]
  PIN cfg_data[239]
    DIRECTION INPUT ;
    USE SIGNAL ;
    PORT
      LAYER M5 ;
        RECT  29.52 69.036 29.544 69.12 ;
    END
  END cfg_data[239]
  PIN cfg_data[23]
    DIRECTION INPUT ;
    USE SIGNAL ;
    PORT
      LAYER M5 ;
        RECT  34.128 69.036 34.152 69.12 ;
    END
  END cfg_data[23]
  PIN cfg_data[240]
    DIRECTION INPUT ;
    USE SIGNAL ;
    PORT
      LAYER M5 ;
        RECT  29.616 69.036 29.64 69.12 ;
    END
  END cfg_data[240]
  PIN cfg_data[241]
    DIRECTION INPUT ;
    USE SIGNAL ;
    PORT
      LAYER M5 ;
        RECT  29.712 69.036 29.736 69.12 ;
    END
  END cfg_data[241]
  PIN cfg_data[242]
    DIRECTION INPUT ;
    USE SIGNAL ;
    PORT
      LAYER M5 ;
        RECT  29.808 69.036 29.832 69.12 ;
    END
  END cfg_data[242]
  PIN cfg_data[243]
    DIRECTION INPUT ;
    USE SIGNAL ;
    PORT
      LAYER M5 ;
        RECT  29.904 69.036 29.928 69.12 ;
    END
  END cfg_data[243]
  PIN cfg_data[244]
    DIRECTION INPUT ;
    USE SIGNAL ;
    PORT
      LAYER M5 ;
        RECT  20.784 69.036 20.808 69.12 ;
    END
  END cfg_data[244]
  PIN cfg_data[245]
    DIRECTION INPUT ;
    USE SIGNAL ;
    PORT
      LAYER M5 ;
        RECT  20.88 69.036 20.904 69.12 ;
    END
  END cfg_data[245]
  PIN cfg_data[246]
    DIRECTION INPUT ;
    USE SIGNAL ;
    PORT
      LAYER M5 ;
        RECT  20.976 69.036 21 69.12 ;
    END
  END cfg_data[246]
  PIN cfg_data[247]
    DIRECTION INPUT ;
    USE SIGNAL ;
    PORT
      LAYER M5 ;
        RECT  21.072 69.036 21.096 69.12 ;
    END
  END cfg_data[247]
  PIN cfg_data[248]
    DIRECTION INPUT ;
    USE SIGNAL ;
    PORT
      LAYER M5 ;
        RECT  21.168 69.036 21.192 69.12 ;
    END
  END cfg_data[248]
  PIN cfg_data[249]
    DIRECTION INPUT ;
    USE SIGNAL ;
    PORT
      LAYER M5 ;
        RECT  21.264 69.036 21.288 69.12 ;
    END
  END cfg_data[249]
  PIN cfg_data[24]
    DIRECTION INPUT ;
    USE SIGNAL ;
    PORT
      LAYER M5 ;
        RECT  34.224 69.036 34.248 69.12 ;
    END
  END cfg_data[24]
  PIN cfg_data[250]
    DIRECTION INPUT ;
    USE SIGNAL ;
    PORT
      LAYER M5 ;
        RECT  21.36 69.036 21.384 69.12 ;
    END
  END cfg_data[250]
  PIN cfg_data[251]
    DIRECTION INPUT ;
    USE SIGNAL ;
    PORT
      LAYER M5 ;
        RECT  21.456 69.036 21.48 69.12 ;
    END
  END cfg_data[251]
  PIN cfg_data[252]
    DIRECTION INPUT ;
    USE SIGNAL ;
    PORT
      LAYER M5 ;
        RECT  21.552 69.036 21.576 69.12 ;
    END
  END cfg_data[252]
  PIN cfg_data[253]
    DIRECTION INPUT ;
    USE SIGNAL ;
    PORT
      LAYER M5 ;
        RECT  21.648 69.036 21.672 69.12 ;
    END
  END cfg_data[253]
  PIN cfg_data[254]
    DIRECTION INPUT ;
    USE SIGNAL ;
    PORT
      LAYER M5 ;
        RECT  21.744 69.036 21.768 69.12 ;
    END
  END cfg_data[254]
  PIN cfg_data[255]
    DIRECTION INPUT ;
    USE SIGNAL ;
    PORT
      LAYER M5 ;
        RECT  21.84 69.036 21.864 69.12 ;
    END
  END cfg_data[255]
  PIN cfg_data[25]
    DIRECTION INPUT ;
    USE SIGNAL ;
    PORT
      LAYER M5 ;
        RECT  34.32 69.036 34.344 69.12 ;
    END
  END cfg_data[25]
  PIN cfg_data[26]
    DIRECTION INPUT ;
    USE SIGNAL ;
    PORT
      LAYER M5 ;
        RECT  34.416 69.036 34.44 69.12 ;
    END
  END cfg_data[26]
  PIN cfg_data[27]
    DIRECTION INPUT ;
    USE SIGNAL ;
    PORT
      LAYER M5 ;
        RECT  34.512 69.036 34.536 69.12 ;
    END
  END cfg_data[27]
  PIN cfg_data[28]
    DIRECTION INPUT ;
    USE SIGNAL ;
    PORT
      LAYER M5 ;
        RECT  34.608 69.036 34.632 69.12 ;
    END
  END cfg_data[28]
  PIN cfg_data[29]
    DIRECTION INPUT ;
    USE SIGNAL ;
    PORT
      LAYER M5 ;
        RECT  34.704 69.036 34.728 69.12 ;
    END
  END cfg_data[29]
  PIN cfg_data[2]
    DIRECTION INPUT ;
    USE SIGNAL ;
    PORT
      LAYER M5 ;
        RECT  44.4 69.036 44.424 69.12 ;
    END
  END cfg_data[2]
  PIN cfg_data[30]
    DIRECTION INPUT ;
    USE SIGNAL ;
    PORT
      LAYER M5 ;
        RECT  34.8 69.036 34.824 69.12 ;
    END
  END cfg_data[30]
  PIN cfg_data[31]
    DIRECTION INPUT ;
    USE SIGNAL ;
    PORT
      LAYER M5 ;
        RECT  34.896 69.036 34.92 69.12 ;
    END
  END cfg_data[31]
  PIN cfg_data[32]
    DIRECTION INPUT ;
    USE SIGNAL ;
    PORT
      LAYER M5 ;
        RECT  34.992 69.036 35.016 69.12 ;
    END
  END cfg_data[32]
  PIN cfg_data[33]
    DIRECTION INPUT ;
    USE SIGNAL ;
    PORT
      LAYER M5 ;
        RECT  35.088 69.036 35.112 69.12 ;
    END
  END cfg_data[33]
  PIN cfg_data[34]
    DIRECTION INPUT ;
    USE SIGNAL ;
    PORT
      LAYER M5 ;
        RECT  35.184 69.036 35.208 69.12 ;
    END
  END cfg_data[34]
  PIN cfg_data[35]
    DIRECTION INPUT ;
    USE SIGNAL ;
    PORT
      LAYER M5 ;
        RECT  35.28 69.036 35.304 69.12 ;
    END
  END cfg_data[35]
  PIN cfg_data[36]
    DIRECTION INPUT ;
    USE SIGNAL ;
    PORT
      LAYER M5 ;
        RECT  35.376 69.036 35.4 69.12 ;
    END
  END cfg_data[36]
  PIN cfg_data[37]
    DIRECTION INPUT ;
    USE SIGNAL ;
    PORT
      LAYER M5 ;
        RECT  35.472 69.036 35.496 69.12 ;
    END
  END cfg_data[37]
  PIN cfg_data[38]
    DIRECTION INPUT ;
    USE SIGNAL ;
    PORT
      LAYER M5 ;
        RECT  35.568 69.036 35.592 69.12 ;
    END
  END cfg_data[38]
  PIN cfg_data[39]
    DIRECTION INPUT ;
    USE SIGNAL ;
    PORT
      LAYER M5 ;
        RECT  35.664 69.036 35.688 69.12 ;
    END
  END cfg_data[39]
  PIN cfg_data[3]
    DIRECTION INPUT ;
    USE SIGNAL ;
    PORT
      LAYER M5 ;
        RECT  44.496 69.036 44.52 69.12 ;
    END
  END cfg_data[3]
  PIN cfg_data[40]
    DIRECTION INPUT ;
    USE SIGNAL ;
    PORT
      LAYER M5 ;
        RECT  35.76 69.036 35.784 69.12 ;
    END
  END cfg_data[40]
  PIN cfg_data[41]
    DIRECTION INPUT ;
    USE SIGNAL ;
    PORT
      LAYER M5 ;
        RECT  35.856 69.036 35.88 69.12 ;
    END
  END cfg_data[41]
  PIN cfg_data[42]
    DIRECTION INPUT ;
    USE SIGNAL ;
    PORT
      LAYER M5 ;
        RECT  35.952 69.036 35.976 69.12 ;
    END
  END cfg_data[42]
  PIN cfg_data[43]
    DIRECTION INPUT ;
    USE SIGNAL ;
    PORT
      LAYER M5 ;
        RECT  36.048 69.036 36.072 69.12 ;
    END
  END cfg_data[43]
  PIN cfg_data[44]
    DIRECTION INPUT ;
    USE SIGNAL ;
    PORT
      LAYER M5 ;
        RECT  36.144 69.036 36.168 69.12 ;
    END
  END cfg_data[44]
  PIN cfg_data[45]
    DIRECTION INPUT ;
    USE SIGNAL ;
    PORT
      LAYER M5 ;
        RECT  36.24 69.036 36.264 69.12 ;
    END
  END cfg_data[45]
  PIN cfg_data[46]
    DIRECTION INPUT ;
    USE SIGNAL ;
    PORT
      LAYER M5 ;
        RECT  36.336 69.036 36.36 69.12 ;
    END
  END cfg_data[46]
  PIN cfg_data[47]
    DIRECTION INPUT ;
    USE SIGNAL ;
    PORT
      LAYER M5 ;
        RECT  36.432 69.036 36.456 69.12 ;
    END
  END cfg_data[47]
  PIN cfg_data[48]
    DIRECTION INPUT ;
    USE SIGNAL ;
    PORT
      LAYER M5 ;
        RECT  36.528 69.036 36.552 69.12 ;
    END
  END cfg_data[48]
  PIN cfg_data[49]
    DIRECTION INPUT ;
    USE SIGNAL ;
    PORT
      LAYER M5 ;
        RECT  36.624 69.036 36.648 69.12 ;
    END
  END cfg_data[49]
  PIN cfg_data[4]
    DIRECTION INPUT ;
    USE SIGNAL ;
    PORT
      LAYER M5 ;
        RECT  44.592 69.036 44.616 69.12 ;
    END
  END cfg_data[4]
  PIN cfg_data[50]
    DIRECTION INPUT ;
    USE SIGNAL ;
    PORT
      LAYER M5 ;
        RECT  36.72 69.036 36.744 69.12 ;
    END
  END cfg_data[50]
  PIN cfg_data[51]
    DIRECTION INPUT ;
    USE SIGNAL ;
    PORT
      LAYER M5 ;
        RECT  36.816 69.036 36.84 69.12 ;
    END
  END cfg_data[51]
  PIN cfg_data[52]
    DIRECTION INPUT ;
    USE SIGNAL ;
    PORT
      LAYER M5 ;
        RECT  39.984 69.036 40.008 69.12 ;
    END
  END cfg_data[52]
  PIN cfg_data[53]
    DIRECTION INPUT ;
    USE SIGNAL ;
    PORT
      LAYER M5 ;
        RECT  40.08 69.036 40.104 69.12 ;
    END
  END cfg_data[53]
  PIN cfg_data[54]
    DIRECTION INPUT ;
    USE SIGNAL ;
    PORT
      LAYER M5 ;
        RECT  40.176 69.036 40.2 69.12 ;
    END
  END cfg_data[54]
  PIN cfg_data[55]
    DIRECTION INPUT ;
    USE SIGNAL ;
    PORT
      LAYER M5 ;
        RECT  40.272 69.036 40.296 69.12 ;
    END
  END cfg_data[55]
  PIN cfg_data[56]
    DIRECTION INPUT ;
    USE SIGNAL ;
    PORT
      LAYER M5 ;
        RECT  40.368 69.036 40.392 69.12 ;
    END
  END cfg_data[56]
  PIN cfg_data[57]
    DIRECTION INPUT ;
    USE SIGNAL ;
    PORT
      LAYER M5 ;
        RECT  40.464 69.036 40.488 69.12 ;
    END
  END cfg_data[57]
  PIN cfg_data[58]
    DIRECTION INPUT ;
    USE SIGNAL ;
    PORT
      LAYER M5 ;
        RECT  40.56 69.036 40.584 69.12 ;
    END
  END cfg_data[58]
  PIN cfg_data[59]
    DIRECTION INPUT ;
    USE SIGNAL ;
    PORT
      LAYER M5 ;
        RECT  40.656 69.036 40.68 69.12 ;
    END
  END cfg_data[59]
  PIN cfg_data[5]
    DIRECTION INPUT ;
    USE SIGNAL ;
    PORT
      LAYER M5 ;
        RECT  44.688 69.036 44.712 69.12 ;
    END
  END cfg_data[5]
  PIN cfg_data[60]
    DIRECTION INPUT ;
    USE SIGNAL ;
    PORT
      LAYER M5 ;
        RECT  40.752 69.036 40.776 69.12 ;
    END
  END cfg_data[60]
  PIN cfg_data[61]
    DIRECTION INPUT ;
    USE SIGNAL ;
    PORT
      LAYER M5 ;
        RECT  40.848 69.036 40.872 69.12 ;
    END
  END cfg_data[61]
  PIN cfg_data[62]
    DIRECTION INPUT ;
    USE SIGNAL ;
    PORT
      LAYER M5 ;
        RECT  40.944 69.036 40.968 69.12 ;
    END
  END cfg_data[62]
  PIN cfg_data[63]
    DIRECTION INPUT ;
    USE SIGNAL ;
    PORT
      LAYER M5 ;
        RECT  41.04 69.036 41.064 69.12 ;
    END
  END cfg_data[63]
  PIN cfg_data[64]
    DIRECTION INPUT ;
    USE SIGNAL ;
    PORT
      LAYER M5 ;
        RECT  41.136 69.036 41.16 69.12 ;
    END
  END cfg_data[64]
  PIN cfg_data[65]
    DIRECTION INPUT ;
    USE SIGNAL ;
    PORT
      LAYER M5 ;
        RECT  41.232 69.036 41.256 69.12 ;
    END
  END cfg_data[65]
  PIN cfg_data[66]
    DIRECTION INPUT ;
    USE SIGNAL ;
    PORT
      LAYER M5 ;
        RECT  41.328 69.036 41.352 69.12 ;
    END
  END cfg_data[66]
  PIN cfg_data[67]
    DIRECTION INPUT ;
    USE SIGNAL ;
    PORT
      LAYER M5 ;
        RECT  41.424 69.036 41.448 69.12 ;
    END
  END cfg_data[67]
  PIN cfg_data[68]
    DIRECTION INPUT ;
    USE SIGNAL ;
    PORT
      LAYER M5 ;
        RECT  41.52 69.036 41.544 69.12 ;
    END
  END cfg_data[68]
  PIN cfg_data[69]
    DIRECTION INPUT ;
    USE SIGNAL ;
    PORT
      LAYER M5 ;
        RECT  41.616 69.036 41.64 69.12 ;
    END
  END cfg_data[69]
  PIN cfg_data[6]
    DIRECTION INPUT ;
    USE SIGNAL ;
    PORT
      LAYER M5 ;
        RECT  44.784 69.036 44.808 69.12 ;
    END
  END cfg_data[6]
  PIN cfg_data[70]
    DIRECTION INPUT ;
    USE SIGNAL ;
    PORT
      LAYER M5 ;
        RECT  41.712 69.036 41.736 69.12 ;
    END
  END cfg_data[70]
  PIN cfg_data[71]
    DIRECTION INPUT ;
    USE SIGNAL ;
    PORT
      LAYER M5 ;
        RECT  41.808 69.036 41.832 69.12 ;
    END
  END cfg_data[71]
  PIN cfg_data[72]
    DIRECTION INPUT ;
    USE SIGNAL ;
    PORT
      LAYER M5 ;
        RECT  41.904 69.036 41.928 69.12 ;
    END
  END cfg_data[72]
  PIN cfg_data[73]
    DIRECTION INPUT ;
    USE SIGNAL ;
    PORT
      LAYER M5 ;
        RECT  42 69.036 42.024 69.12 ;
    END
  END cfg_data[73]
  PIN cfg_data[74]
    DIRECTION INPUT ;
    USE SIGNAL ;
    PORT
      LAYER M5 ;
        RECT  42.096 69.036 42.12 69.12 ;
    END
  END cfg_data[74]
  PIN cfg_data[75]
    DIRECTION INPUT ;
    USE SIGNAL ;
    PORT
      LAYER M5 ;
        RECT  42.192 69.036 42.216 69.12 ;
    END
  END cfg_data[75]
  PIN cfg_data[76]
    DIRECTION INPUT ;
    USE SIGNAL ;
    PORT
      LAYER M5 ;
        RECT  42.288 69.036 42.312 69.12 ;
    END
  END cfg_data[76]
  PIN cfg_data[77]
    DIRECTION INPUT ;
    USE SIGNAL ;
    PORT
      LAYER M5 ;
        RECT  42.384 69.036 42.408 69.12 ;
    END
  END cfg_data[77]
  PIN cfg_data[78]
    DIRECTION INPUT ;
    USE SIGNAL ;
    PORT
      LAYER M5 ;
        RECT  42.48 69.036 42.504 69.12 ;
    END
  END cfg_data[78]
  PIN cfg_data[79]
    DIRECTION INPUT ;
    USE SIGNAL ;
    PORT
      LAYER M5 ;
        RECT  42.576 69.036 42.6 69.12 ;
    END
  END cfg_data[79]
  PIN cfg_data[7]
    DIRECTION INPUT ;
    USE SIGNAL ;
    PORT
      LAYER M5 ;
        RECT  44.88 69.036 44.904 69.12 ;
    END
  END cfg_data[7]
  PIN cfg_data[80]
    DIRECTION INPUT ;
    USE SIGNAL ;
    PORT
      LAYER M5 ;
        RECT  42.672 69.036 42.696 69.12 ;
    END
  END cfg_data[80]
  PIN cfg_data[81]
    DIRECTION INPUT ;
    USE SIGNAL ;
    PORT
      LAYER M5 ;
        RECT  42.768 69.036 42.792 69.12 ;
    END
  END cfg_data[81]
  PIN cfg_data[82]
    DIRECTION INPUT ;
    USE SIGNAL ;
    PORT
      LAYER M5 ;
        RECT  42.864 69.036 42.888 69.12 ;
    END
  END cfg_data[82]
  PIN cfg_data[83]
    DIRECTION INPUT ;
    USE SIGNAL ;
    PORT
      LAYER M5 ;
        RECT  42.96 69.036 42.984 69.12 ;
    END
  END cfg_data[83]
  PIN cfg_data[84]
    DIRECTION INPUT ;
    USE SIGNAL ;
    PORT
      LAYER M5 ;
        RECT  36.912 69.036 36.936 69.12 ;
    END
  END cfg_data[84]
  PIN cfg_data[85]
    DIRECTION INPUT ;
    USE SIGNAL ;
    PORT
      LAYER M5 ;
        RECT  37.008 69.036 37.032 69.12 ;
    END
  END cfg_data[85]
  PIN cfg_data[86]
    DIRECTION INPUT ;
    USE SIGNAL ;
    PORT
      LAYER M5 ;
        RECT  37.104 69.036 37.128 69.12 ;
    END
  END cfg_data[86]
  PIN cfg_data[87]
    DIRECTION INPUT ;
    USE SIGNAL ;
    PORT
      LAYER M5 ;
        RECT  37.2 69.036 37.224 69.12 ;
    END
  END cfg_data[87]
  PIN cfg_data[88]
    DIRECTION INPUT ;
    USE SIGNAL ;
    PORT
      LAYER M5 ;
        RECT  37.296 69.036 37.32 69.12 ;
    END
  END cfg_data[88]
  PIN cfg_data[89]
    DIRECTION INPUT ;
    USE SIGNAL ;
    PORT
      LAYER M5 ;
        RECT  37.392 69.036 37.416 69.12 ;
    END
  END cfg_data[89]
  PIN cfg_data[8]
    DIRECTION INPUT ;
    USE SIGNAL ;
    PORT
      LAYER M5 ;
        RECT  44.976 69.036 45 69.12 ;
    END
  END cfg_data[8]
  PIN cfg_data[90]
    DIRECTION INPUT ;
    USE SIGNAL ;
    PORT
      LAYER M5 ;
        RECT  37.488 69.036 37.512 69.12 ;
    END
  END cfg_data[90]
  PIN cfg_data[91]
    DIRECTION INPUT ;
    USE SIGNAL ;
    PORT
      LAYER M5 ;
        RECT  37.584 69.036 37.608 69.12 ;
    END
  END cfg_data[91]
  PIN cfg_data[92]
    DIRECTION INPUT ;
    USE SIGNAL ;
    PORT
      LAYER M5 ;
        RECT  37.68 69.036 37.704 69.12 ;
    END
  END cfg_data[92]
  PIN cfg_data[93]
    DIRECTION INPUT ;
    USE SIGNAL ;
    PORT
      LAYER M5 ;
        RECT  37.776 69.036 37.8 69.12 ;
    END
  END cfg_data[93]
  PIN cfg_data[94]
    DIRECTION INPUT ;
    USE SIGNAL ;
    PORT
      LAYER M5 ;
        RECT  37.872 69.036 37.896 69.12 ;
    END
  END cfg_data[94]
  PIN cfg_data[95]
    DIRECTION INPUT ;
    USE SIGNAL ;
    PORT
      LAYER M5 ;
        RECT  37.968 69.036 37.992 69.12 ;
    END
  END cfg_data[95]
  PIN cfg_data[96]
    DIRECTION INPUT ;
    USE SIGNAL ;
    PORT
      LAYER M5 ;
        RECT  38.064 69.036 38.088 69.12 ;
    END
  END cfg_data[96]
  PIN cfg_data[97]
    DIRECTION INPUT ;
    USE SIGNAL ;
    PORT
      LAYER M5 ;
        RECT  38.16 69.036 38.184 69.12 ;
    END
  END cfg_data[97]
  PIN cfg_data[98]
    DIRECTION INPUT ;
    USE SIGNAL ;
    PORT
      LAYER M5 ;
        RECT  38.256 69.036 38.28 69.12 ;
    END
  END cfg_data[98]
  PIN cfg_data[99]
    DIRECTION INPUT ;
    USE SIGNAL ;
    PORT
      LAYER M5 ;
        RECT  38.352 69.036 38.376 69.12 ;
    END
  END cfg_data[99]
  PIN cfg_data[9]
    DIRECTION INPUT ;
    USE SIGNAL ;
    PORT
      LAYER M5 ;
        RECT  45.072 69.036 45.096 69.12 ;
    END
  END cfg_data[9]
  PIN cfg_target[0]
    DIRECTION INPUT ;
    USE SIGNAL ;
    PORT
      LAYER M5 ;
        RECT  21.936 69.036 21.96 69.12 ;
    END
  END cfg_target[0]
  PIN cfg_target[1]
    DIRECTION INPUT ;
    USE SIGNAL ;
    PORT
      LAYER M5 ;
        RECT  22.032 69.036 22.056 69.12 ;
    END
  END cfg_target[1]
  PIN cfg_target[2]
    DIRECTION INPUT ;
    USE SIGNAL ;
    PORT
      LAYER M5 ;
        RECT  22.128 69.036 22.152 69.12 ;
    END
  END cfg_target[2]
  PIN cfg_target[3]
    DIRECTION INPUT ;
    USE SIGNAL ;
    PORT
      LAYER M5 ;
        RECT  22.224 69.036 22.248 69.12 ;
    END
  END cfg_target[3]
  PIN cfg_target[4]
    DIRECTION INPUT ;
    USE SIGNAL ;
    PORT
      LAYER M5 ;
        RECT  22.32 69.036 22.344 69.12 ;
    END
  END cfg_target[4]
  PIN cfg_target[5]
    DIRECTION INPUT ;
    USE SIGNAL ;
    PORT
      LAYER M5 ;
        RECT  22.416 69.036 22.44 69.12 ;
    END
  END cfg_target[5]
  PIN cfg_target[6]
    DIRECTION INPUT ;
    USE SIGNAL ;
    PORT
      LAYER M5 ;
        RECT  22.512 69.036 22.536 69.12 ;
    END
  END cfg_target[6]
  PIN cfg_target[7]
    DIRECTION INPUT ;
    USE SIGNAL ;
    PORT
      LAYER M5 ;
        RECT  22.608 69.036 22.632 69.12 ;
    END
  END cfg_target[7]
  PIN cfg_v
    DIRECTION INPUT ;
    USE SIGNAL ;
    PORT
      LAYER M5 ;
        RECT  22.704 69.036 22.728 69.12 ;
    END
  END cfg_v
  PIN clk
    DIRECTION INPUT ;
    USE SIGNAL ;
    PORT
      LAYER M5 ;
        RECT  22.8 69.036 22.824 69.12 ;
    END
  END clk
  PIN desc_base[0]
    DIRECTION INPUT ;
    USE SIGNAL ;
    PORT
      LAYER M5 ;
        RECT  22.896 69.036 22.92 69.12 ;
    END
  END desc_base[0]
  PIN desc_base[10]
    DIRECTION INPUT ;
    USE SIGNAL ;
    PORT
      LAYER M5 ;
        RECT  23.856 69.036 23.88 69.12 ;
    END
  END desc_base[10]
  PIN desc_base[11]
    DIRECTION INPUT ;
    USE SIGNAL ;
    PORT
      LAYER M5 ;
        RECT  23.952 69.036 23.976 69.12 ;
    END
  END desc_base[11]
  PIN desc_base[1]
    DIRECTION INPUT ;
    USE SIGNAL ;
    PORT
      LAYER M5 ;
        RECT  22.992 69.036 23.016 69.12 ;
    END
  END desc_base[1]
  PIN desc_base[2]
    DIRECTION INPUT ;
    USE SIGNAL ;
    PORT
      LAYER M5 ;
        RECT  23.088 69.036 23.112 69.12 ;
    END
  END desc_base[2]
  PIN desc_base[3]
    DIRECTION INPUT ;
    USE SIGNAL ;
    PORT
      LAYER M5 ;
        RECT  23.184 69.036 23.208 69.12 ;
    END
  END desc_base[3]
  PIN desc_base[4]
    DIRECTION INPUT ;
    USE SIGNAL ;
    PORT
      LAYER M5 ;
        RECT  23.28 69.036 23.304 69.12 ;
    END
  END desc_base[4]
  PIN desc_base[5]
    DIRECTION INPUT ;
    USE SIGNAL ;
    PORT
      LAYER M5 ;
        RECT  23.376 69.036 23.4 69.12 ;
    END
  END desc_base[5]
  PIN desc_base[6]
    DIRECTION INPUT ;
    USE SIGNAL ;
    PORT
      LAYER M5 ;
        RECT  23.472 69.036 23.496 69.12 ;
    END
  END desc_base[6]
  PIN desc_base[7]
    DIRECTION INPUT ;
    USE SIGNAL ;
    PORT
      LAYER M5 ;
        RECT  23.568 69.036 23.592 69.12 ;
    END
  END desc_base[7]
  PIN desc_base[8]
    DIRECTION INPUT ;
    USE SIGNAL ;
    PORT
      LAYER M5 ;
        RECT  23.664 69.036 23.688 69.12 ;
    END
  END desc_base[8]
  PIN desc_base[9]
    DIRECTION INPUT ;
    USE SIGNAL ;
    PORT
      LAYER M5 ;
        RECT  23.76 69.036 23.784 69.12 ;
    END
  END desc_base[9]
  PIN desc_limit[0]
    DIRECTION INPUT ;
    USE SIGNAL ;
    PORT
      LAYER M5 ;
        RECT  24.048 69.036 24.072 69.12 ;
    END
  END desc_limit[0]
  PIN desc_limit[10]
    DIRECTION INPUT ;
    USE SIGNAL ;
    PORT
      LAYER M5 ;
        RECT  25.008 69.036 25.032 69.12 ;
    END
  END desc_limit[10]
  PIN desc_limit[11]
    DIRECTION INPUT ;
    USE SIGNAL ;
    PORT
      LAYER M5 ;
        RECT  25.104 69.036 25.128 69.12 ;
    END
  END desc_limit[11]
  PIN desc_limit[12]
    DIRECTION INPUT ;
    USE SIGNAL ;
    PORT
      LAYER M5 ;
        RECT  25.2 69.036 25.224 69.12 ;
    END
  END desc_limit[12]
  PIN desc_limit[1]
    DIRECTION INPUT ;
    USE SIGNAL ;
    PORT
      LAYER M5 ;
        RECT  24.144 69.036 24.168 69.12 ;
    END
  END desc_limit[1]
  PIN desc_limit[2]
    DIRECTION INPUT ;
    USE SIGNAL ;
    PORT
      LAYER M5 ;
        RECT  24.24 69.036 24.264 69.12 ;
    END
  END desc_limit[2]
  PIN desc_limit[3]
    DIRECTION INPUT ;
    USE SIGNAL ;
    PORT
      LAYER M5 ;
        RECT  24.336 69.036 24.36 69.12 ;
    END
  END desc_limit[3]
  PIN desc_limit[4]
    DIRECTION INPUT ;
    USE SIGNAL ;
    PORT
      LAYER M5 ;
        RECT  24.432 69.036 24.456 69.12 ;
    END
  END desc_limit[4]
  PIN desc_limit[5]
    DIRECTION INPUT ;
    USE SIGNAL ;
    PORT
      LAYER M5 ;
        RECT  24.528 69.036 24.552 69.12 ;
    END
  END desc_limit[5]
  PIN desc_limit[6]
    DIRECTION INPUT ;
    USE SIGNAL ;
    PORT
      LAYER M5 ;
        RECT  24.624 69.036 24.648 69.12 ;
    END
  END desc_limit[6]
  PIN desc_limit[7]
    DIRECTION INPUT ;
    USE SIGNAL ;
    PORT
      LAYER M5 ;
        RECT  24.72 69.036 24.744 69.12 ;
    END
  END desc_limit[7]
  PIN desc_limit[8]
    DIRECTION INPUT ;
    USE SIGNAL ;
    PORT
      LAYER M5 ;
        RECT  24.816 69.036 24.84 69.12 ;
    END
  END desc_limit[8]
  PIN desc_limit[9]
    DIRECTION INPUT ;
    USE SIGNAL ;
    PORT
      LAYER M5 ;
        RECT  24.912 69.036 24.936 69.12 ;
    END
  END desc_limit[9]
  PIN desc_loops[0]
    DIRECTION INPUT ;
    USE SIGNAL ;
    PORT
      LAYER M5 ;
        RECT  25.296 69.036 25.32 69.12 ;
    END
  END desc_loops[0]
  PIN desc_loops[10]
    DIRECTION INPUT ;
    USE SIGNAL ;
    PORT
      LAYER M5 ;
        RECT  26.256 69.036 26.28 69.12 ;
    END
  END desc_loops[10]
  PIN desc_loops[11]
    DIRECTION INPUT ;
    USE SIGNAL ;
    PORT
      LAYER M5 ;
        RECT  26.352 69.036 26.376 69.12 ;
    END
  END desc_loops[11]
  PIN desc_loops[12]
    DIRECTION INPUT ;
    USE SIGNAL ;
    PORT
      LAYER M5 ;
        RECT  26.448 69.036 26.472 69.12 ;
    END
  END desc_loops[12]
  PIN desc_loops[13]
    DIRECTION INPUT ;
    USE SIGNAL ;
    PORT
      LAYER M5 ;
        RECT  26.544 69.036 26.568 69.12 ;
    END
  END desc_loops[13]
  PIN desc_loops[14]
    DIRECTION INPUT ;
    USE SIGNAL ;
    PORT
      LAYER M5 ;
        RECT  26.64 69.036 26.664 69.12 ;
    END
  END desc_loops[14]
  PIN desc_loops[15]
    DIRECTION INPUT ;
    USE SIGNAL ;
    PORT
      LAYER M5 ;
        RECT  26.736 69.036 26.76 69.12 ;
    END
  END desc_loops[15]
  PIN desc_loops[1]
    DIRECTION INPUT ;
    USE SIGNAL ;
    PORT
      LAYER M5 ;
        RECT  25.392 69.036 25.416 69.12 ;
    END
  END desc_loops[1]
  PIN desc_loops[2]
    DIRECTION INPUT ;
    USE SIGNAL ;
    PORT
      LAYER M5 ;
        RECT  25.488 69.036 25.512 69.12 ;
    END
  END desc_loops[2]
  PIN desc_loops[3]
    DIRECTION INPUT ;
    USE SIGNAL ;
    PORT
      LAYER M5 ;
        RECT  25.584 69.036 25.608 69.12 ;
    END
  END desc_loops[3]
  PIN desc_loops[4]
    DIRECTION INPUT ;
    USE SIGNAL ;
    PORT
      LAYER M5 ;
        RECT  25.68 69.036 25.704 69.12 ;
    END
  END desc_loops[4]
  PIN desc_loops[5]
    DIRECTION INPUT ;
    USE SIGNAL ;
    PORT
      LAYER M5 ;
        RECT  25.776 69.036 25.8 69.12 ;
    END
  END desc_loops[5]
  PIN desc_loops[6]
    DIRECTION INPUT ;
    USE SIGNAL ;
    PORT
      LAYER M5 ;
        RECT  25.872 69.036 25.896 69.12 ;
    END
  END desc_loops[6]
  PIN desc_loops[7]
    DIRECTION INPUT ;
    USE SIGNAL ;
    PORT
      LAYER M5 ;
        RECT  25.968 69.036 25.992 69.12 ;
    END
  END desc_loops[7]
  PIN desc_loops[8]
    DIRECTION INPUT ;
    USE SIGNAL ;
    PORT
      LAYER M5 ;
        RECT  26.064 69.036 26.088 69.12 ;
    END
  END desc_loops[8]
  PIN desc_loops[9]
    DIRECTION INPUT ;
    USE SIGNAL ;
    PORT
      LAYER M5 ;
        RECT  26.16 69.036 26.184 69.12 ;
    END
  END desc_loops[9]
  PIN desc_v
    DIRECTION INPUT ;
    USE SIGNAL ;
    PORT
      LAYER M5 ;
        RECT  26.832 69.036 26.856 69.12 ;
    END
  END desc_v
  PIN launch_v
    DIRECTION INPUT ;
    USE SIGNAL ;
    PORT
      LAYER M5 ;
        RECT  30.576 69.036 30.6 69.12 ;
    END
  END launch_v
  PIN rst_n
    DIRECTION INPUT ;
    USE SIGNAL ;
    PORT
      LAYER M5 ;
        RECT  30.672 69.036 30.696 69.12 ;
    END
  END rst_n
  PIN s_active[0]
    DIRECTION OUTPUT ;
    USE SIGNAL ;
    PORT
      LAYER M5 ;
        RECT  39.12 0 39.144 0.084 ;
    END
  END s_active[0]
  PIN s_active[10]
    DIRECTION OUTPUT ;
    USE SIGNAL ;
    PORT
      LAYER M5 ;
        RECT  40.08 0 40.104 0.084 ;
    END
  END s_active[10]
  PIN s_active[11]
    DIRECTION OUTPUT ;
    USE SIGNAL ;
    PORT
      LAYER M5 ;
        RECT  40.176 0 40.2 0.084 ;
    END
  END s_active[11]
  PIN s_active[12]
    DIRECTION OUTPUT ;
    USE SIGNAL ;
    PORT
      LAYER M5 ;
        RECT  40.272 0 40.296 0.084 ;
    END
  END s_active[12]
  PIN s_active[13]
    DIRECTION OUTPUT ;
    USE SIGNAL ;
    PORT
      LAYER M5 ;
        RECT  40.368 0 40.392 0.084 ;
    END
  END s_active[13]
  PIN s_active[14]
    DIRECTION OUTPUT ;
    USE SIGNAL ;
    PORT
      LAYER M5 ;
        RECT  40.464 0 40.488 0.084 ;
    END
  END s_active[14]
  PIN s_active[15]
    DIRECTION OUTPUT ;
    USE SIGNAL ;
    PORT
      LAYER M5 ;
        RECT  40.56 0 40.584 0.084 ;
    END
  END s_active[15]
  PIN s_active[16]
    DIRECTION OUTPUT ;
    USE SIGNAL ;
    PORT
      LAYER M5 ;
        RECT  40.656 0 40.68 0.084 ;
    END
  END s_active[16]
  PIN s_active[17]
    DIRECTION OUTPUT ;
    USE SIGNAL ;
    PORT
      LAYER M5 ;
        RECT  40.752 0 40.776 0.084 ;
    END
  END s_active[17]
  PIN s_active[1]
    DIRECTION OUTPUT ;
    USE SIGNAL ;
    PORT
      LAYER M5 ;
        RECT  39.216 0 39.24 0.084 ;
    END
  END s_active[1]
  PIN s_active[2]
    DIRECTION OUTPUT ;
    USE SIGNAL ;
    PORT
      LAYER M5 ;
        RECT  39.312 0 39.336 0.084 ;
    END
  END s_active[2]
  PIN s_active[3]
    DIRECTION OUTPUT ;
    USE SIGNAL ;
    PORT
      LAYER M5 ;
        RECT  39.408 0 39.432 0.084 ;
    END
  END s_active[3]
  PIN s_active[4]
    DIRECTION OUTPUT ;
    USE SIGNAL ;
    PORT
      LAYER M5 ;
        RECT  39.504 0 39.528 0.084 ;
    END
  END s_active[4]
  PIN s_active[5]
    DIRECTION OUTPUT ;
    USE SIGNAL ;
    PORT
      LAYER M5 ;
        RECT  39.6 0 39.624 0.084 ;
    END
  END s_active[5]
  PIN s_active[6]
    DIRECTION OUTPUT ;
    USE SIGNAL ;
    PORT
      LAYER M5 ;
        RECT  39.696 0 39.72 0.084 ;
    END
  END s_active[6]
  PIN s_active[7]
    DIRECTION OUTPUT ;
    USE SIGNAL ;
    PORT
      LAYER M5 ;
        RECT  39.792 0 39.816 0.084 ;
    END
  END s_active[7]
  PIN s_active[8]
    DIRECTION OUTPUT ;
    USE SIGNAL ;
    PORT
      LAYER M5 ;
        RECT  39.888 0 39.912 0.084 ;
    END
  END s_active[8]
  PIN s_active[9]
    DIRECTION OUTPUT ;
    USE SIGNAL ;
    PORT
      LAYER M5 ;
        RECT  39.984 0 40.008 0.084 ;
    END
  END s_active[9]
  PIN s_fault[0]
    DIRECTION OUTPUT ;
    USE SIGNAL ;
    PORT
      LAYER M5 ;
        RECT  40.848 0 40.872 0.084 ;
    END
  END s_fault[0]
  PIN s_fault[10]
    DIRECTION OUTPUT ;
    USE SIGNAL ;
    PORT
      LAYER M5 ;
        RECT  41.808 0 41.832 0.084 ;
    END
  END s_fault[10]
  PIN s_fault[11]
    DIRECTION OUTPUT ;
    USE SIGNAL ;
    PORT
      LAYER M5 ;
        RECT  41.904 0 41.928 0.084 ;
    END
  END s_fault[11]
  PIN s_fault[12]
    DIRECTION OUTPUT ;
    USE SIGNAL ;
    PORT
      LAYER M5 ;
        RECT  42 0 42.024 0.084 ;
    END
  END s_fault[12]
  PIN s_fault[13]
    DIRECTION OUTPUT ;
    USE SIGNAL ;
    PORT
      LAYER M5 ;
        RECT  42.096 0 42.12 0.084 ;
    END
  END s_fault[13]
  PIN s_fault[14]
    DIRECTION OUTPUT ;
    USE SIGNAL ;
    PORT
      LAYER M5 ;
        RECT  42.192 0 42.216 0.084 ;
    END
  END s_fault[14]
  PIN s_fault[15]
    DIRECTION OUTPUT ;
    USE SIGNAL ;
    PORT
      LAYER M5 ;
        RECT  42.288 0 42.312 0.084 ;
    END
  END s_fault[15]
  PIN s_fault[16]
    DIRECTION OUTPUT ;
    USE SIGNAL ;
    PORT
      LAYER M5 ;
        RECT  42.384 0 42.408 0.084 ;
    END
  END s_fault[16]
  PIN s_fault[17]
    DIRECTION OUTPUT ;
    USE SIGNAL ;
    PORT
      LAYER M5 ;
        RECT  42.48 0 42.504 0.084 ;
    END
  END s_fault[17]
  PIN s_fault[18]
    DIRECTION OUTPUT ;
    USE SIGNAL ;
    PORT
      LAYER M5 ;
        RECT  42.576 0 42.6 0.084 ;
    END
  END s_fault[18]
  PIN s_fault[19]
    DIRECTION OUTPUT ;
    USE SIGNAL ;
    PORT
      LAYER M5 ;
        RECT  42.672 0 42.696 0.084 ;
    END
  END s_fault[19]
  PIN s_fault[1]
    DIRECTION OUTPUT ;
    USE SIGNAL ;
    PORT
      LAYER M5 ;
        RECT  40.944 0 40.968 0.084 ;
    END
  END s_fault[1]
  PIN s_fault[20]
    DIRECTION OUTPUT ;
    USE SIGNAL ;
    PORT
      LAYER M5 ;
        RECT  42.768 0 42.792 0.084 ;
    END
  END s_fault[20]
  PIN s_fault[21]
    DIRECTION OUTPUT ;
    USE SIGNAL ;
    PORT
      LAYER M5 ;
        RECT  42.864 0 42.888 0.084 ;
    END
  END s_fault[21]
  PIN s_fault[22]
    DIRECTION OUTPUT ;
    USE SIGNAL ;
    PORT
      LAYER M5 ;
        RECT  42.96 0 42.984 0.084 ;
    END
  END s_fault[22]
  PIN s_fault[23]
    DIRECTION OUTPUT ;
    USE SIGNAL ;
    PORT
      LAYER M5 ;
        RECT  43.056 0 43.08 0.084 ;
    END
  END s_fault[23]
  PIN s_fault[24]
    DIRECTION OUTPUT ;
    USE SIGNAL ;
    PORT
      LAYER M5 ;
        RECT  43.152 0 43.176 0.084 ;
    END
  END s_fault[24]
  PIN s_fault[25]
    DIRECTION OUTPUT ;
    USE SIGNAL ;
    PORT
      LAYER M5 ;
        RECT  43.248 0 43.272 0.084 ;
    END
  END s_fault[25]
  PIN s_fault[26]
    DIRECTION OUTPUT ;
    USE SIGNAL ;
    PORT
      LAYER M5 ;
        RECT  43.344 0 43.368 0.084 ;
    END
  END s_fault[26]
  PIN s_fault[27]
    DIRECTION OUTPUT ;
    USE SIGNAL ;
    PORT
      LAYER M5 ;
        RECT  43.44 0 43.464 0.084 ;
    END
  END s_fault[27]
  PIN s_fault[28]
    DIRECTION OUTPUT ;
    USE SIGNAL ;
    PORT
      LAYER M5 ;
        RECT  43.536 0 43.56 0.084 ;
    END
  END s_fault[28]
  PIN s_fault[2]
    DIRECTION OUTPUT ;
    USE SIGNAL ;
    PORT
      LAYER M5 ;
        RECT  41.04 0 41.064 0.084 ;
    END
  END s_fault[2]
  PIN s_fault[3]
    DIRECTION OUTPUT ;
    USE SIGNAL ;
    PORT
      LAYER M5 ;
        RECT  41.136 0 41.16 0.084 ;
    END
  END s_fault[3]
  PIN s_fault[4]
    DIRECTION OUTPUT ;
    USE SIGNAL ;
    PORT
      LAYER M5 ;
        RECT  41.232 0 41.256 0.084 ;
    END
  END s_fault[4]
  PIN s_fault[5]
    DIRECTION OUTPUT ;
    USE SIGNAL ;
    PORT
      LAYER M5 ;
        RECT  41.328 0 41.352 0.084 ;
    END
  END s_fault[5]
  PIN s_fault[6]
    DIRECTION OUTPUT ;
    USE SIGNAL ;
    PORT
      LAYER M5 ;
        RECT  41.424 0 41.448 0.084 ;
    END
  END s_fault[6]
  PIN s_fault[7]
    DIRECTION OUTPUT ;
    USE SIGNAL ;
    PORT
      LAYER M5 ;
        RECT  41.52 0 41.544 0.084 ;
    END
  END s_fault[7]
  PIN s_fault[8]
    DIRECTION OUTPUT ;
    USE SIGNAL ;
    PORT
      LAYER M5 ;
        RECT  41.616 0 41.64 0.084 ;
    END
  END s_fault[8]
  PIN s_fault[9]
    DIRECTION OUTPUT ;
    USE SIGNAL ;
    PORT
      LAYER M5 ;
        RECT  41.712 0 41.736 0.084 ;
    END
  END s_fault[9]
  PIN s_ready[0]
    DIRECTION OUTPUT ;
    USE SIGNAL ;
    PORT
      LAYER M5 ;
        RECT  43.632 0 43.656 0.084 ;
    END
  END s_ready[0]
  PIN s_ready[10]
    DIRECTION OUTPUT ;
    USE SIGNAL ;
    PORT
      LAYER M5 ;
        RECT  44.592 0 44.616 0.084 ;
    END
  END s_ready[10]
  PIN s_ready[11]
    DIRECTION OUTPUT ;
    USE SIGNAL ;
    PORT
      LAYER M5 ;
        RECT  44.688 0 44.712 0.084 ;
    END
  END s_ready[11]
  PIN s_ready[12]
    DIRECTION OUTPUT ;
    USE SIGNAL ;
    PORT
      LAYER M5 ;
        RECT  44.784 0 44.808 0.084 ;
    END
  END s_ready[12]
  PIN s_ready[13]
    DIRECTION OUTPUT ;
    USE SIGNAL ;
    PORT
      LAYER M5 ;
        RECT  44.88 0 44.904 0.084 ;
    END
  END s_ready[13]
  PIN s_ready[14]
    DIRECTION OUTPUT ;
    USE SIGNAL ;
    PORT
      LAYER M5 ;
        RECT  44.976 0 45 0.084 ;
    END
  END s_ready[14]
  PIN s_ready[15]
    DIRECTION OUTPUT ;
    USE SIGNAL ;
    PORT
      LAYER M5 ;
        RECT  45.072 0 45.096 0.084 ;
    END
  END s_ready[15]
  PIN s_ready[16]
    DIRECTION OUTPUT ;
    USE SIGNAL ;
    PORT
      LAYER M5 ;
        RECT  45.168 0 45.192 0.084 ;
    END
  END s_ready[16]
  PIN s_ready[17]
    DIRECTION OUTPUT ;
    USE SIGNAL ;
    PORT
      LAYER M5 ;
        RECT  32.208 0 32.232 0.084 ;
    END
  END s_ready[17]
  PIN s_ready[1]
    DIRECTION OUTPUT ;
    USE SIGNAL ;
    PORT
      LAYER M5 ;
        RECT  43.728 0 43.752 0.084 ;
    END
  END s_ready[1]
  PIN s_ready[2]
    DIRECTION OUTPUT ;
    USE SIGNAL ;
    PORT
      LAYER M5 ;
        RECT  43.824 0 43.848 0.084 ;
    END
  END s_ready[2]
  PIN s_ready[3]
    DIRECTION OUTPUT ;
    USE SIGNAL ;
    PORT
      LAYER M5 ;
        RECT  43.92 0 43.944 0.084 ;
    END
  END s_ready[3]
  PIN s_ready[4]
    DIRECTION OUTPUT ;
    USE SIGNAL ;
    PORT
      LAYER M5 ;
        RECT  44.016 0 44.04 0.084 ;
    END
  END s_ready[4]
  PIN s_ready[5]
    DIRECTION OUTPUT ;
    USE SIGNAL ;
    PORT
      LAYER M5 ;
        RECT  44.112 0 44.136 0.084 ;
    END
  END s_ready[5]
  PIN s_ready[6]
    DIRECTION OUTPUT ;
    USE SIGNAL ;
    PORT
      LAYER M5 ;
        RECT  44.208 0 44.232 0.084 ;
    END
  END s_ready[6]
  PIN s_ready[7]
    DIRECTION OUTPUT ;
    USE SIGNAL ;
    PORT
      LAYER M5 ;
        RECT  44.304 0 44.328 0.084 ;
    END
  END s_ready[7]
  PIN s_ready[8]
    DIRECTION OUTPUT ;
    USE SIGNAL ;
    PORT
      LAYER M5 ;
        RECT  44.4 0 44.424 0.084 ;
    END
  END s_ready[8]
  PIN s_ready[9]
    DIRECTION OUTPUT ;
    USE SIGNAL ;
    PORT
      LAYER M5 ;
        RECT  44.496 0 44.52 0.084 ;
    END
  END s_ready[9]
  PIN t_active[0]
    DIRECTION INPUT ;
    USE SIGNAL ;
    PORT
      LAYER M5 ;
        RECT  32.304 0 32.328 0.084 ;
    END
  END t_active[0]
  PIN t_active[10]
    DIRECTION INPUT ;
    USE SIGNAL ;
    PORT
      LAYER M5 ;
        RECT  33.264 0 33.288 0.084 ;
    END
  END t_active[10]
  PIN t_active[11]
    DIRECTION INPUT ;
    USE SIGNAL ;
    PORT
      LAYER M5 ;
        RECT  33.36 0 33.384 0.084 ;
    END
  END t_active[11]
  PIN t_active[12]
    DIRECTION INPUT ;
    USE SIGNAL ;
    PORT
      LAYER M5 ;
        RECT  33.456 0 33.48 0.084 ;
    END
  END t_active[12]
  PIN t_active[13]
    DIRECTION INPUT ;
    USE SIGNAL ;
    PORT
      LAYER M5 ;
        RECT  33.552 0 33.576 0.084 ;
    END
  END t_active[13]
  PIN t_active[14]
    DIRECTION INPUT ;
    USE SIGNAL ;
    PORT
      LAYER M5 ;
        RECT  33.648 0 33.672 0.084 ;
    END
  END t_active[14]
  PIN t_active[15]
    DIRECTION INPUT ;
    USE SIGNAL ;
    PORT
      LAYER M5 ;
        RECT  33.744 0 33.768 0.084 ;
    END
  END t_active[15]
  PIN t_active[16]
    DIRECTION INPUT ;
    USE SIGNAL ;
    PORT
      LAYER M5 ;
        RECT  33.84 0 33.864 0.084 ;
    END
  END t_active[16]
  PIN t_active[17]
    DIRECTION INPUT ;
    USE SIGNAL ;
    PORT
      LAYER M5 ;
        RECT  33.936 0 33.96 0.084 ;
    END
  END t_active[17]
  PIN t_active[1]
    DIRECTION INPUT ;
    USE SIGNAL ;
    PORT
      LAYER M5 ;
        RECT  32.4 0 32.424 0.084 ;
    END
  END t_active[1]
  PIN t_active[2]
    DIRECTION INPUT ;
    USE SIGNAL ;
    PORT
      LAYER M5 ;
        RECT  32.496 0 32.52 0.084 ;
    END
  END t_active[2]
  PIN t_active[3]
    DIRECTION INPUT ;
    USE SIGNAL ;
    PORT
      LAYER M5 ;
        RECT  32.592 0 32.616 0.084 ;
    END
  END t_active[3]
  PIN t_active[4]
    DIRECTION INPUT ;
    USE SIGNAL ;
    PORT
      LAYER M5 ;
        RECT  32.688 0 32.712 0.084 ;
    END
  END t_active[4]
  PIN t_active[5]
    DIRECTION INPUT ;
    USE SIGNAL ;
    PORT
      LAYER M5 ;
        RECT  32.784 0 32.808 0.084 ;
    END
  END t_active[5]
  PIN t_active[6]
    DIRECTION INPUT ;
    USE SIGNAL ;
    PORT
      LAYER M5 ;
        RECT  32.88 0 32.904 0.084 ;
    END
  END t_active[6]
  PIN t_active[7]
    DIRECTION INPUT ;
    USE SIGNAL ;
    PORT
      LAYER M5 ;
        RECT  32.976 0 33 0.084 ;
    END
  END t_active[7]
  PIN t_active[8]
    DIRECTION INPUT ;
    USE SIGNAL ;
    PORT
      LAYER M5 ;
        RECT  33.072 0 33.096 0.084 ;
    END
  END t_active[8]
  PIN t_active[9]
    DIRECTION INPUT ;
    USE SIGNAL ;
    PORT
      LAYER M5 ;
        RECT  33.168 0 33.192 0.084 ;
    END
  END t_active[9]
  PIN t_fault[0]
    DIRECTION INPUT ;
    USE SIGNAL ;
    PORT
      LAYER M5 ;
        RECT  34.032 0 34.056 0.084 ;
    END
  END t_fault[0]
  PIN t_fault[10]
    DIRECTION INPUT ;
    USE SIGNAL ;
    PORT
      LAYER M5 ;
        RECT  34.992 0 35.016 0.084 ;
    END
  END t_fault[10]
  PIN t_fault[11]
    DIRECTION INPUT ;
    USE SIGNAL ;
    PORT
      LAYER M5 ;
        RECT  35.088 0 35.112 0.084 ;
    END
  END t_fault[11]
  PIN t_fault[12]
    DIRECTION INPUT ;
    USE SIGNAL ;
    PORT
      LAYER M5 ;
        RECT  35.184 0 35.208 0.084 ;
    END
  END t_fault[12]
  PIN t_fault[13]
    DIRECTION INPUT ;
    USE SIGNAL ;
    PORT
      LAYER M5 ;
        RECT  35.28 0 35.304 0.084 ;
    END
  END t_fault[13]
  PIN t_fault[14]
    DIRECTION INPUT ;
    USE SIGNAL ;
    PORT
      LAYER M5 ;
        RECT  35.376 0 35.4 0.084 ;
    END
  END t_fault[14]
  PIN t_fault[15]
    DIRECTION INPUT ;
    USE SIGNAL ;
    PORT
      LAYER M5 ;
        RECT  35.472 0 35.496 0.084 ;
    END
  END t_fault[15]
  PIN t_fault[16]
    DIRECTION INPUT ;
    USE SIGNAL ;
    PORT
      LAYER M5 ;
        RECT  35.568 0 35.592 0.084 ;
    END
  END t_fault[16]
  PIN t_fault[17]
    DIRECTION INPUT ;
    USE SIGNAL ;
    PORT
      LAYER M5 ;
        RECT  35.664 0 35.688 0.084 ;
    END
  END t_fault[17]
  PIN t_fault[18]
    DIRECTION INPUT ;
    USE SIGNAL ;
    PORT
      LAYER M5 ;
        RECT  35.76 0 35.784 0.084 ;
    END
  END t_fault[18]
  PIN t_fault[19]
    DIRECTION INPUT ;
    USE SIGNAL ;
    PORT
      LAYER M5 ;
        RECT  35.856 0 35.88 0.084 ;
    END
  END t_fault[19]
  PIN t_fault[1]
    DIRECTION INPUT ;
    USE SIGNAL ;
    PORT
      LAYER M5 ;
        RECT  34.128 0 34.152 0.084 ;
    END
  END t_fault[1]
  PIN t_fault[20]
    DIRECTION INPUT ;
    USE SIGNAL ;
    PORT
      LAYER M5 ;
        RECT  35.952 0 35.976 0.084 ;
    END
  END t_fault[20]
  PIN t_fault[21]
    DIRECTION INPUT ;
    USE SIGNAL ;
    PORT
      LAYER M5 ;
        RECT  36.048 0 36.072 0.084 ;
    END
  END t_fault[21]
  PIN t_fault[22]
    DIRECTION INPUT ;
    USE SIGNAL ;
    PORT
      LAYER M5 ;
        RECT  36.144 0 36.168 0.084 ;
    END
  END t_fault[22]
  PIN t_fault[23]
    DIRECTION INPUT ;
    USE SIGNAL ;
    PORT
      LAYER M5 ;
        RECT  36.24 0 36.264 0.084 ;
    END
  END t_fault[23]
  PIN t_fault[24]
    DIRECTION INPUT ;
    USE SIGNAL ;
    PORT
      LAYER M5 ;
        RECT  36.336 0 36.36 0.084 ;
    END
  END t_fault[24]
  PIN t_fault[25]
    DIRECTION INPUT ;
    USE SIGNAL ;
    PORT
      LAYER M5 ;
        RECT  36.432 0 36.456 0.084 ;
    END
  END t_fault[25]
  PIN t_fault[26]
    DIRECTION INPUT ;
    USE SIGNAL ;
    PORT
      LAYER M5 ;
        RECT  36.528 0 36.552 0.084 ;
    END
  END t_fault[26]
  PIN t_fault[27]
    DIRECTION INPUT ;
    USE SIGNAL ;
    PORT
      LAYER M5 ;
        RECT  36.624 0 36.648 0.084 ;
    END
  END t_fault[27]
  PIN t_fault[28]
    DIRECTION INPUT ;
    USE SIGNAL ;
    PORT
      LAYER M5 ;
        RECT  36.72 0 36.744 0.084 ;
    END
  END t_fault[28]
  PIN t_fault[2]
    DIRECTION INPUT ;
    USE SIGNAL ;
    PORT
      LAYER M5 ;
        RECT  34.224 0 34.248 0.084 ;
    END
  END t_fault[2]
  PIN t_fault[3]
    DIRECTION INPUT ;
    USE SIGNAL ;
    PORT
      LAYER M5 ;
        RECT  34.32 0 34.344 0.084 ;
    END
  END t_fault[3]
  PIN t_fault[4]
    DIRECTION INPUT ;
    USE SIGNAL ;
    PORT
      LAYER M5 ;
        RECT  34.416 0 34.44 0.084 ;
    END
  END t_fault[4]
  PIN t_fault[5]
    DIRECTION INPUT ;
    USE SIGNAL ;
    PORT
      LAYER M5 ;
        RECT  34.512 0 34.536 0.084 ;
    END
  END t_fault[5]
  PIN t_fault[6]
    DIRECTION INPUT ;
    USE SIGNAL ;
    PORT
      LAYER M5 ;
        RECT  34.608 0 34.632 0.084 ;
    END
  END t_fault[6]
  PIN t_fault[7]
    DIRECTION INPUT ;
    USE SIGNAL ;
    PORT
      LAYER M5 ;
        RECT  34.704 0 34.728 0.084 ;
    END
  END t_fault[7]
  PIN t_fault[8]
    DIRECTION INPUT ;
    USE SIGNAL ;
    PORT
      LAYER M5 ;
        RECT  34.8 0 34.824 0.084 ;
    END
  END t_fault[8]
  PIN t_fault[9]
    DIRECTION INPUT ;
    USE SIGNAL ;
    PORT
      LAYER M5 ;
        RECT  34.896 0 34.92 0.084 ;
    END
  END t_fault[9]
  PIN t_ready[0]
    DIRECTION INPUT ;
    USE SIGNAL ;
    PORT
      LAYER M5 ;
        RECT  36.816 0 36.84 0.084 ;
    END
  END t_ready[0]
  PIN t_ready[10]
    DIRECTION INPUT ;
    USE SIGNAL ;
    PORT
      LAYER M5 ;
        RECT  37.776 0 37.8 0.084 ;
    END
  END t_ready[10]
  PIN t_ready[11]
    DIRECTION INPUT ;
    USE SIGNAL ;
    PORT
      LAYER M5 ;
        RECT  37.872 0 37.896 0.084 ;
    END
  END t_ready[11]
  PIN t_ready[12]
    DIRECTION INPUT ;
    USE SIGNAL ;
    PORT
      LAYER M5 ;
        RECT  37.968 0 37.992 0.084 ;
    END
  END t_ready[12]
  PIN t_ready[13]
    DIRECTION INPUT ;
    USE SIGNAL ;
    PORT
      LAYER M5 ;
        RECT  38.064 0 38.088 0.084 ;
    END
  END t_ready[13]
  PIN t_ready[14]
    DIRECTION INPUT ;
    USE SIGNAL ;
    PORT
      LAYER M5 ;
        RECT  38.16 0 38.184 0.084 ;
    END
  END t_ready[14]
  PIN t_ready[15]
    DIRECTION INPUT ;
    USE SIGNAL ;
    PORT
      LAYER M5 ;
        RECT  38.256 0 38.28 0.084 ;
    END
  END t_ready[15]
  PIN t_ready[16]
    DIRECTION INPUT ;
    USE SIGNAL ;
    PORT
      LAYER M5 ;
        RECT  38.352 0 38.376 0.084 ;
    END
  END t_ready[16]
  PIN t_ready[17]
    DIRECTION INPUT ;
    USE SIGNAL ;
    PORT
      LAYER M5 ;
        RECT  38.448 0 38.472 0.084 ;
    END
  END t_ready[17]
  PIN t_ready[1]
    DIRECTION INPUT ;
    USE SIGNAL ;
    PORT
      LAYER M5 ;
        RECT  36.912 0 36.936 0.084 ;
    END
  END t_ready[1]
  PIN t_ready[2]
    DIRECTION INPUT ;
    USE SIGNAL ;
    PORT
      LAYER M5 ;
        RECT  37.008 0 37.032 0.084 ;
    END
  END t_ready[2]
  PIN t_ready[3]
    DIRECTION INPUT ;
    USE SIGNAL ;
    PORT
      LAYER M5 ;
        RECT  37.104 0 37.128 0.084 ;
    END
  END t_ready[3]
  PIN t_ready[4]
    DIRECTION INPUT ;
    USE SIGNAL ;
    PORT
      LAYER M5 ;
        RECT  37.2 0 37.224 0.084 ;
    END
  END t_ready[4]
  PIN t_ready[5]
    DIRECTION INPUT ;
    USE SIGNAL ;
    PORT
      LAYER M5 ;
        RECT  37.296 0 37.32 0.084 ;
    END
  END t_ready[5]
  PIN t_ready[6]
    DIRECTION INPUT ;
    USE SIGNAL ;
    PORT
      LAYER M5 ;
        RECT  37.392 0 37.416 0.084 ;
    END
  END t_ready[6]
  PIN t_ready[7]
    DIRECTION INPUT ;
    USE SIGNAL ;
    PORT
      LAYER M5 ;
        RECT  37.488 0 37.512 0.084 ;
    END
  END t_ready[7]
  PIN t_ready[8]
    DIRECTION INPUT ;
    USE SIGNAL ;
    PORT
      LAYER M5 ;
        RECT  37.584 0 37.608 0.084 ;
    END
  END t_ready[8]
  PIN t_ready[9]
    DIRECTION INPUT ;
    USE SIGNAL ;
    PORT
      LAYER M5 ;
        RECT  37.68 0 37.704 0.084 ;
    END
  END t_ready[9]
  PIN VDD
    DIRECTION INOUT ;
    USE POWER ;
    PORT
      LAYER M5 ;
        RECT  61.992 2.151 62.112 66.969 ;
        RECT  56.592 2.151 56.712 66.969 ;
        RECT  51.192 2.151 51.312 66.969 ;
        RECT  45.792 2.151 45.912 66.969 ;
        RECT  40.392 2.151 40.512 66.969 ;
        RECT  34.992 2.151 35.112 66.969 ;
        RECT  29.592 2.151 29.712 66.969 ;
        RECT  24.192 2.151 24.312 66.969 ;
        RECT  18.792 2.151 18.912 66.969 ;
        RECT  13.392 2.151 13.512 66.969 ;
        RECT  7.992 2.151 8.112 66.969 ;
        RECT  2.592 2.151 2.712 66.969 ;
    END
  END VDD
  PIN VSS
    DIRECTION INOUT ;
    USE GROUND ;
    PORT
      LAYER M5 ;
        RECT  61.8 2.137 61.92 66.983 ;
        RECT  56.4 2.137 56.52 66.983 ;
        RECT  51 2.137 51.12 66.983 ;
        RECT  45.6 2.137 45.72 66.983 ;
        RECT  40.2 2.137 40.32 66.983 ;
        RECT  34.8 2.137 34.92 66.983 ;
        RECT  29.4 2.137 29.52 66.983 ;
        RECT  24 2.137 24.12 66.983 ;
        RECT  18.6 2.137 18.72 66.983 ;
        RECT  13.2 2.137 13.32 66.983 ;
        RECT  7.8 2.137 7.92 66.983 ;
        RECT  2.4 2.137 2.52 66.983 ;
    END
  END VSS
  OBS
    LAYER RVTN ;
     RECT  2.16 2.16 66.96 2.295 ;
     RECT  2.16 2.565 66.96 2.835 ;
     RECT  2.16 3.105 66.96 3.375 ;
     RECT  2.16 3.645 66.96 3.915 ;
     RECT  2.16 4.185 66.96 4.455 ;
     RECT  2.16 4.725 66.96 4.995 ;
     RECT  2.16 5.265 66.96 5.535 ;
     RECT  2.16 5.805 66.96 6.075 ;
     RECT  2.16 6.345 66.96 6.615 ;
     RECT  2.16 6.885 66.96 7.155 ;
     RECT  2.16 7.425 66.96 7.695 ;
     RECT  2.16 7.965 66.96 8.235 ;
     RECT  2.16 8.505 66.96 8.775 ;
     RECT  2.16 9.045 66.96 9.315 ;
     RECT  2.16 9.585 66.96 9.855 ;
     RECT  2.16 10.125 66.96 10.395 ;
     RECT  2.16 10.665 66.96 10.935 ;
     RECT  2.16 11.205 66.96 11.475 ;
     RECT  2.16 11.745 66.96 12.015 ;
     RECT  2.16 12.285 66.96 12.555 ;
     RECT  2.16 12.825 66.96 13.095 ;
     RECT  2.16 13.365 66.96 13.635 ;
     RECT  2.16 13.905 66.96 14.175 ;
     RECT  2.16 14.445 66.96 14.715 ;
     RECT  2.16 14.985 66.96 15.255 ;
     RECT  2.16 15.525 66.96 15.795 ;
     RECT  2.16 16.065 66.96 16.335 ;
     RECT  2.16 16.605 66.96 16.875 ;
     RECT  2.16 17.145 66.96 17.415 ;
     RECT  2.16 17.685 66.96 17.955 ;
     RECT  2.16 18.225 66.96 18.495 ;
     RECT  2.16 18.765 66.96 19.035 ;
     RECT  2.16 19.305 66.96 19.575 ;
     RECT  2.16 19.845 66.96 20.115 ;
     RECT  2.16 20.385 66.96 20.655 ;
     RECT  2.16 20.925 66.96 21.195 ;
     RECT  2.16 21.465 66.96 21.735 ;
     RECT  2.16 22.005 66.96 22.275 ;
     RECT  2.16 22.545 66.96 22.815 ;
     RECT  2.16 23.085 66.96 23.355 ;
     RECT  2.16 23.625 66.96 23.895 ;
     RECT  2.16 24.165 66.96 24.435 ;
     RECT  2.16 24.705 66.96 24.975 ;
     RECT  2.16 25.245 66.96 25.515 ;
     RECT  2.16 25.785 66.96 26.055 ;
     RECT  2.16 26.325 66.96 26.595 ;
     RECT  2.16 26.865 66.96 27.135 ;
     RECT  2.16 27.405 66.96 27.675 ;
     RECT  2.16 27.945 66.96 28.215 ;
     RECT  2.16 28.485 66.96 28.755 ;
     RECT  2.16 29.025 66.96 29.295 ;
     RECT  2.16 29.565 66.96 29.835 ;
     RECT  2.16 30.105 66.96 30.375 ;
     RECT  2.16 30.645 66.96 30.915 ;
     RECT  2.16 31.185 66.96 31.455 ;
     RECT  2.16 31.725 66.96 31.995 ;
     RECT  2.16 32.265 66.96 32.535 ;
     RECT  2.16 32.805 66.96 33.075 ;
     RECT  2.16 33.345 66.96 33.615 ;
     RECT  2.16 33.885 66.96 34.155 ;
     RECT  2.16 34.425 66.96 34.695 ;
     RECT  2.16 34.965 66.96 35.235 ;
     RECT  2.16 35.505 66.96 35.775 ;
     RECT  2.16 36.045 66.96 36.315 ;
     RECT  2.16 36.585 66.96 36.855 ;
     RECT  2.16 37.125 66.96 37.395 ;
     RECT  2.16 37.665 66.96 37.935 ;
     RECT  2.16 38.205 66.96 38.475 ;
     RECT  2.16 38.745 66.96 39.015 ;
     RECT  2.16 39.285 66.96 39.555 ;
     RECT  2.16 39.825 66.96 40.095 ;
     RECT  2.16 40.365 66.96 40.635 ;
     RECT  2.16 40.905 66.96 41.175 ;
     RECT  2.16 41.445 66.96 41.715 ;
     RECT  2.16 41.985 66.96 42.255 ;
     RECT  2.16 42.525 66.96 42.795 ;
     RECT  2.16 43.065 66.96 43.335 ;
     RECT  2.16 43.605 66.96 43.875 ;
     RECT  2.16 44.145 66.96 44.415 ;
     RECT  2.16 44.685 66.96 44.955 ;
     RECT  2.16 45.225 66.96 45.495 ;
     RECT  2.16 45.765 66.96 46.035 ;
     RECT  2.16 46.305 66.96 46.575 ;
     RECT  2.16 46.845 66.96 47.115 ;
     RECT  2.16 47.385 66.96 47.655 ;
     RECT  2.16 47.925 66.96 48.195 ;
     RECT  2.16 48.465 66.96 48.735 ;
     RECT  2.16 49.005 66.96 49.275 ;
     RECT  2.16 49.545 66.96 49.815 ;
     RECT  2.16 50.085 66.96 50.355 ;
     RECT  2.16 50.625 66.96 50.895 ;
     RECT  2.16 51.165 66.96 51.435 ;
     RECT  2.16 51.705 66.96 51.975 ;
     RECT  2.16 52.245 66.96 52.515 ;
     RECT  2.16 52.785 66.96 53.055 ;
     RECT  2.16 53.325 66.96 53.595 ;
     RECT  2.16 53.865 66.96 54.135 ;
     RECT  2.16 54.405 66.96 54.675 ;
     RECT  2.16 54.945 66.96 55.215 ;
     RECT  2.16 55.485 66.96 55.755 ;
     RECT  2.16 56.025 66.96 56.295 ;
     RECT  2.16 56.565 66.96 56.835 ;
     RECT  2.16 57.105 66.96 57.375 ;
     RECT  2.16 57.645 66.96 57.915 ;
     RECT  2.16 58.185 66.96 58.455 ;
     RECT  2.16 58.725 66.96 58.995 ;
     RECT  2.16 59.265 66.96 59.535 ;
     RECT  2.16 59.805 66.96 60.075 ;
     RECT  2.16 60.345 66.96 60.615 ;
     RECT  2.16 60.885 66.96 61.155 ;
     RECT  2.16 61.425 66.96 61.695 ;
     RECT  2.16 61.965 66.96 62.235 ;
     RECT  2.16 62.505 66.96 62.775 ;
     RECT  2.16 63.045 66.96 63.315 ;
     RECT  2.16 63.585 66.96 63.855 ;
     RECT  2.16 64.125 66.96 64.395 ;
     RECT  2.16 64.665 66.96 64.935 ;
     RECT  2.16 65.205 66.96 65.475 ;
     RECT  2.16 65.745 66.96 66.015 ;
     RECT  2.16 66.285 66.96 66.555 ;
     RECT  2.16 66.825 66.96 66.96 ;
    LAYER RVTP ;
     RECT  2.16 2.295 66.96 2.565 ;
     RECT  2.16 2.835 66.96 3.105 ;
     RECT  2.16 3.375 66.96 3.645 ;
     RECT  2.16 3.915 66.96 4.185 ;
     RECT  2.16 4.455 66.96 4.725 ;
     RECT  2.16 4.995 66.96 5.265 ;
     RECT  2.16 5.535 66.96 5.805 ;
     RECT  2.16 6.075 66.96 6.345 ;
     RECT  2.16 6.615 66.96 6.885 ;
     RECT  2.16 7.155 66.96 7.425 ;
     RECT  2.16 7.695 66.96 7.965 ;
     RECT  2.16 8.235 66.96 8.505 ;
     RECT  2.16 8.775 66.96 9.045 ;
     RECT  2.16 9.315 66.96 9.585 ;
     RECT  2.16 9.855 66.96 10.125 ;
     RECT  2.16 10.395 66.96 10.665 ;
     RECT  2.16 10.935 66.96 11.205 ;
     RECT  2.16 11.475 66.96 11.745 ;
     RECT  2.16 12.015 66.96 12.285 ;
     RECT  2.16 12.555 66.96 12.825 ;
     RECT  2.16 13.095 66.96 13.365 ;
     RECT  2.16 13.635 66.96 13.905 ;
     RECT  2.16 14.175 66.96 14.445 ;
     RECT  2.16 14.715 66.96 14.985 ;
     RECT  2.16 15.255 66.96 15.525 ;
     RECT  2.16 15.795 66.96 16.065 ;
     RECT  2.16 16.335 66.96 16.605 ;
     RECT  2.16 16.875 66.96 17.145 ;
     RECT  2.16 17.415 66.96 17.685 ;
     RECT  2.16 17.955 66.96 18.225 ;
     RECT  2.16 18.495 66.96 18.765 ;
     RECT  2.16 19.035 66.96 19.305 ;
     RECT  2.16 19.575 66.96 19.845 ;
     RECT  2.16 20.115 66.96 20.385 ;
     RECT  2.16 20.655 66.96 20.925 ;
     RECT  2.16 21.195 66.96 21.465 ;
     RECT  2.16 21.735 66.96 22.005 ;
     RECT  2.16 22.275 66.96 22.545 ;
     RECT  2.16 22.815 66.96 23.085 ;
     RECT  2.16 23.355 66.96 23.625 ;
     RECT  2.16 23.895 66.96 24.165 ;
     RECT  2.16 24.435 66.96 24.705 ;
     RECT  2.16 24.975 66.96 25.245 ;
     RECT  2.16 25.515 66.96 25.785 ;
     RECT  2.16 26.055 66.96 26.325 ;
     RECT  2.16 26.595 66.96 26.865 ;
     RECT  2.16 27.135 66.96 27.405 ;
     RECT  2.16 27.675 66.96 27.945 ;
     RECT  2.16 28.215 66.96 28.485 ;
     RECT  2.16 28.755 66.96 29.025 ;
     RECT  2.16 29.295 66.96 29.565 ;
     RECT  2.16 29.835 66.96 30.105 ;
     RECT  2.16 30.375 66.96 30.645 ;
     RECT  2.16 30.915 66.96 31.185 ;
     RECT  2.16 31.455 66.96 31.725 ;
     RECT  2.16 31.995 66.96 32.265 ;
     RECT  2.16 32.535 66.96 32.805 ;
     RECT  2.16 33.075 66.96 33.345 ;
     RECT  2.16 33.615 66.96 33.885 ;
     RECT  2.16 34.155 66.96 34.425 ;
     RECT  2.16 34.695 66.96 34.965 ;
     RECT  2.16 35.235 66.96 35.505 ;
     RECT  2.16 35.775 66.96 36.045 ;
     RECT  2.16 36.315 66.96 36.585 ;
     RECT  2.16 36.855 66.96 37.125 ;
     RECT  2.16 37.395 66.96 37.665 ;
     RECT  2.16 37.935 66.96 38.205 ;
     RECT  2.16 38.475 66.96 38.745 ;
     RECT  2.16 39.015 66.96 39.285 ;
     RECT  2.16 39.555 66.96 39.825 ;
     RECT  2.16 40.095 66.96 40.365 ;
     RECT  2.16 40.635 66.96 40.905 ;
     RECT  2.16 41.175 66.96 41.445 ;
     RECT  2.16 41.715 66.96 41.985 ;
     RECT  2.16 42.255 66.96 42.525 ;
     RECT  2.16 42.795 66.96 43.065 ;
     RECT  2.16 43.335 66.96 43.605 ;
     RECT  2.16 43.875 66.96 44.145 ;
     RECT  2.16 44.415 66.96 44.685 ;
     RECT  2.16 44.955 66.96 45.225 ;
     RECT  2.16 45.495 66.96 45.765 ;
     RECT  2.16 46.035 66.96 46.305 ;
     RECT  2.16 46.575 66.96 46.845 ;
     RECT  2.16 47.115 66.96 47.385 ;
     RECT  2.16 47.655 66.96 47.925 ;
     RECT  2.16 48.195 66.96 48.465 ;
     RECT  2.16 48.735 66.96 49.005 ;
     RECT  2.16 49.275 66.96 49.545 ;
     RECT  2.16 49.815 66.96 50.085 ;
     RECT  2.16 50.355 66.96 50.625 ;
     RECT  2.16 50.895 66.96 51.165 ;
     RECT  2.16 51.435 66.96 51.705 ;
     RECT  2.16 51.975 66.96 52.245 ;
     RECT  2.16 52.515 66.96 52.785 ;
     RECT  2.16 53.055 66.96 53.325 ;
     RECT  2.16 53.595 66.96 53.865 ;
     RECT  2.16 54.135 66.96 54.405 ;
     RECT  2.16 54.675 66.96 54.945 ;
     RECT  2.16 55.215 66.96 55.485 ;
     RECT  2.16 55.755 66.96 56.025 ;
     RECT  2.16 56.295 66.96 56.565 ;
     RECT  2.16 56.835 66.96 57.105 ;
     RECT  2.16 57.375 66.96 57.645 ;
     RECT  2.16 57.915 66.96 58.185 ;
     RECT  2.16 58.455 66.96 58.725 ;
     RECT  2.16 58.995 66.96 59.265 ;
     RECT  2.16 59.535 66.96 59.805 ;
     RECT  2.16 60.075 66.96 60.345 ;
     RECT  2.16 60.615 66.96 60.885 ;
     RECT  2.16 61.155 66.96 61.425 ;
     RECT  2.16 61.695 66.96 61.965 ;
     RECT  2.16 62.235 66.96 62.505 ;
     RECT  2.16 62.775 66.96 63.045 ;
     RECT  2.16 63.315 66.96 63.585 ;
     RECT  2.16 63.855 66.96 64.125 ;
     RECT  2.16 64.395 66.96 64.665 ;
     RECT  2.16 64.935 66.96 65.205 ;
     RECT  2.16 65.475 66.96 65.745 ;
     RECT  2.16 66.015 66.96 66.285 ;
     RECT  2.16 66.555 66.96 66.825 ;
    LAYER M1 ;
     RECT  2.16 2.151 66.96 66.969 ;
    LAYER M2 ;
     RECT  0.103 27.531 0.139 27.9 ;
     RECT  0.103 19.62 0.203 19.638 ;
     RECT  0.103 21.132 0.203 21.15 ;
     RECT  0.103 21.942 0.203 21.96 ;
     RECT  0.103 25.866 0.203 25.884 ;
     RECT  0.139 26.802 0.203 27.9 ;
     RECT  0.103 31.158 0.203 31.176 ;
     RECT  0.103 33.588 0.203 34.794 ;
     RECT  0.103 35.712 0.203 35.73 ;
     RECT  0.103 38.79 0.203 38.808 ;
     RECT  0.103 40.068 0.203 40.086 ;
     RECT  0.103 41.22 0.203 42.174 ;
     RECT  0.103 43.146 0.203 43.164 ;
     RECT  0.103 44.73 0.203 45.216 ;
     RECT  0.103 46.386 0.203 46.566 ;
     RECT  0.203 26.802 0.239 26.82 ;
     RECT  0.203 33.588 0.239 33.948 ;
     RECT  0.103 36.828 0.239 36.846 ;
     RECT  0.203 44.892 0.239 45.216 ;
     RECT  0.139 47.736 0.239 47.754 ;
     RECT  0.103 48.636 0.239 49.104 ;
     RECT  0.175 24.138 0.275 24.156 ;
     RECT  0.175 29.808 0.275 29.826 ;
     RECT  0.203 27.846 0.499 27.9 ;
     RECT  0.535 22.554 0.635 22.914 ;
     RECT  0.535 26.766 2.155 26.784 ;
     RECT  0.499 27.846 2.155 28.044 ;
     RECT  0.499 21.438 2.16 21.564 ;
     RECT  0.635 22.554 2.16 22.572 ;
     RECT  2.155 26.766 2.16 28.044 ;
     RECT  2.155 31.932 2.16 31.95 ;
     RECT  0.535 36.126 2.16 36.144 ;
     RECT  0.203 42.156 2.16 42.174 ;
     RECT  0.535 47.286 2.16 47.304 ;
     RECT  0.239 48.636 2.16 48.654 ;
     RECT  2.16 2.151 30.487 66.969 ;
     RECT  30.487 1.962 30.775 66.969 ;
     RECT  30.775 1.881 35.915 66.969 ;
     RECT  35.915 1.998 38.111 66.969 ;
     RECT  38.111 2.106 38.327 66.969 ;
     RECT  38.327 2.151 39.415 66.969 ;
     RECT  39.415 2.106 39.451 66.969 ;
     RECT  39.451 2.07 40.819 66.969 ;
     RECT  40.855 1.152 40.955 1.17 ;
     RECT  40.819 1.926 42.827 66.969 ;
     RECT  42.827 2.106 43.915 66.969 ;
     RECT  43.915 1.926 47.299 66.969 ;
     RECT  47.299 1.881 48.767 66.969 ;
     RECT  48.767 1.926 48.911 66.969 ;
     RECT  48.911 1.962 49.271 66.969 ;
     RECT  49.271 2.151 66.96 66.969 ;
     RECT  66.96 19.926 67.811 38.304 ;
     RECT  66.96 39.186 67.811 51.624 ;
     RECT  67.811 20.088 67.847 22.842 ;
     RECT  67.811 39.366 67.847 51.624 ;
     RECT  67.811 23.868 68.387 35.064 ;
     RECT  67.847 39.366 68.387 43.02 ;
     RECT  67.847 43.848 68.387 51.624 ;
     RECT  67.847 20.088 68.423 22.806 ;
     RECT  68.387 23.868 68.423 25.272 ;
     RECT  68.387 26.334 68.423 27.468 ;
     RECT  68.387 30.852 68.423 35.064 ;
     RECT  68.387 40.14 68.423 40.734 ;
     RECT  68.387 46.818 68.423 49.104 ;
     RECT  68.387 49.896 68.423 51.39 ;
     RECT  68.423 21.78 68.459 21.834 ;
     RECT  68.423 33.966 68.459 34.614 ;
     RECT  68.387 43.848 68.459 44.514 ;
     RECT  68.423 30.852 68.963 32.49 ;
     RECT  68.423 26.334 68.999 27.36 ;
     RECT  68.387 28.692 68.999 29.664 ;
     RECT  68.963 30.852 68.999 31.644 ;
     RECT  67.811 35.856 68.999 38.304 ;
     RECT  68.387 45.774 68.999 46.062 ;
     RECT  68.423 20.124 69.035 20.574 ;
     RECT  68.459 21.78 69.035 21.798 ;
     RECT  68.423 22.626 69.035 22.644 ;
     RECT  68.423 23.976 69.035 25.272 ;
     RECT  68.999 26.334 69.035 27.054 ;
     RECT  68.999 28.8 69.035 29.664 ;
     RECT  68.999 30.852 69.035 31.554 ;
     RECT  68.963 32.472 69.035 32.49 ;
     RECT  68.459 33.966 69.035 33.984 ;
     RECT  68.999 35.856 69.035 36.306 ;
     RECT  68.999 37.44 69.035 38.304 ;
     RECT  68.387 39.366 69.035 39.384 ;
     RECT  68.387 41.796 69.035 42.444 ;
     RECT  68.459 43.848 69.035 44.406 ;
     RECT  68.999 45.81 69.035 46.062 ;
     RECT  68.423 46.818 69.035 48.294 ;
     RECT  68.423 49.086 69.035 49.104 ;
     RECT  68.423 51.174 69.035 51.39 ;
    LAYER M3 ;
     RECT  33.228 0.043 33.246 0.091 ;
     RECT  36.9 0.043 36.918 0.173 ;
     RECT  32.616 0.091 33.246 0.235 ;
     RECT  32.616 0.235 33.606 0.379 ;
     RECT  32.256 0.379 33.606 0.475 ;
     RECT  32.076 0.475 33.606 0.523 ;
     RECT  31.716 0.523 33.606 0.571 ;
     RECT  40.932 0.091 40.95 1.147 ;
     RECT  31.716 0.571 34.146 1.675 ;
     RECT  38.988 1.627 39.006 1.675 ;
     RECT  38.988 1.675 39.114 1.723 ;
     RECT  42.552 1.147 42.57 1.723 ;
     RECT  38.988 1.723 39.654 1.771 ;
     RECT  40.86 1.147 40.95 1.771 ;
     RECT  48.42 0.811 48.438 1.771 ;
     RECT  44.316 1.771 44.334 1.819 ;
     RECT  47.844 1.771 48.438 1.819 ;
     RECT  44.316 1.819 45.27 1.867 ;
     RECT  46.188 1.723 46.206 1.867 ;
     RECT  47.304 1.819 48.438 1.876 ;
     RECT  30.78 1.876 30.798 1.921 ;
     RECT  35.892 0.571 35.91 1.921 ;
     RECT  40.86 1.771 41.49 1.921 ;
     RECT  42.3 1.723 42.57 1.921 ;
     RECT  44.316 1.867 46.206 1.921 ;
     RECT  47.304 1.876 48.762 1.921 ;
     RECT  30.78 1.921 30.87 1.957 ;
     RECT  47.304 1.921 48.906 1.957 ;
     RECT  47.304 1.957 49.266 1.963 ;
     RECT  35.28 1.921 35.91 1.993 ;
     RECT  43.92 1.921 46.206 2.011 ;
     RECT  30.492 1.957 30.87 2.029 ;
     RECT  31.716 1.675 34.218 2.029 ;
     RECT  47.196 1.963 49.266 2.029 ;
     RECT  35.172 1.993 36.486 2.065 ;
     RECT  35.172 2.065 36.918 2.101 ;
     RECT  38.088 1.993 38.106 2.101 ;
     RECT  38.988 1.771 39.726 2.101 ;
     RECT  43.92 2.011 46.314 2.101 ;
     RECT  47.124 2.029 49.266 2.101 ;
     RECT  30.492 2.029 34.218 2.143 ;
     RECT  34.956 2.101 39.726 2.143 ;
     RECT  40.824 1.921 41.49 2.143 ;
     RECT  43.92 2.101 49.266 2.219 ;
     RECT  30.492 2.143 41.49 2.255 ;
     RECT  31.212 2.255 41.49 2.299 ;
     RECT  42.3 1.921 42.822 2.299 ;
     RECT  43.92 2.219 49.014 2.299 ;
     RECT  31.212 2.299 42.822 2.335 ;
     RECT  43.596 2.299 49.014 2.335 ;
     RECT  2.415 2.143 2.505 2.413 ;
     RECT  7.815 2.143 7.905 2.413 ;
     RECT  13.215 2.143 13.305 2.413 ;
     RECT  18.615 2.143 18.705 2.413 ;
     RECT  24.015 2.143 24.105 2.413 ;
     RECT  29.415 2.143 29.505 2.413 ;
     RECT  51.015 2.143 51.105 2.413 ;
     RECT  56.415 2.143 56.505 2.413 ;
     RECT  61.815 2.143 61.905 2.413 ;
     RECT  31.212 2.335 49.014 2.525 ;
     RECT  31.464 2.525 49.014 2.759 ;
     RECT  31.608 2.759 49.014 3.335 ;
     RECT  31.86 3.335 49.014 4.189 ;
     RECT  31.356 4.189 49.014 4.379 ;
     RECT  31.356 4.379 48.186 4.507 ;
     RECT  31.212 4.507 48.186 4.559 ;
     RECT  31.932 4.559 48.186 4.919 ;
     RECT  31.932 4.919 48.078 5.027 ;
     RECT  32.868 5.027 48.078 5.063 ;
     RECT  48.996 4.379 49.014 5.099 ;
     RECT  32.868 5.063 47.862 5.261 ;
     RECT  32.868 5.261 47.718 5.729 ;
     RECT  32.868 5.729 47.394 5.789 ;
     RECT  32.904 5.789 47.394 5.801 ;
     RECT  32.904 5.801 47.142 6.035 ;
     RECT  33.696 6.035 47.142 6.269 ;
     RECT  33.696 6.269 46.602 6.647 ;
     RECT  32.904 6.035 32.922 6.719 ;
     RECT  31.932 5.027 31.95 6.809 ;
     RECT  33.696 6.647 46.458 6.961 ;
     RECT  33.66 6.961 46.458 7.151 ;
     RECT  34.38 7.151 46.458 7.349 ;
     RECT  33.516 7.321 33.534 7.373 ;
     RECT  34.38 7.349 45.954 7.385 ;
     RECT  34.38 7.385 45.897 7.655 ;
     RECT  34.815 7.655 45.897 7.763 ;
     RECT  45.396 7.763 45.897 7.889 ;
     RECT  34.815 7.763 44.37 8.033 ;
     RECT  34.815 8.033 43.506 8.195 ;
     RECT  44.352 8.033 44.37 8.267 ;
     RECT  36.108 8.195 43.398 8.303 ;
     RECT  36.108 8.303 41.85 8.339 ;
     RECT  42.624 8.303 43.398 8.339 ;
     RECT  36.108 8.339 40.77 8.429 ;
     RECT  41.544 8.339 41.85 8.429 ;
     RECT  42.624 8.339 42.642 8.429 ;
     RECT  43.38 8.339 43.398 8.429 ;
     RECT  41.76 8.429 41.85 8.501 ;
     RECT  41.832 8.501 41.85 8.699 ;
     RECT  36.36 8.429 40.734 8.735 ;
     RECT  37.728 8.735 37.746 8.807 ;
     RECT  36.36 8.735 36.378 8.879 ;
     RECT  38.7 8.735 39.15 9.113 ;
     RECT  38.7 9.113 39.006 9.275 ;
     RECT  38.7 9.275 38.718 9.509 ;
     RECT  38.412 9.625 38.502 10.049 ;
     RECT  38.484 10.049 38.502 10.859 ;
     RECT  38.376 10.975 38.394 11.129 ;
     RECT  37.116 10.843 37.134 11.165 ;
     RECT  37.98 11.137 38.106 11.281 ;
     RECT  37.296 11.281 38.106 11.435 ;
     RECT  56.415 2.413 56.697 14.491 ;
     RECT  56.016 14.491 56.697 14.669 ;
     RECT  54.468 14.779 54.486 14.819 ;
     RECT  37.296 11.435 37.314 16.105 ;
     RECT  38.088 11.435 38.106 16.105 ;
     RECT  7.815 2.413 8.097 17.455 ;
     RECT  17.712 17.455 17.73 17.491 ;
     RECT  18.615 2.413 18.897 17.491 ;
     RECT  5.976 17.491 5.994 17.581 ;
     RECT  5.976 17.581 6.246 17.617 ;
     RECT  5.796 17.617 6.246 17.653 ;
     RECT  2.415 2.413 2.697 17.659 ;
     RECT  4.5 17.581 4.518 17.659 ;
     RECT  5.544 17.653 6.246 17.659 ;
     RECT  2.415 17.659 3.402 17.707 ;
     RECT  2.34 17.707 3.402 17.725 ;
     RECT  6.984 17.659 7.002 17.725 ;
     RECT  7.815 17.455 8.37 17.725 ;
     RECT  2.34 17.725 3.51 17.761 ;
     RECT  4.5 17.659 6.246 17.851 ;
     RECT  6.984 17.725 8.37 17.851 ;
     RECT  9.108 17.581 9.126 17.851 ;
     RECT  4.5 17.851 9.126 17.887 ;
     RECT  2.304 17.761 3.51 17.923 ;
     RECT  4.5 17.887 9.234 17.987 ;
     RECT  17.712 17.491 18.897 18.031 ;
     RECT  2.304 17.923 3.546 18.121 ;
     RECT  17.676 18.031 18.897 18.149 ;
     RECT  4.5 17.987 9.198 18.173 ;
     RECT  4.5 18.173 8.226 18.221 ;
     RECT  17.712 18.149 18.897 18.229 ;
     RECT  17.712 18.229 19.098 18.257 ;
     RECT  4.5 18.221 8.097 18.301 ;
     RECT  17.928 18.257 19.098 18.301 ;
     RECT  10.728 18.301 10.818 18.419 ;
     RECT  17.928 18.301 19.782 18.463 ;
     RECT  9.108 18.173 9.198 18.491 ;
     RECT  2.304 18.121 3.618 18.523 ;
     RECT  4.356 18.301 8.097 18.523 ;
     RECT  2.304 18.523 8.097 18.955 ;
     RECT  2.304 18.955 8.478 18.995 ;
     RECT  17.928 18.463 20.25 19.003 ;
     RECT  9.432 18.841 9.45 19.031 ;
     RECT  9.468 19.111 9.486 19.229 ;
     RECT  10.728 18.419 10.746 19.273 ;
     RECT  17.928 19.003 20.502 19.345 ;
     RECT  10.728 19.273 10.818 19.373 ;
     RECT  17.928 19.345 21.042 19.381 ;
     RECT  34.815 8.195 35.097 19.435 ;
     RECT  13.215 2.413 13.497 19.471 ;
     RECT  17.928 19.381 21.078 19.507 ;
     RECT  13.104 19.471 13.497 19.517 ;
     RECT  10.764 19.373 10.818 19.571 ;
     RECT  17.928 19.507 21.474 19.579 ;
     RECT  48.528 19.471 48.546 19.579 ;
     RECT  0.144 19.435 0.162 19.612 ;
     RECT  10.8 19.571 10.818 19.679 ;
     RECT  46.764 19.579 46.782 19.679 ;
     RECT  48.528 19.579 48.906 19.679 ;
     RECT  0.108 19.612 0.198 19.757 ;
     RECT  2.304 18.995 8.37 19.769 ;
     RECT  22.932 19.471 22.95 19.769 ;
     RECT  58.716 19.651 58.806 19.769 ;
     RECT  64.944 19.615 64.962 19.769 ;
     RECT  0.144 19.757 0.198 19.805 ;
     RECT  48.528 19.679 48.546 19.805 ;
     RECT  58.788 19.769 58.806 19.877 ;
     RECT  63.864 19.651 63.882 19.885 ;
     RECT  61.815 2.413 62.097 19.921 ;
     RECT  64.872 19.898 64.89 19.921 ;
     RECT  34.815 19.435 35.334 19.949 ;
     RECT  61.128 19.921 62.097 20.039 ;
     RECT  64.728 19.921 64.89 20.039 ;
     RECT  66.708 20.005 66.726 20.045 ;
     RECT  17.928 19.579 21.618 20.047 ;
     RECT  9.72 19.507 9.738 20.083 ;
     RECT  17.928 20.047 21.726 20.083 ;
     RECT  63.684 19.885 63.882 20.083 ;
     RECT  67.788 19.912 67.806 20.083 ;
     RECT  67.788 20.083 68.418 20.107 ;
     RECT  61.416 20.039 62.097 20.189 ;
     RECT  9.18 20.083 9.738 20.191 ;
     RECT  2.304 19.769 8.226 20.219 ;
     RECT  67.788 20.107 69.03 20.281 ;
     RECT  61.596 20.189 62.097 20.345 ;
     RECT  64.872 20.039 64.89 20.345 ;
     RECT  61.815 20.345 62.097 20.461 ;
     RECT  2.304 20.219 3.798 20.525 ;
     RECT  67.284 20.281 69.03 20.579 ;
     RECT  61.815 20.461 62.694 20.623 ;
     RECT  63.54 20.083 63.882 20.623 ;
     RECT  4.572 20.219 8.226 20.659 ;
     RECT  37.296 16.105 38.106 20.659 ;
     RECT  37.008 20.659 38.106 20.695 ;
     RECT  59.868 20.011 59.886 20.731 ;
     RECT  65.844 20.587 65.862 20.731 ;
     RECT  67.284 20.579 68.418 20.779 ;
     RECT  10.8 20.623 10.818 20.821 ;
     RECT  59.868 20.731 60.39 20.857 ;
     RECT  59.868 20.857 60.462 20.957 ;
     RECT  17.676 20.083 21.726 20.965 ;
     RECT  2.376 20.525 3.798 20.971 ;
     RECT  4.572 20.659 8.262 20.971 ;
     RECT  2.376 20.971 8.262 21.001 ;
     RECT  9.144 20.191 9.738 21.001 ;
     RECT  61.815 20.623 63.882 21.001 ;
     RECT  65.844 20.731 65.934 21.001 ;
     RECT  36.432 20.695 38.106 21.067 ;
     RECT  0.144 19.805 0.162 21.127 ;
     RECT  34.815 19.949 35.097 21.127 ;
     RECT  61.815 21.001 64.386 21.127 ;
     RECT  58.86 21.091 58.878 21.163 ;
     RECT  60.948 20.971 61.074 21.163 ;
     RECT  61.815 21.127 64.422 21.163 ;
     RECT  30.78 21.127 30.798 21.199 ;
     RECT  36.144 21.067 38.106 21.199 ;
     RECT  65.844 21.001 66.186 21.199 ;
     RECT  67.248 20.779 68.418 21.199 ;
     RECT  30.78 21.199 30.87 21.227 ;
     RECT  54.72 21.127 54.738 21.227 ;
     RECT  58.824 21.163 58.878 21.235 ;
     RECT  60.948 21.163 64.494 21.235 ;
     RECT  65.628 21.199 68.418 21.235 ;
     RECT  34.776 21.127 35.097 21.271 ;
     RECT  36.036 21.199 38.178 21.271 ;
     RECT  30.852 21.227 30.87 21.299 ;
     RECT  60.948 21.235 68.418 21.299 ;
     RECT  34.776 21.271 38.178 21.389 ;
     RECT  34.776 21.389 37.134 21.425 ;
     RECT  58.716 21.235 58.878 21.425 ;
     RECT  0.108 21.127 0.198 21.433 ;
     RECT  67.284 21.299 68.418 21.485 ;
     RECT  2.376 21.001 9.738 21.505 ;
     RECT  58.716 21.425 58.842 21.533 ;
     RECT  0.108 21.433 0.522 21.541 ;
     RECT  37.944 21.389 38.178 21.541 ;
     RECT  34.776 21.425 36.738 21.581 ;
     RECT  36.144 21.581 36.738 21.659 ;
     RECT  67.32 21.485 68.418 21.677 ;
     RECT  36.468 21.659 36.486 21.695 ;
     RECT  37.944 21.541 38.502 21.695 ;
     RECT  67.752 21.677 68.418 21.739 ;
     RECT  58.716 21.533 58.77 21.767 ;
     RECT  13.215 19.517 13.497 21.811 ;
     RECT  38.376 21.695 38.502 21.811 ;
     RECT  59.868 20.957 59.886 21.811 ;
     RECT  38.376 21.811 38.574 21.901 ;
     RECT  59.868 21.811 60.03 21.901 ;
     RECT  60.948 21.299 66.258 21.901 ;
     RECT  34.776 21.581 35.097 21.929 ;
     RECT  17.676 20.965 21.798 21.965 ;
     RECT  59.868 21.901 66.258 21.971 ;
     RECT  0.108 21.541 0.558 21.98 ;
     RECT  22.788 21.973 22.806 22.081 ;
     RECT  2.304 21.505 9.738 22.109 ;
     RECT  60.048 21.971 66.258 22.171 ;
     RECT  38.376 21.901 38.646 22.199 ;
     RECT  58.716 21.767 58.734 22.199 ;
     RECT  2.304 22.109 9.702 22.379 ;
     RECT  0.144 21.98 0.558 22.445 ;
     RECT  60.048 22.171 66.33 22.513 ;
     RECT  60.048 22.513 66.69 22.549 ;
     RECT  17.712 21.965 21.798 22.585 ;
     RECT  22.716 22.081 22.806 22.585 ;
     RECT  60.048 22.549 66.834 22.585 ;
     RECT  67.752 21.739 69.03 22.585 ;
     RECT  2.304 22.379 9.594 22.649 ;
     RECT  60.048 22.585 69.03 22.649 ;
     RECT  60.048 22.649 68.418 22.741 ;
     RECT  59.976 22.741 68.418 22.781 ;
     RECT  58.788 22.513 58.806 22.811 ;
     RECT  0.54 22.445 0.558 22.843 ;
     RECT  60.048 22.781 68.418 22.883 ;
     RECT  0.54 22.843 0.63 22.919 ;
     RECT  0.54 22.919 0.558 22.928 ;
     RECT  24.015 2.413 24.297 23.053 ;
     RECT  10.728 20.821 10.818 23.081 ;
     RECT  10.764 23.081 10.818 23.089 ;
     RECT  66.672 22.883 68.418 23.117 ;
     RECT  10.764 23.089 10.854 23.153 ;
     RECT  10.836 23.153 10.854 23.189 ;
     RECT  17.712 22.585 22.806 23.189 ;
     RECT  17.712 23.189 22.086 23.323 ;
     RECT  60.048 22.883 65.754 23.549 ;
     RECT  26.784 23.287 26.802 23.629 ;
     RECT  23.796 23.053 24.297 23.665 ;
     RECT  60.444 23.549 65.754 23.665 ;
     RECT  66.672 23.117 67.806 23.665 ;
     RECT  47.628 23.701 47.646 23.791 ;
     RECT  60.444 23.665 67.806 23.819 ;
     RECT  65.952 23.819 67.806 23.863 ;
     RECT  69.012 23.659 69.03 23.863 ;
     RECT  27.648 23.431 27.666 23.899 ;
     RECT  58.716 23.791 58.734 23.899 ;
     RECT  59.544 23.791 59.562 23.899 ;
     RECT  31.572 21.775 31.59 23.935 ;
     RECT  38.556 22.199 38.574 23.935 ;
     RECT  38.232 23.935 38.574 23.963 ;
     RECT  0.144 23.755 0.162 24.043 ;
     RECT  65.952 23.863 69.03 24.125 ;
     RECT  2.304 22.649 9.486 24.169 ;
     RECT  0.144 24.043 0.342 24.173 ;
     RECT  10.764 23.971 10.782 24.241 ;
     RECT  2.268 24.169 9.486 24.269 ;
     RECT  10.764 24.241 10.818 24.331 ;
     RECT  27.648 23.899 27.81 24.331 ;
     RECT  58.716 23.899 59.562 24.331 ;
     RECT  66.096 24.125 69.03 24.359 ;
     RECT  48.888 24.241 48.906 24.367 ;
     RECT  25.02 22.981 25.038 24.403 ;
     RECT  10.728 24.331 10.818 24.431 ;
     RECT  66.24 24.359 69.03 24.467 ;
     RECT  58.716 24.331 59.634 24.469 ;
     RECT  60.444 23.819 65.142 24.469 ;
     RECT  58.716 24.469 65.142 24.509 ;
     RECT  29.415 2.413 29.697 24.511 ;
     RECT  66.564 24.467 69.03 24.653 ;
     RECT  0.144 24.173 0.162 24.701 ;
     RECT  10.764 24.431 10.818 24.737 ;
     RECT  48.888 24.367 49.338 24.871 ;
     RECT  23.076 23.665 24.297 24.943 ;
     RECT  25.02 24.403 25.398 24.943 ;
     RECT  58.716 24.509 59.634 24.943 ;
     RECT  60.444 24.509 65.142 24.943 ;
     RECT  10.8 24.737 10.818 25.079 ;
     RECT  60.444 24.943 65.358 25.177 ;
     RECT  48.888 24.871 49.878 25.249 ;
     RECT  51.015 2.413 51.297 25.249 ;
     RECT  69.012 24.653 69.03 25.277 ;
     RECT  58.392 24.943 59.634 25.285 ;
     RECT  60.444 25.177 65.538 25.285 ;
     RECT  26.136 23.629 26.802 25.321 ;
     RECT  27.612 24.331 27.81 25.321 ;
     RECT  58.392 25.285 65.538 25.321 ;
     RECT  23.076 24.943 25.398 25.483 ;
     RECT  26.136 25.321 27.81 25.483 ;
     RECT  66.564 24.653 67.878 25.579 ;
     RECT  28.764 24.511 29.697 25.591 ;
     RECT  66.564 25.579 68.382 25.717 ;
     RECT  58.392 25.321 65.574 25.753 ;
     RECT  66.312 25.717 68.382 25.753 ;
     RECT  58.392 25.753 68.382 25.817 ;
     RECT  0.144 25.675 0.162 25.852 ;
     RECT  17.352 23.323 22.086 25.861 ;
     RECT  23.076 25.483 27.81 25.861 ;
     RECT  17.352 25.861 27.81 25.987 ;
     RECT  28.764 25.591 29.934 25.987 ;
     RECT  0.108 25.852 0.198 25.997 ;
     RECT  48.888 25.249 51.297 26.023 ;
     RECT  52.128 25.789 52.146 26.023 ;
     RECT  10.8 25.951 10.818 26.051 ;
     RECT  68.364 25.817 68.382 26.155 ;
     RECT  17.352 25.987 29.934 26.365 ;
     RECT  58.392 25.817 67.374 26.519 ;
     RECT  47.628 23.791 48.078 26.527 ;
     RECT  48.888 26.023 52.146 26.527 ;
     RECT  0.144 25.997 0.198 26.761 ;
     RECT  66.708 26.519 67.374 26.761 ;
     RECT  68.364 26.155 69.03 26.761 ;
     RECT  10.512 26.761 10.53 26.905 ;
     RECT  17.352 26.365 30.582 26.905 ;
     RECT  31.572 23.935 31.626 26.905 ;
     RECT  0.144 26.761 0.558 26.957 ;
     RECT  10.512 26.905 10.782 27.059 ;
     RECT  66.708 26.761 69.03 27.059 ;
     RECT  41.436 27.067 41.454 27.103 ;
     RECT  42.192 26.635 42.21 27.103 ;
     RECT  2.304 24.269 9.486 27.131 ;
     RECT  2.304 27.131 9.414 27.301 ;
     RECT  2.16 27.301 9.414 27.341 ;
     RECT  66.708 27.059 68.994 27.341 ;
     RECT  67.284 27.341 68.994 27.365 ;
     RECT  0.144 26.957 0.342 27.526 ;
     RECT  58.392 26.519 65.898 27.607 ;
     RECT  41.436 27.103 42.21 27.751 ;
     RECT  58.392 27.607 66.438 27.779 ;
     RECT  0.108 27.526 0.342 27.787 ;
     RECT  67.284 27.365 68.418 27.821 ;
     RECT  0.108 27.787 0.378 27.841 ;
     RECT  0.108 27.841 0.558 27.917 ;
     RECT  0.504 27.917 0.558 28.109 ;
     RECT  2.415 27.341 9.414 28.111 ;
     RECT  41.436 27.751 42.57 28.147 ;
     RECT  13.215 21.811 14.022 28.319 ;
     RECT  67.284 27.821 68.382 28.409 ;
     RECT  2.415 28.111 9.45 28.561 ;
     RECT  10.512 27.059 10.53 28.561 ;
     RECT  0.504 28.109 0.522 28.589 ;
     RECT  58.392 27.779 66.186 28.687 ;
     RECT  67.284 28.409 67.806 28.687 ;
     RECT  10.512 28.561 10.854 28.723 ;
     RECT  10.512 28.723 10.926 28.831 ;
     RECT  40.215 8.735 40.497 28.831 ;
     RECT  41.436 28.147 43.038 28.831 ;
     RECT  10.512 28.831 10.998 28.949 ;
     RECT  43.812 28.561 43.83 29.029 ;
     RECT  44.712 28.525 44.73 29.029 ;
     RECT  58.392 28.687 67.806 29.057 ;
     RECT  2.304 28.561 9.45 29.165 ;
     RECT  66.708 29.057 67.806 29.165 ;
     RECT  2.415 29.165 9.45 29.227 ;
     RECT  10.512 28.949 10.854 29.227 ;
     RECT  66.708 29.165 66.726 29.261 ;
     RECT  34.815 21.929 35.097 29.263 ;
     RECT  67.788 29.165 67.806 29.323 ;
     RECT  68.976 28.555 69.03 29.323 ;
     RECT  58.392 29.057 65.934 29.399 ;
     RECT  0.144 29.275 0.162 29.453 ;
     RECT  58.392 29.399 65.826 29.525 ;
     RECT  34.815 29.263 35.19 29.569 ;
     RECT  47.628 26.527 52.146 29.605 ;
     RECT  34.815 29.569 35.622 29.641 ;
     RECT  67.788 29.323 69.03 29.669 ;
     RECT  2.415 29.227 10.854 29.831 ;
     RECT  0.18 29.707 0.342 29.837 ;
     RECT  0.18 29.837 0.198 29.84 ;
     RECT  34.815 29.641 36.234 29.911 ;
     RECT  43.812 29.029 44.73 30.037 ;
     RECT  67.788 29.669 68.382 30.271 ;
     RECT  47.628 29.605 52.182 30.343 ;
     RECT  58.716 29.525 65.826 30.343 ;
     RECT  67.284 30.271 68.382 30.379 ;
     RECT  58.716 30.343 66.474 30.415 ;
     RECT  67.248 30.379 68.382 30.415 ;
     RECT  34.524 29.911 36.234 30.451 ;
     RECT  58.716 30.415 68.382 30.571 ;
     RECT  45.615 7.889 45.897 30.685 ;
     RECT  45.615 30.685 46.494 30.721 ;
     RECT  47.628 30.343 52.722 30.721 ;
     RECT  2.415 29.831 10.818 30.811 ;
     RECT  43.812 30.037 44.874 30.883 ;
     RECT  45.615 30.721 52.722 30.883 ;
     RECT  2.415 30.811 10.89 30.911 ;
     RECT  2.415 30.911 10.818 30.919 ;
     RECT  2.34 30.919 10.818 30.947 ;
     RECT  58.716 30.571 69.03 31.019 ;
     RECT  2.34 30.947 10.53 31.147 ;
     RECT  0.216 30.763 0.234 31.153 ;
     RECT  66.6 31.019 69.03 31.181 ;
     RECT  0.108 31.153 0.234 31.229 ;
     RECT  2.304 31.147 10.53 31.243 ;
     RECT  0.108 31.229 0.198 31.373 ;
     RECT  0.18 31.373 0.198 31.421 ;
     RECT  67.752 31.181 69.03 31.559 ;
     RECT  58.716 31.019 65.682 31.649 ;
     RECT  67.752 31.559 68.994 31.649 ;
     RECT  40.215 28.831 43.038 31.657 ;
     RECT  43.812 30.883 52.722 31.657 ;
     RECT  2.268 31.243 10.53 31.729 ;
     RECT  66.6 31.181 67.014 31.867 ;
     RECT  2.268 31.729 10.782 31.915 ;
     RECT  58.716 31.649 65.25 31.919 ;
     RECT  2.16 31.915 10.782 31.955 ;
     RECT  38.232 23.963 38.25 31.999 ;
     RECT  67.752 31.649 68.958 32.045 ;
     RECT  2.304 31.955 10.782 32.071 ;
     RECT  58.716 31.919 65.07 32.099 ;
     RECT  38.232 31.999 38.862 32.197 ;
     RECT  40.215 31.657 52.722 32.269 ;
     RECT  34.524 30.451 36.27 32.305 ;
     RECT  66.492 31.867 67.014 32.395 ;
     RECT  67.752 32.045 67.842 32.395 ;
     RECT  0.144 32.251 0.162 32.429 ;
     RECT  66.492 32.395 67.842 32.575 ;
     RECT  69.012 32.467 69.03 32.621 ;
     RECT  38.232 32.197 38.97 32.773 ;
     RECT  2.304 32.071 10.854 32.809 ;
     RECT  14.832 32.269 14.922 32.837 ;
     RECT  13.215 28.319 13.95 32.872 ;
     RECT  65.808 32.575 67.842 32.872 ;
     RECT  40.215 32.269 53.046 32.875 ;
     RECT  58.968 32.099 65.07 32.881 ;
     RECT  65.808 32.872 68.418 32.881 ;
     RECT  2.304 32.809 10.926 32.909 ;
     RECT  13.104 32.872 13.95 32.909 ;
     RECT  14.904 32.837 14.922 32.909 ;
     RECT  37.908 32.773 38.97 32.923 ;
     RECT  40.104 32.875 53.046 33.053 ;
     RECT  37.908 32.923 39.006 33.079 ;
     RECT  37.908 33.079 39.042 33.269 ;
     RECT  34.524 32.305 36.702 33.349 ;
     RECT  58.968 32.881 68.418 33.377 ;
     RECT  37.908 33.269 38.862 33.413 ;
     RECT  2.304 32.909 10.854 33.448 ;
     RECT  58.968 33.377 66.33 33.511 ;
     RECT  2.268 33.448 10.854 33.539 ;
     RECT  0.144 33.163 0.162 33.547 ;
     RECT  67.284 33.377 68.418 33.547 ;
     RECT  0.108 33.547 0.162 33.583 ;
     RECT  2.304 33.539 10.854 33.809 ;
     RECT  17.352 26.905 31.626 33.889 ;
     RECT  34.524 33.349 37.134 33.889 ;
     RECT  37.908 33.413 38.826 33.889 ;
     RECT  34.524 33.889 38.826 33.953 ;
     RECT  67.284 33.547 69.03 33.989 ;
     RECT  58.716 33.511 66.33 34.079 ;
     RECT  40.215 33.053 53.046 34.115 ;
     RECT  66.24 34.079 66.33 34.115 ;
     RECT  66.312 34.115 66.33 34.151 ;
     RECT  67.284 33.989 68.454 34.219 ;
     RECT  67.248 34.219 68.454 34.357 ;
     RECT  58.716 34.079 65.358 34.421 ;
     RECT  2.304 33.809 10.818 34.457 ;
     RECT  66.6 34.357 68.454 34.457 ;
     RECT  17.352 33.889 32.094 34.493 ;
     RECT  17.928 34.493 32.094 34.501 ;
     RECT  32.94 34.195 32.958 34.501 ;
     RECT  34.524 33.953 38.466 34.591 ;
     RECT  2.304 34.457 10.53 34.603 ;
     RECT  33.948 34.591 38.466 34.685 ;
     RECT  0.108 33.583 0.234 34.795 ;
     RECT  0.108 34.795 0.342 34.799 ;
     RECT  2.268 34.603 10.53 34.799 ;
     RECT  17.928 34.501 32.958 34.861 ;
     RECT  0.144 34.799 0.342 34.925 ;
     RECT  17.928 34.861 33.03 34.969 ;
     RECT  40.215 34.115 52.182 34.997 ;
     RECT  58.716 34.421 65.322 34.997 ;
     RECT  34.524 34.685 38.466 35.041 ;
     RECT  58.752 34.997 65.322 35.159 ;
     RECT  58.788 35.159 65.322 35.195 ;
     RECT  2.304 34.799 10.53 35.203 ;
     RECT  0.144 34.925 0.306 35.261 ;
     RECT  53.028 34.115 53.046 35.267 ;
     RECT  58.86 35.195 65.322 35.311 ;
     RECT  2.304 35.203 10.782 35.401 ;
     RECT  67.248 34.457 68.454 35.473 ;
     RECT  66.708 35.473 68.454 35.563 ;
     RECT  0.144 35.261 0.198 35.692 ;
     RECT  66.708 35.563 69.03 35.699 ;
     RECT  34.524 35.041 38.502 35.707 ;
     RECT  17.928 34.969 33.21 35.815 ;
     RECT  0.108 35.692 0.198 35.885 ;
     RECT  34.236 35.707 38.502 35.941 ;
     RECT  58.86 35.311 65.718 35.941 ;
     RECT  17.928 35.815 33.246 36.049 ;
     RECT  34.2 35.941 38.502 36.049 ;
     RECT  58.716 35.941 65.718 36.419 ;
     RECT  66.708 35.699 66.726 36.523 ;
     RECT  67.788 35.699 69.03 36.523 ;
     RECT  0.54 36.121 0.558 36.557 ;
     RECT  2.304 35.401 10.818 36.617 ;
     RECT  66.708 36.523 69.03 36.625 ;
     RECT  66.564 36.625 69.03 36.689 ;
     RECT  66.564 36.689 67.338 36.751 ;
     RECT  2.304 36.617 10.746 36.815 ;
     RECT  68.328 36.689 69.03 36.815 ;
     RECT  0.108 36.811 0.342 36.851 ;
     RECT  0.144 36.851 0.342 37.037 ;
     RECT  65.808 36.751 67.338 37.319 ;
     RECT  65.808 37.319 65.862 37.391 ;
     RECT  58.716 36.419 64.962 37.435 ;
     RECT  0.144 37.037 0.234 37.517 ;
     RECT  66.6 37.319 67.338 37.579 ;
     RECT  68.364 36.815 69.03 37.579 ;
     RECT  58.716 37.435 65.574 37.589 ;
     RECT  58.716 37.589 65.394 37.625 ;
     RECT  47.628 34.997 52.182 37.669 ;
     RECT  2.304 36.815 10.53 37.741 ;
     RECT  66.6 37.579 69.03 37.859 ;
     RECT  66.6 37.859 66.69 38.003 ;
     RECT  67.752 37.859 69.03 38.129 ;
     RECT  67.86 38.129 69.03 38.189 ;
     RECT  40.215 34.997 46.854 38.209 ;
     RECT  47.628 37.669 52.722 38.209 ;
     RECT  68.4 38.189 69.03 38.285 ;
     RECT  69.012 38.285 69.03 38.309 ;
     RECT  0.144 37.517 0.162 38.395 ;
     RECT  58.716 37.625 65.358 38.399 ;
     RECT  2.304 37.741 10.782 38.407 ;
     RECT  0.144 38.395 0.234 38.669 ;
     RECT  58.716 38.399 64.962 38.669 ;
     RECT  0.144 38.669 0.198 38.785 ;
     RECT  66.672 38.003 66.69 38.821 ;
     RECT  2.304 38.407 10.818 38.911 ;
     RECT  17.928 36.049 38.502 38.911 ;
     RECT  2.268 38.911 10.818 38.957 ;
     RECT  65.808 38.785 65.826 38.975 ;
     RECT  66.672 38.821 66.762 39.091 ;
     RECT  0.108 38.785 0.198 39.101 ;
     RECT  0.108 39.101 0.162 39.149 ;
     RECT  58.752 38.669 64.962 39.245 ;
     RECT  60.948 39.245 64.962 39.325 ;
     RECT  66.24 39.091 66.762 39.325 ;
     RECT  67.788 39.115 67.806 39.325 ;
     RECT  2.304 38.957 10.818 39.361 ;
     RECT  69.012 39.307 69.03 39.389 ;
     RECT  2.304 39.361 10.926 39.479 ;
     RECT  58.752 39.245 60.21 39.523 ;
     RECT  60.948 39.325 65.034 39.595 ;
     RECT  66.24 39.325 67.806 39.595 ;
     RECT  60.948 39.595 65.178 39.721 ;
     RECT  66.24 39.595 68.382 39.721 ;
     RECT  60.948 39.721 68.382 39.749 ;
     RECT  60.948 39.749 65.79 39.857 ;
     RECT  60.948 39.857 65.502 40.055 ;
     RECT  0.144 39.149 0.162 40.06 ;
     RECT  66.564 39.749 68.382 40.135 ;
     RECT  60.948 40.055 65.43 40.289 ;
     RECT  0.108 40.06 0.198 40.301 ;
     RECT  58.716 39.523 60.21 40.325 ;
     RECT  0.144 40.301 0.198 40.349 ;
     RECT  58.716 40.325 58.878 40.469 ;
     RECT  2.304 39.479 10.818 40.639 ;
     RECT  59.868 40.325 60.21 40.711 ;
     RECT  60.948 40.289 65.322 40.711 ;
     RECT  59.868 40.711 65.322 40.739 ;
     RECT  2.304 40.639 10.854 40.973 ;
     RECT  66.564 40.135 68.418 40.973 ;
     RECT  59.868 40.739 65.106 41.009 ;
     RECT  0.144 40.349 0.162 41.212 ;
     RECT  58.716 40.469 58.806 41.477 ;
     RECT  67.248 40.973 68.418 41.515 ;
     RECT  13.215 32.909 13.95 41.611 ;
     RECT  64.476 41.009 65.106 41.611 ;
     RECT  66.24 41.179 66.258 41.611 ;
     RECT  13.104 41.611 13.95 41.648 ;
     RECT  64.476 41.611 66.258 41.747 ;
     RECT  0.108 41.212 0.198 41.783 ;
     RECT  58.716 41.477 58.77 41.909 ;
     RECT  59.868 41.009 63.738 41.917 ;
     RECT  64.476 41.747 65.07 41.917 ;
     RECT  58.716 41.909 58.734 41.933 ;
     RECT  66.06 41.747 66.258 41.944 ;
     RECT  67.248 41.515 69.03 41.944 ;
     RECT  0.108 41.783 0.162 41.981 ;
     RECT  54.108 40.441 54.126 41.981 ;
     RECT  59.544 41.917 65.07 42.025 ;
     RECT  56.415 14.669 56.697 42.043 ;
     RECT  56.304 42.043 56.697 42.089 ;
     RECT  59.508 42.025 65.07 42.215 ;
     RECT  0.108 41.981 0.126 42.317 ;
     RECT  59.868 42.215 65.07 42.323 ;
     RECT  66.06 41.944 69.03 42.449 ;
     RECT  66.06 42.449 68.382 42.485 ;
     RECT  60.192 42.323 65.07 42.523 ;
     RECT  17.928 38.911 38.574 42.565 ;
     RECT  40.215 38.209 52.722 42.593 ;
     RECT  60.192 42.523 65.286 42.593 ;
     RECT  66.06 42.485 66.078 42.593 ;
     RECT  60.48 42.593 65.286 42.605 ;
     RECT  64.188 42.605 65.286 42.719 ;
     RECT  0.144 42.763 0.162 42.811 ;
     RECT  0.144 42.811 0.234 42.989 ;
     RECT  67.248 42.485 68.382 43.085 ;
     RECT  0.144 42.989 0.198 43.132 ;
     RECT  2.304 40.973 10.818 43.259 ;
     RECT  0.108 43.132 0.198 43.277 ;
     RECT  0.18 43.277 0.198 43.325 ;
     RECT  58.788 42.961 58.806 43.501 ;
     RECT  64.188 42.719 64.998 43.501 ;
     RECT  67.248 43.085 67.842 43.531 ;
     RECT  60.48 42.605 63.306 43.537 ;
     RECT  64.08 43.501 64.998 43.537 ;
     RECT  2.304 43.259 10.53 43.601 ;
     RECT  58.716 43.501 58.806 43.609 ;
     RECT  58.716 43.609 58.842 43.627 ;
     RECT  2.304 43.601 9.594 43.709 ;
     RECT  58.716 43.627 58.914 43.709 ;
     RECT  2.304 43.709 9.522 43.799 ;
     RECT  60.48 43.537 66.078 43.807 ;
     RECT  17.928 42.565 38.754 43.843 ;
     RECT  60.444 43.807 66.078 43.879 ;
     RECT  17.928 43.843 39.042 43.915 ;
     RECT  60.012 43.879 66.078 43.915 ;
     RECT  67.212 43.531 67.842 43.915 ;
     RECT  69.012 43.627 69.03 43.915 ;
     RECT  17.928 43.915 39.078 43.951 ;
     RECT  40.215 42.593 52.182 43.951 ;
     RECT  59.868 43.915 66.078 44.105 ;
     RECT  67.212 43.915 69.03 44.141 ;
     RECT  58.716 43.709 58.878 44.177 ;
     RECT  65.16 44.105 66.078 44.177 ;
     RECT  66.06 44.177 66.078 44.185 ;
     RECT  58.716 44.177 58.842 44.222 ;
     RECT  59.868 44.105 64.35 44.249 ;
     RECT  59.868 44.249 60.03 44.339 ;
     RECT  59.868 44.339 59.886 44.375 ;
     RECT  67.788 44.141 69.03 44.411 ;
     RECT  0.144 44.011 0.162 44.443 ;
     RECT  2.304 43.799 9.486 44.447 ;
     RECT  0.144 44.443 0.198 44.491 ;
     RECT  2.304 44.447 9.414 44.609 ;
     RECT  66.06 44.185 66.69 44.717 ;
     RECT  0.108 44.491 0.198 44.779 ;
     RECT  67.788 44.411 68.454 44.813 ;
     RECT  60.948 44.249 64.35 44.827 ;
     RECT  66.06 44.717 66.546 44.879 ;
     RECT  60.948 44.827 64.422 44.887 ;
     RECT  65.16 44.177 65.214 44.887 ;
     RECT  67.788 44.813 68.382 44.959 ;
     RECT  17.928 43.951 52.182 44.987 ;
     RECT  58.716 44.222 58.806 45.031 ;
     RECT  60.948 44.887 65.214 45.031 ;
     RECT  66.06 44.879 66.474 45.031 ;
     RECT  67.284 44.959 68.382 45.101 ;
     RECT  10.512 43.601 10.53 45.121 ;
     RECT  0.108 44.779 0.342 45.197 ;
     RECT  0.108 45.197 0.234 45.221 ;
     RECT  0.216 45.221 0.234 45.245 ;
     RECT  60.948 45.031 66.474 45.257 ;
     RECT  10.512 45.121 10.782 45.293 ;
     RECT  58.716 45.031 58.842 45.301 ;
     RECT  65.88 45.257 65.934 45.329 ;
     RECT  10.512 45.293 10.746 45.419 ;
     RECT  60.156 45.193 60.174 45.455 ;
     RECT  17.964 44.987 52.182 45.527 ;
     RECT  67.752 45.101 68.382 45.547 ;
     RECT  10.512 45.419 10.674 45.599 ;
     RECT  58.716 45.301 58.878 45.599 ;
     RECT  2.304 44.609 8.838 45.643 ;
     RECT  2.268 45.643 8.838 45.661 ;
     RECT  60.948 45.257 64.89 45.769 ;
     RECT  10.512 45.599 10.53 45.797 ;
     RECT  2.268 45.661 9.054 45.832 ;
     RECT  2.268 45.832 9.09 45.931 ;
     RECT  67.752 45.547 69.03 46.003 ;
     RECT  60.66 45.769 64.89 46.031 ;
     RECT  13.215 41.648 13.95 46.067 ;
     RECT  2.268 45.931 9.378 46.109 ;
     RECT  65.88 45.329 65.898 46.111 ;
     RECT  67.32 46.003 69.03 46.111 ;
     RECT  2.376 46.109 9.378 46.237 ;
     RECT  0.108 46.219 0.126 46.267 ;
     RECT  13.215 46.067 13.497 46.345 ;
     RECT  58.716 45.599 58.806 46.345 ;
     RECT  2.376 46.237 9.486 46.373 ;
     RECT  60.84 46.031 64.89 46.381 ;
     RECT  13.104 46.345 13.497 46.397 ;
     RECT  0.108 46.267 0.198 46.411 ;
     RECT  65.88 46.111 65.97 46.471 ;
     RECT  2.376 46.373 9.306 46.499 ;
     RECT  67.284 46.111 69.03 46.499 ;
     RECT  67.284 46.499 67.302 46.507 ;
     RECT  0.108 46.411 0.342 46.541 ;
     RECT  58.716 46.345 58.878 46.555 ;
     RECT  58.716 46.555 58.914 46.643 ;
     RECT  60.84 46.381 64.998 46.741 ;
     RECT  65.88 46.471 66.006 46.741 ;
     RECT  60.84 46.741 66.006 46.777 ;
     RECT  10.8 46.381 10.818 46.813 ;
     RECT  0.108 46.541 0.234 46.829 ;
     RECT  68.328 46.499 69.03 46.829 ;
     RECT  0.18 46.829 0.234 46.877 ;
     RECT  10.764 46.813 10.926 46.913 ;
     RECT  2.376 46.499 8.838 46.987 ;
     RECT  10.908 46.913 10.926 47.039 ;
     RECT  60.84 46.777 66.222 47.047 ;
     RECT  67.248 46.507 67.302 47.047 ;
     RECT  60.84 47.047 67.302 47.219 ;
     RECT  60.912 47.219 67.302 47.309 ;
     RECT  0.324 47.281 0.558 47.371 ;
     RECT  59.868 45.571 59.886 47.425 ;
     RECT  2.304 46.987 8.838 47.461 ;
     RECT  58.716 46.643 58.842 47.461 ;
     RECT  0.324 47.371 0.666 47.501 ;
     RECT  13.215 46.397 13.497 47.551 ;
     RECT  60.948 47.309 67.302 47.563 ;
     RECT  68.364 46.829 69.03 47.563 ;
     RECT  58.716 47.461 58.878 47.587 ;
     RECT  13.104 47.551 13.497 47.597 ;
     RECT  60.948 47.563 69.03 47.651 ;
     RECT  59.868 47.425 60.066 47.687 ;
     RECT  0.324 47.501 0.342 47.693 ;
     RECT  58.716 47.587 58.914 47.723 ;
     RECT  0.216 47.707 0.234 47.731 ;
     RECT  58.716 47.723 58.878 47.741 ;
     RECT  0.144 47.731 0.234 47.759 ;
     RECT  0.144 47.759 0.162 47.789 ;
     RECT  58.716 47.741 58.842 47.849 ;
     RECT  59.868 47.687 60.03 47.849 ;
     RECT  64.44 47.651 69.03 47.849 ;
     RECT  66.24 47.849 69.03 47.957 ;
     RECT  2.304 47.461 8.946 48.001 ;
     RECT  66.672 47.957 69.03 48.029 ;
     RECT  1.152 48.283 1.17 48.331 ;
     RECT  60.948 47.651 63.666 48.397 ;
     RECT  1.152 48.331 1.278 48.461 ;
     RECT  60.804 48.397 63.666 48.497 ;
     RECT  2.304 48.001 9.162 48.505 ;
     RECT  2.304 48.505 9.234 48.659 ;
     RECT  59.868 47.849 59.886 48.667 ;
     RECT  0.108 48.619 0.126 48.703 ;
     RECT  60.84 48.497 63.666 48.767 ;
     RECT  58.716 47.849 58.806 48.803 ;
     RECT  64.44 47.849 65.394 48.805 ;
     RECT  59.868 48.667 60.102 48.839 ;
     RECT  64.44 48.805 65.826 48.845 ;
     RECT  2.304 48.659 9.162 48.848 ;
     RECT  64.44 48.845 65.754 48.901 ;
     RECT  59.868 48.839 59.886 48.907 ;
     RECT  59.796 48.907 59.886 48.929 ;
     RECT  64.404 48.901 65.754 48.929 ;
     RECT  60.912 48.767 63.666 48.937 ;
     RECT  64.404 48.929 64.926 48.937 ;
     RECT  60.912 48.937 64.926 48.941 ;
     RECT  59.796 48.929 59.814 48.964 ;
     RECT  59.76 48.964 59.814 48.965 ;
     RECT  59.76 48.965 59.778 49.073 ;
     RECT  0.108 48.703 0.234 49.109 ;
     RECT  66.708 48.029 69.03 49.109 ;
     RECT  0.108 49.109 0.126 49.133 ;
     RECT  1.116 49.003 1.134 49.181 ;
     RECT  10.656 49.045 10.746 49.199 ;
     RECT  18.504 45.527 52.182 49.307 ;
     RECT  10.656 49.199 10.674 49.379 ;
     RECT  18.504 49.307 51.606 49.469 ;
     RECT  66.708 49.109 68.382 49.517 ;
     RECT  2.415 48.848 9.162 49.541 ;
     RECT  60.948 48.941 64.926 49.565 ;
     RECT  65.664 48.929 65.754 49.621 ;
     RECT  66.708 49.517 66.726 49.709 ;
     RECT  64.08 49.565 64.926 49.747 ;
     RECT  65.664 49.621 65.898 49.747 ;
     RECT  58.716 48.803 58.734 49.783 ;
     RECT  64.08 49.747 65.898 49.819 ;
     RECT  2.415 49.541 8.838 49.883 ;
     RECT  67.716 49.517 68.382 49.891 ;
     RECT  60.948 49.565 63.342 49.919 ;
     RECT  3.852 49.883 8.838 50.189 ;
     RECT  60.048 49.747 60.066 50.315 ;
     RECT  61.815 49.919 63.342 50.323 ;
     RECT  64.08 49.819 66.15 50.323 ;
     RECT  67.716 49.891 68.418 50.347 ;
     RECT  60.948 49.919 60.966 50.359 ;
     RECT  60.84 50.359 60.966 50.431 ;
     RECT  61.815 50.323 66.15 50.431 ;
     RECT  67.248 50.347 68.418 50.431 ;
     RECT  3.996 50.189 6.138 50.459 ;
     RECT  2.415 49.883 3.006 50.549 ;
     RECT  60.372 50.431 60.966 50.549 ;
     RECT  61.815 50.431 68.418 50.549 ;
     RECT  7.092 50.189 8.838 50.585 ;
     RECT  61.815 50.549 65.79 50.657 ;
     RECT  60.84 50.549 60.966 50.729 ;
     RECT  60.948 50.729 60.966 50.827 ;
     RECT  61.815 50.657 65.538 50.827 ;
     RECT  66.672 50.549 68.418 50.827 ;
     RECT  3.996 50.459 4.59 50.855 ;
     RECT  60.948 50.827 65.538 50.891 ;
     RECT  66.672 50.827 69.03 50.927 ;
     RECT  3.996 50.855 4.266 50.963 ;
     RECT  7.815 50.585 8.838 50.999 ;
     RECT  64.404 50.891 65.538 50.999 ;
     RECT  58.716 49.783 58.806 51.061 ;
     RECT  60.948 50.891 63.666 51.125 ;
     RECT  58.716 51.061 58.878 51.149 ;
     RECT  66.672 50.927 66.726 51.149 ;
     RECT  65.448 50.999 65.538 51.197 ;
     RECT  58.716 51.149 58.842 51.245 ;
     RECT  58.716 51.245 58.806 51.269 ;
     RECT  65.52 51.197 65.538 51.269 ;
     RECT  64.404 50.999 64.638 51.359 ;
     RECT  67.788 50.927 69.03 51.359 ;
     RECT  8.82 50.999 8.838 51.395 ;
     RECT  68.364 51.359 69.03 51.395 ;
     RECT  64.44 51.359 64.638 51.431 ;
     RECT  4.248 50.963 4.266 51.467 ;
     RECT  5.472 50.459 6.138 51.503 ;
     RECT  6.12 51.503 6.138 51.539 ;
     RECT  60.948 51.125 63.558 51.629 ;
     RECT  68.364 51.395 68.382 51.629 ;
     RECT  61.815 51.629 63.558 51.737 ;
     RECT  66.672 51.149 66.69 51.737 ;
     RECT  63.54 51.737 63.558 51.773 ;
     RECT  58.788 51.269 58.806 51.809 ;
     RECT  61.815 51.737 62.766 51.809 ;
     RECT  64.62 51.431 64.638 51.809 ;
     RECT  52.776 62.731 52.794 63.499 ;
     RECT  52.452 63.499 52.794 63.545 ;
     RECT  52.776 63.545 52.794 63.725 ;
     RECT  18.504 49.469 51.39 64.021 ;
     RECT  18.288 64.021 51.39 64.201 ;
     RECT  18.144 64.201 51.39 64.705 ;
     RECT  18.072 64.705 51.39 64.939 ;
     RECT  17.784 64.939 51.39 65.101 ;
     RECT  17.712 65.101 51.39 65.245 ;
     RECT  17.532 65.245 51.39 65.939 ;
     RECT  17.532 65.939 51.297 66.479 ;
     RECT  2.415 50.549 2.697 66.707 ;
     RECT  7.815 50.999 8.097 66.707 ;
     RECT  13.215 47.597 13.497 66.707 ;
     RECT  29.376 66.479 51.297 66.707 ;
     RECT  56.415 42.089 56.697 66.707 ;
     RECT  61.815 51.809 62.097 66.707 ;
     RECT  17.532 66.479 28.566 66.749 ;
     RECT  29.376 66.707 51.105 66.749 ;
     RECT  17.532 66.749 24.498 66.865 ;
     RECT  29.376 66.749 50.094 66.893 ;
     RECT  2.415 66.707 2.505 66.977 ;
     RECT  7.815 66.707 7.905 66.977 ;
     RECT  13.215 66.707 13.305 66.977 ;
     RECT  29.376 66.893 43.254 66.977 ;
     RECT  51.015 66.749 51.105 66.977 ;
     RECT  56.415 66.707 56.505 66.977 ;
     RECT  61.815 66.707 61.905 66.977 ;
     RECT  44.388 66.893 50.094 67.181 ;
     RECT  17.46 66.865 24.498 67.229 ;
     RECT  25.272 66.749 27.846 67.229 ;
     RECT  30.168 66.977 43.254 67.229 ;
     RECT  44.388 67.181 47.286 67.229 ;
     RECT  48.672 67.181 48.978 67.229 ;
     RECT  17.46 67.229 22.266 67.277 ;
     RECT  23.076 67.229 24.39 67.277 ;
     RECT  25.272 67.229 25.65 67.277 ;
     RECT  26.496 67.229 27.846 67.277 ;
     RECT  29.376 66.977 29.394 67.277 ;
     RECT  30.492 67.229 43.254 67.277 ;
     RECT  44.388 67.229 46.17 67.277 ;
     RECT  47.052 67.229 47.07 67.277 ;
     RECT  48.672 67.229 48.69 67.277 ;
     RECT  50.076 67.181 50.094 67.277 ;
     RECT  38.736 67.277 38.754 67.421 ;
     RECT  17.46 67.277 18.234 67.853 ;
     RECT  21.528 67.277 22.266 67.853 ;
     RECT  25.56 67.277 25.578 67.853 ;
     RECT  26.604 67.277 27.27 67.853 ;
     RECT  33.336 67.277 33.354 67.853 ;
     RECT  34.092 67.277 34.614 67.853 ;
     RECT  39.708 67.277 40.194 67.853 ;
     RECT  40.968 67.277 41.418 67.853 ;
     RECT  42.732 67.277 43.254 67.853 ;
     RECT  27.252 67.853 27.27 67.901 ;
     RECT  34.092 67.853 34.11 67.901 ;
     RECT  21.636 67.853 22.266 68.381 ;
     RECT  25.02 68.347 25.326 68.395 ;
     RECT  17.46 67.853 17.586 68.429 ;
     RECT  22.032 68.381 22.266 68.429 ;
     RECT  30.528 67.277 32.526 68.429 ;
     RECT  39.708 67.853 40.158 68.429 ;
     RECT  43.236 67.853 43.254 68.429 ;
     RECT  17.532 68.429 17.586 68.477 ;
     RECT  30.852 68.429 32.526 68.477 ;
     RECT  30.852 68.477 31.374 68.525 ;
     RECT  17.532 68.477 17.55 68.573 ;
     RECT  24.948 68.395 25.326 68.573 ;
     RECT  25.308 68.573 25.326 68.717 ;
     RECT  41.4 67.853 41.418 68.731 ;
     RECT  29.16 68.635 29.178 68.779 ;
     RECT  22.248 68.429 22.266 68.861 ;
     RECT  28.656 68.779 29.178 68.875 ;
     RECT  41.4 68.731 41.742 68.909 ;
     RECT  19.8 67.277 19.818 69.005 ;
     RECT  23.148 68.875 23.706 69.005 ;
     RECT  25.992 68.875 26.01 69.005 ;
     RECT  28.656 68.875 29.286 69.005 ;
     RECT  31.104 68.525 31.374 69.005 ;
     RECT  32.508 68.477 32.526 69.005 ;
     RECT  39.708 68.429 39.726 69.005 ;
     RECT  41.4 68.909 41.418 69.005 ;
     RECT  44.856 68.875 44.874 69.005 ;
     RECT  46.044 68.875 46.062 69.005 ;
    LAYER M4 ;
     RECT  0.06 17.712 0.133 49.128 ;
     RECT  0.133 17.712 1.145 49.176 ;
     RECT  1.145 17.712 2.408 49.08 ;
     RECT  2.408 2.148 2.512 66.972 ;
     RECT  2.512 2.418 2.704 66.702 ;
     RECT  2.704 17.664 4.061 49.08 ;
     RECT  4.061 17.664 5.101 29.928 ;
     RECT  4.061 30.96 5.101 49.08 ;
     RECT  5.101 17.664 5.573 49.08 ;
     RECT  5.573 17.664 5.681 29.928 ;
     RECT  5.681 21.408 5.717 29.928 ;
     RECT  5.573 31.104 6.865 49.08 ;
     RECT  5.681 17.664 7.285 20.424 ;
     RECT  5.717 21.456 7.285 29.928 ;
     RECT  7.285 17.664 7.369 29.928 ;
     RECT  6.865 31.104 7.369 49.272 ;
     RECT  7.369 17.664 7.808 49.272 ;
     RECT  7.808 2.148 7.912 66.972 ;
     RECT  7.912 2.418 8.104 66.702 ;
     RECT  8.104 21.456 8.243 24.408 ;
     RECT  8.104 28.704 8.284 31.224 ;
     RECT  8.284 30.816 8.309 31.224 ;
     RECT  8.104 34.032 8.381 38.76 ;
     RECT  8.104 45.552 8.381 48.792 ;
     RECT  8.243 21.456 8.453 23.064 ;
     RECT  8.104 25.488 8.453 27.096 ;
     RECT  8.381 35.712 8.453 38.76 ;
     RECT  8.104 39.744 8.453 43.944 ;
     RECT  8.104 18.144 8.531 19.992 ;
     RECT  8.531 18.144 8.705 18.168 ;
     RECT  8.453 21.696 8.849 23.064 ;
     RECT  8.849 21.696 8.993 22.488 ;
     RECT  8.243 24.384 9.065 24.408 ;
     RECT  8.453 39.744 9.065 41.976 ;
     RECT  9.065 40.848 9.101 41.976 ;
     RECT  8.381 34.032 9.245 34.056 ;
     RECT  8.453 26.304 9.281 27.096 ;
     RECT  9.065 39.744 9.281 39.864 ;
     RECT  9.281 27.072 9.317 27.096 ;
     RECT  8.309 30.816 9.317 30.84 ;
     RECT  9.281 39.744 9.317 39.768 ;
     RECT  8.453 36.192 9.353 38.76 ;
     RECT  8.104 32.256 9.389 32.904 ;
     RECT  8.453 43.392 9.389 43.944 ;
     RECT  8.284 28.704 9.425 28.968 ;
     RECT  9.425 28.704 9.461 28.728 ;
     RECT  8.993 22.464 9.569 22.488 ;
     RECT  9.389 43.392 9.677 43.416 ;
     RECT  9.101 41.616 9.961 41.976 ;
     RECT  8.531 19.488 13.208 19.512 ;
     RECT  9.389 32.88 13.208 32.904 ;
     RECT  9.353 36.576 13.208 38.76 ;
     RECT  9.961 41.616 13.208 42.744 ;
     RECT  8.381 46.224 13.208 48.792 ;
     RECT  13.208 2.148 13.312 66.972 ;
     RECT  13.312 2.418 13.504 66.702 ;
     RECT  17.449 68.4 17.521 68.424 ;
     RECT  17.521 68.4 17.593 68.568 ;
     RECT  17.66 66.72 17.737 66.744 ;
     RECT  17.593 67.824 17.737 68.568 ;
     RECT  17.737 66.72 18.061 68.568 ;
     RECT  18.061 66.672 18.515 68.568 ;
     RECT  13.504 19.488 18.608 19.512 ;
     RECT  13.504 32.88 18.608 32.904 ;
     RECT  13.504 36.576 18.608 38.76 ;
     RECT  13.504 41.616 18.608 42.744 ;
     RECT  13.504 46.224 18.608 48.792 ;
     RECT  18.515 66.672 18.608 67.272 ;
     RECT  18.515 68.448 18.611 68.568 ;
     RECT  18.611 68.544 18.707 68.568 ;
     RECT  18.608 2.148 18.712 67.272 ;
     RECT  18.712 2.418 18.904 67.272 ;
     RECT  18.904 45.696 19.037 48.792 ;
     RECT  18.904 32.88 19.361 33.048 ;
     RECT  18.904 21.12 19.897 21.144 ;
     RECT  19.897 21.12 19.937 21.48 ;
     RECT  19.789 68.976 20.051 69 ;
     RECT  18.904 66.528 20.533 67.272 ;
     RECT  18.904 63.216 20.657 63.24 ;
     RECT  20.905 50.352 20.917 50.376 ;
     RECT  19.037 46.224 20.963 48.792 ;
     RECT  20.917 50.208 20.972 50.376 ;
     RECT  20.972 50.208 21.059 50.712 ;
     RECT  18.904 64.368 21.059 64.392 ;
     RECT  20.533 65.664 21.395 67.272 ;
     RECT  18.904 19.488 21.517 19.512 ;
     RECT  21.395 67.152 21.517 67.272 ;
     RECT  21.517 67.152 21.625 67.848 ;
     RECT  21.625 67.152 21.637 68.376 ;
     RECT  20.963 46.224 21.661 47.736 ;
     RECT  20.509 23.088 21.881 23.112 ;
     RECT  21.445 63.12 21.949 63.144 ;
     RECT  21.395 65.664 21.985 66.168 ;
     RECT  21.637 67.152 22.355 68.952 ;
     RECT  21.985 64.848 22.489 66.168 ;
     RECT  22.355 67.152 22.489 67.272 ;
     RECT  22.355 68.4 22.739 68.952 ;
     RECT  21.949 63.12 22.849 63.24 ;
     RECT  22.489 64.848 22.849 67.272 ;
     RECT  22.849 63.12 22.889 67.272 ;
     RECT  22.739 68.784 23.122 68.952 ;
     RECT  22.889 63.12 23.317 65.688 ;
     RECT  23.122 68.784 23.555 69 ;
     RECT  23.555 68.88 23.795 69 ;
     RECT  23.795 68.88 23.843 68.952 ;
     RECT  21.661 46.032 23.965 47.736 ;
     RECT  20.963 48.768 23.965 48.792 ;
     RECT  23.029 7.344 24.008 7.368 ;
     RECT  21.517 19.488 24.008 19.848 ;
     RECT  19.937 21.456 24.008 21.48 ;
     RECT  19.361 32.88 24.008 32.904 ;
     RECT  22.789 34.656 24.008 34.68 ;
     RECT  18.904 36.576 24.008 38.76 ;
     RECT  18.904 41.616 24.008 42.744 ;
     RECT  23.965 46.032 24.008 48.792 ;
     RECT  21.059 50.352 24.008 50.376 ;
     RECT  23.317 62.544 24.008 65.688 ;
     RECT  22.889 66.912 24.008 67.272 ;
     RECT  24.008 2.148 24.112 67.272 ;
     RECT  24.112 2.418 24.304 67.272 ;
     RECT  23.843 68.928 24.515 68.952 ;
     RECT  24.304 46.224 24.617 48.792 ;
     RECT  24.304 66.72 24.851 67.272 ;
     RECT  24.893 68.544 24.908 68.712 ;
     RECT  24.908 68.4 25.004 68.712 ;
     RECT  24.304 62.544 25.297 64.2 ;
     RECT  25.297 62.544 25.337 64.392 ;
     RECT  24.304 36.576 25.405 38.76 ;
     RECT  25.337 62.832 25.427 64.392 ;
     RECT  24.304 41.616 25.549 42.744 ;
     RECT  24.851 67.248 25.549 67.272 ;
     RECT  25.004 68.352 25.549 68.712 ;
     RECT  25.549 67.248 25.765 68.712 ;
     RECT  25.765 67.248 25.861 68.952 ;
     RECT  25.549 40.992 25.873 42.744 ;
     RECT  25.405 36.576 25.945 39.24 ;
     RECT  25.873 40.272 25.945 42.744 ;
     RECT  25.861 67.2 25.954 68.952 ;
     RECT  25.954 67.2 25.957 69 ;
     RECT  25.957 67.104 26.017 69 ;
     RECT  25.427 62.832 26.093 63.816 ;
     RECT  26.017 66.864 26.195 69 ;
     RECT  26.195 66.864 26.3 67.848 ;
     RECT  26.093 62.832 26.449 63.72 ;
     RECT  25.945 36.576 26.813 42.744 ;
     RECT  26.813 40.272 26.849 42.744 ;
     RECT  26.3 66.72 26.963 67.848 ;
     RECT  26.963 66.768 27.059 67.848 ;
     RECT  27.059 66.816 27.155 67.848 ;
     RECT  26.449 62.112 27.197 63.72 ;
     RECT  24.304 65.664 27.205 65.688 ;
     RECT  27.155 66.864 27.241 67.848 ;
     RECT  27.205 64.944 27.251 65.688 ;
     RECT  27.197 62.112 27.281 63.816 ;
     RECT  27.281 62.112 27.317 63.288 ;
     RECT  27.241 66.864 27.317 67.896 ;
     RECT  27.317 67.248 27.539 67.896 ;
     RECT  26.849 40.56 27.709 42.744 ;
     RECT  27.539 67.248 28.115 67.272 ;
     RECT  27.317 62.736 28.261 63.288 ;
     RECT  27.251 64.944 28.397 65.592 ;
     RECT  27.589 68.928 28.549 68.952 ;
     RECT  28.549 68.928 28.597 69 ;
     RECT  28.261 62.736 28.645 63.672 ;
     RECT  28.645 62.736 28.741 63.864 ;
     RECT  27.709 40.56 28.897 43.32 ;
     RECT  28.597 68.784 29.125 69 ;
     RECT  29.125 68.736 29.132 69 ;
     RECT  29.132 68.64 29.219 69 ;
     RECT  24.304 7.344 29.408 7.368 ;
     RECT  24.304 19.824 29.408 19.848 ;
     RECT  24.304 21.456 29.408 21.48 ;
     RECT  24.304 32.88 29.408 32.904 ;
     RECT  24.304 34.656 29.408 34.68 ;
     RECT  26.813 36.576 29.408 39.24 ;
     RECT  28.897 40.56 29.408 43.8 ;
     RECT  24.617 46.224 29.408 47.736 ;
     RECT  24.617 48.768 29.408 48.792 ;
     RECT  24.304 50.352 29.408 50.376 ;
     RECT  28.741 62.736 29.408 63.912 ;
     RECT  28.397 64.944 29.408 65.016 ;
     RECT  29.317 67.248 29.408 67.272 ;
     RECT  29.408 2.148 29.512 67.272 ;
     RECT  29.219 68.736 29.555 69 ;
     RECT  29.512 2.418 29.704 67.272 ;
     RECT  29.704 63.648 30.131 67.272 ;
     RECT  29.555 68.784 30.517 69 ;
     RECT  30.131 63.84 30.521 67.272 ;
     RECT  30.521 63.84 30.665 64.632 ;
     RECT  29.704 45.744 30.773 47.736 ;
     RECT  30.521 65.808 30.845 67.272 ;
     RECT  31.201 2.496 31.273 2.52 ;
     RECT  30.517 68.4 31.385 69 ;
     RECT  30.845 66.72 31.475 67.272 ;
     RECT  31.273 2.256 31.525 2.52 ;
     RECT  31.525 2.256 31.597 2.664 ;
     RECT  31.475 66.912 31.705 67.272 ;
     RECT  31.385 68.4 31.705 68.472 ;
     RECT  29.704 36.576 31.741 39.24 ;
     RECT  31.705 0.528 31.885 0.552 ;
     RECT  31.597 2.256 31.957 3.288 ;
     RECT  31.201 4.512 31.957 4.536 ;
     RECT  31.705 66.912 32.051 68.472 ;
     RECT  31.885 0.528 32.065 1.224 ;
     RECT  32.051 68.4 32.147 68.472 ;
     RECT  31.957 2.256 32.173 4.536 ;
     RECT  32.065 0.48 32.209 1.224 ;
     RECT  32.173 2.208 32.209 4.536 ;
     RECT  32.209 0.48 32.245 4.536 ;
     RECT  32.147 68.448 32.339 68.472 ;
     RECT  32.245 0.384 32.389 4.536 ;
     RECT  32.453 68.976 32.537 69 ;
     RECT  30.665 64.32 32.573 64.632 ;
     RECT  32.389 0.384 32.605 4.584 ;
     RECT  31.772 63.216 32.821 63.24 ;
     RECT  32.605 0.096 33.013 4.728 ;
     RECT  32.857 5.76 33.013 5.784 ;
     RECT  29.704 7.344 33.013 7.368 ;
     RECT  32.051 66.912 33.073 67.272 ;
     RECT  33.073 66.72 33.145 67.272 ;
     RECT  31.741 36.24 33.185 39.24 ;
     RECT  33.013 0.096 33.217 5.784 ;
     RECT  33.145 66.672 33.325 67.272 ;
     RECT  32.821 63.216 33.349 64.152 ;
     RECT  33.349 62.832 33.365 64.152 ;
     RECT  33.013 6.96 33.545 7.368 ;
     RECT  33.325 66.672 33.545 67.848 ;
     RECT  33.365 62.832 33.689 62.904 ;
     RECT  33.365 64.128 33.689 64.152 ;
     RECT  33.217 0.048 33.865 5.784 ;
     RECT  33.545 6.96 33.865 6.984 ;
     RECT  33.545 66.72 34.066 67.848 ;
     RECT  34.066 66.72 34.259 67.896 ;
     RECT  33.865 0.048 34.547 6.984 ;
     RECT  34.547 1.68 34.643 6.984 ;
     RECT  33.689 62.88 34.693 62.904 ;
     RECT  34.643 2.148 34.808 6.984 ;
     RECT  29.704 19.824 34.808 19.848 ;
     RECT  29.704 21.456 34.808 21.48 ;
     RECT  29.704 32.88 34.808 32.904 ;
     RECT  29.704 34.656 34.808 34.68 ;
     RECT  33.185 36.576 34.808 39.24 ;
     RECT  29.704 40.56 34.808 43.32 ;
     RECT  30.773 46.224 34.808 47.736 ;
     RECT  29.704 48.768 34.808 48.792 ;
     RECT  29.704 50.352 34.808 50.376 ;
     RECT  34.693 62.88 34.808 63.816 ;
     RECT  34.549 64.896 34.808 64.92 ;
     RECT  34.259 66.72 34.808 67.848 ;
     RECT  34.808 2.148 34.912 67.848 ;
     RECT  34.547 0.048 35.027 0.648 ;
     RECT  34.912 2.352 35.027 67.848 ;
     RECT  35.027 2.352 35.104 67.272 ;
     RECT  35.104 34.704 35.267 34.728 ;
     RECT  35.104 50.16 35.267 50.376 ;
     RECT  35.104 62.688 35.273 64.968 ;
     RECT  35.104 2.352 35.363 7.992 ;
     RECT  35.104 14.832 35.363 14.856 ;
     RECT  35.104 19.44 35.363 19.944 ;
     RECT  35.363 19.536 35.389 19.944 ;
     RECT  35.104 66.72 35.699 67.272 ;
     RECT  35.557 68.928 35.843 68.952 ;
     RECT  35.363 2.352 35.941 7.752 ;
     RECT  35.273 62.688 36.065 64.056 ;
     RECT  35.104 21.12 36.133 21.576 ;
     RECT  36.133 21.072 36.457 21.576 ;
     RECT  35.027 0.048 36.467 0.6 ;
     RECT  35.941 2.256 36.493 7.752 ;
     RECT  36.467 0.048 36.929 0.312 ;
     RECT  35.699 66.768 36.956 67.272 ;
     RECT  36.929 0.144 36.973 0.312 ;
     RECT  36.973 0.288 37.043 0.312 ;
     RECT  36.997 10.848 37.145 10.872 ;
     RECT  36.065 63.264 37.196 64.056 ;
     RECT  36.956 66.72 37.321 67.272 ;
     RECT  37.237 68.832 37.381 68.856 ;
     RECT  36.493 2.256 37.573 8.424 ;
     RECT  37.573 2.256 37.657 8.568 ;
     RECT  37.196 63.216 37.717 64.056 ;
     RECT  37.381 68.832 37.765 68.952 ;
     RECT  37.717 62.64 37.801 64.056 ;
     RECT  36.457 21.024 37.937 21.576 ;
     RECT  37.657 2.256 37.957 8.184 ;
     RECT  37.765 68.784 38.003 68.952 ;
     RECT  37.937 21.072 38.009 21.576 ;
     RECT  38.003 68.88 38.147 68.952 ;
     RECT  38.009 21.216 38.189 21.576 ;
     RECT  37.573 65.52 38.225 65.544 ;
     RECT  37.321 66.672 38.405 67.272 ;
     RECT  37.801 63.072 38.473 64.056 ;
     RECT  38.405 66.72 38.483 67.272 ;
     RECT  38.189 21.456 38.513 21.576 ;
     RECT  38.483 67.056 38.629 67.272 ;
     RECT  35.267 50.16 38.653 50.184 ;
     RECT  38.147 68.928 38.723 68.952 ;
     RECT  38.629 67.056 38.725 67.32 ;
     RECT  38.725 67.056 38.765 67.416 ;
     RECT  38.765 67.152 38.771 67.416 ;
     RECT  35.104 32.88 38.797 32.904 ;
     RECT  38.771 67.2 38.809 67.416 ;
     RECT  38.473 63.072 38.873 64.728 ;
     RECT  37.957 1.776 38.977 8.184 ;
     RECT  38.797 32.88 39.017 32.952 ;
     RECT  38.977 1.632 39.109 8.184 ;
     RECT  35.104 48.768 39.265 48.792 ;
     RECT  38.653 49.776 39.265 50.184 ;
     RECT  39.109 1.152 39.299 8.184 ;
     RECT  39.299 1.632 39.347 8.184 ;
     RECT  38.873 63.072 39.445 64.344 ;
     RECT  39.347 1.728 39.553 8.184 ;
     RECT  39.445 62.64 39.589 64.344 ;
     RECT  39.553 1.728 39.665 8.232 ;
     RECT  39.653 68.976 39.737 69 ;
     RECT  39.589 62.592 39.769 64.344 ;
     RECT  39.769 62.544 39.781 64.344 ;
     RECT  38.809 67.2 39.805 67.272 ;
     RECT  39.925 0.144 40.021 0.168 ;
     RECT  39.017 32.88 40.093 32.904 ;
     RECT  39.805 66.72 40.165 67.272 ;
     RECT  40.129 68.4 40.165 68.424 ;
     RECT  39.665 1.776 40.208 8.232 ;
     RECT  35.389 19.536 40.208 19.56 ;
     RECT  38.513 21.456 40.208 21.48 ;
     RECT  40.093 32.88 40.208 33.048 ;
     RECT  35.104 36.576 40.208 39.24 ;
     RECT  35.104 40.56 40.208 43.32 ;
     RECT  35.104 46.224 40.208 47.736 ;
     RECT  39.265 48.768 40.208 50.184 ;
     RECT  39.781 62.016 40.208 64.344 ;
     RECT  40.165 66.72 40.208 68.424 ;
     RECT  40.021 0.144 40.307 0.216 ;
     RECT  40.208 1.776 40.499 68.424 ;
     RECT  40.499 1.776 40.504 67.848 ;
     RECT  40.307 0.144 40.643 0.168 ;
     RECT  40.504 1.776 40.645 8.232 ;
     RECT  40.645 1.152 40.745 8.232 ;
     RECT  40.745 1.152 40.781 7.992 ;
     RECT  40.781 1.152 40.787 7.944 ;
     RECT  40.741 0.096 40.961 0.12 ;
     RECT  40.504 50.16 40.997 50.712 ;
     RECT  40.504 62.592 41.033 64.248 ;
     RECT  40.504 66.72 41.267 67.848 ;
     RECT  41.029 68.928 41.389 68.952 ;
     RECT  40.787 1.728 41.393 7.944 ;
     RECT  41.389 68.928 41.651 69 ;
     RECT  41.033 62.784 41.681 64.248 ;
     RECT  41.669 68.88 41.708 68.904 ;
     RECT  41.681 64.224 41.749 64.248 ;
     RECT  41.708 68.736 41.753 68.904 ;
     RECT  41.753 68.736 41.795 68.856 ;
     RECT  41.393 1.728 41.825 7.56 ;
     RECT  40.504 31.728 41.965 31.752 ;
     RECT  41.795 68.832 41.987 68.856 ;
     RECT  41.681 62.784 42.013 63.24 ;
     RECT  41.965 31.728 42.037 31.896 ;
     RECT  40.504 33.024 42.181 33.048 ;
     RECT  41.749 64.224 42.181 64.968 ;
     RECT  42.037 31.728 42.217 31.992 ;
     RECT  42.181 33.024 42.217 33.096 ;
     RECT  42.181 64.224 42.293 65.592 ;
     RECT  42.217 31.728 42.329 33.096 ;
     RECT  42.013 62.784 42.421 63.144 ;
     RECT  42.293 64.224 42.467 64.248 ;
     RECT  42.293 65.568 42.467 65.592 ;
     RECT  41.825 1.728 42.469 7.416 ;
     RECT  42.469 1.248 42.541 7.416 ;
     RECT  42.541 1.152 42.625 7.416 ;
     RECT  41.267 66.72 42.721 67.272 ;
     RECT  42.329 31.968 42.761 33.096 ;
     RECT  42.761 32.832 42.829 33.096 ;
     RECT  40.997 50.16 42.829 50.184 ;
     RECT  42.829 50.16 42.869 50.328 ;
     RECT  42.829 32.832 42.905 33.288 ;
     RECT  42.721 66.72 43.045 67.848 ;
     RECT  42.625 1.728 43.081 7.416 ;
     RECT  43.045 66.144 43.187 67.848 ;
     RECT  43.187 66.144 43.193 67.224 ;
     RECT  42.421 62.64 43.225 63.144 ;
     RECT  43.193 66.144 43.379 66.744 ;
     RECT  43.225 68.4 43.475 68.424 ;
     RECT  43.379 66.192 43.517 66.744 ;
     RECT  40.504 19.536 43.573 19.56 ;
     RECT  43.081 1.728 43.669 7.512 ;
     RECT  43.669 1.152 43.765 7.512 ;
     RECT  43.225 62.64 43.765 63.192 ;
     RECT  42.905 33.168 43.805 33.288 ;
     RECT  43.805 33.264 43.841 33.288 ;
     RECT  43.669 0.144 43.859 0.168 ;
     RECT  43.765 62.64 43.868 63.24 ;
     RECT  43.765 1.152 44.057 7.8 ;
     RECT  44.057 7.776 44.237 7.8 ;
     RECT  44.057 1.152 44.293 6.792 ;
     RECT  43.517 66.384 44.293 66.744 ;
     RECT  40.504 36.576 44.453 39.24 ;
     RECT  44.453 37.344 44.597 39.24 ;
     RECT  44.597 37.488 44.633 39.24 ;
     RECT  43.621 68.928 44.818 68.952 ;
     RECT  44.818 68.88 44.929 69 ;
     RECT  44.293 0.816 45.169 6.792 ;
     RECT  44.929 68.88 45.301 68.952 ;
     RECT  44.633 37.584 45.565 39.24 ;
     RECT  45.169 0.816 45.608 6.888 ;
     RECT  43.573 19.536 45.608 19.8 ;
     RECT  40.504 21.456 45.608 21.48 ;
     RECT  45.565 37.584 45.608 39.288 ;
     RECT  40.504 40.56 45.608 43.32 ;
     RECT  40.504 46.224 45.608 47.736 ;
     RECT  40.504 48.768 45.608 48.792 ;
     RECT  42.869 50.304 45.608 50.328 ;
     RECT  43.868 62.64 45.608 63.864 ;
     RECT  44.293 66.384 45.608 67.272 ;
     RECT  45.301 68.832 45.637 68.952 ;
     RECT  45.608 0.816 45.904 67.272 ;
     RECT  45.637 68.544 45.989 68.952 ;
     RECT  45.989 68.544 46.067 69 ;
     RECT  46.067 68.88 46.073 69 ;
     RECT  46.073 68.88 46.115 68.904 ;
     RECT  45.904 0.816 46.433 5.832 ;
     RECT  45.904 37.872 46.685 43.32 ;
     RECT  45.904 46.224 46.973 48.792 ;
     RECT  46.433 0.816 47.333 5.16 ;
     RECT  45.904 66.768 47.365 67.272 ;
     RECT  45.904 62.64 47.585 64.968 ;
     RECT  46.685 39.216 47.621 43.32 ;
     RECT  46.973 46.224 47.693 47.736 ;
     RECT  47.621 40.368 47.729 43.32 ;
     RECT  47.333 0.816 47.801 4.248 ;
     RECT  47.801 0.816 47.873 3.624 ;
     RECT  47.873 2.208 47.945 3.624 ;
     RECT  45.904 50.16 47.945 50.184 ;
     RECT  47.945 2.352 47.981 3.48 ;
     RECT  47.585 62.64 48.037 64.44 ;
     RECT  48.037 62.16 48.089 64.44 ;
     RECT  48.089 63.504 48.097 64.44 ;
     RECT  48.097 63.504 48.233 64.392 ;
     RECT  48.089 62.16 48.275 62.184 ;
     RECT  47.981 2.352 48.377 3.144 ;
     RECT  47.873 0.816 48.449 0.84 ;
     RECT  47.365 66.144 48.517 67.272 ;
     RECT  45.904 19.536 48.557 19.8 ;
     RECT  48.377 2.352 48.773 3 ;
     RECT  48.773 2.976 48.809 3 ;
     RECT  47.693 46.272 48.841 47.736 ;
     RECT  46.973 48.768 48.841 48.792 ;
     RECT  48.233 63.504 49.097 63.672 ;
     RECT  48.841 46.272 49.273 48.792 ;
     RECT  49.273 46.272 49.417 48.984 ;
     RECT  48.229 50.112 49.417 50.136 ;
     RECT  49.417 46.272 49.457 50.136 ;
     RECT  48.517 65.808 49.777 67.272 ;
     RECT  49.777 65.568 49.781 67.272 ;
     RECT  49.457 46.272 49.961 49.848 ;
     RECT  49.781 65.568 49.997 66.168 ;
     RECT  49.781 67.248 50.105 67.272 ;
     RECT  49.997 65.568 50.173 65.592 ;
     RECT  46.981 14.64 51.008 14.664 ;
     RECT  48.557 19.776 51.008 19.8 ;
     RECT  45.904 21.456 51.008 21.48 ;
     RECT  46.685 37.872 51.008 37.896 ;
     RECT  47.621 39.216 51.008 39.24 ;
     RECT  47.729 40.56 51.008 43.32 ;
     RECT  49.961 46.272 51.008 46.872 ;
     RECT  49.961 47.904 51.008 49.848 ;
     RECT  49.097 63.504 51.008 63.528 ;
     RECT  50.173 64.608 51.008 65.592 ;
     RECT  51.008 2.148 51.112 66.972 ;
     RECT  51.112 2.418 51.304 66.702 ;
     RECT  51.304 48.768 51.617 48.792 ;
     RECT  51.304 63.504 52.741 63.528 ;
     RECT  51.304 64.608 52.741 64.632 ;
     RECT  52.741 63.504 52.765 64.632 ;
     RECT  52.765 62.736 52.787 64.632 ;
     RECT  52.787 62.736 52.828 63.72 ;
     RECT  52.828 62.736 52.849 62.76 ;
     RECT  51.304 14.64 54.457 14.664 ;
     RECT  51.304 21.456 54.469 21.48 ;
     RECT  51.304 19.776 54.515 19.8 ;
     RECT  54.457 14.64 54.541 14.808 ;
     RECT  54.541 14.64 56.005 14.664 ;
     RECT  56.005 14.496 56.408 14.664 ;
     RECT  54.469 21.408 56.408 21.48 ;
     RECT  51.304 37.872 56.408 37.896 ;
     RECT  51.304 39.216 56.408 39.24 ;
     RECT  51.304 40.56 56.408 43.32 ;
     RECT  51.304 46.272 56.408 46.872 ;
     RECT  51.304 49.824 56.408 49.848 ;
     RECT  52.789 51.36 56.408 51.384 ;
     RECT  56.408 2.148 56.512 66.972 ;
     RECT  56.512 2.418 56.704 66.702 ;
     RECT  56.704 37.872 58.705 37.896 ;
     RECT  56.704 46.272 58.705 46.872 ;
     RECT  56.704 51.36 58.705 51.384 ;
     RECT  58.705 37.728 58.741 37.896 ;
     RECT  56.704 39.216 58.741 39.24 ;
     RECT  56.704 40.56 58.741 43.32 ;
     RECT  58.705 51.216 58.741 51.384 ;
     RECT  58.741 37.728 58.853 39.24 ;
     RECT  58.853 37.728 58.889 37.896 ;
     RECT  58.705 46.272 58.889 47.736 ;
     RECT  58.741 51.12 58.889 51.384 ;
     RECT  59.749 35.04 59.785 35.064 ;
     RECT  56.704 49.824 59.785 49.848 ;
     RECT  59.785 35.04 59.821 35.16 ;
     RECT  56.704 21.408 59.852 21.48 ;
     RECT  58.741 40.56 59.857 43.656 ;
     RECT  58.889 37.872 59.861 37.896 ;
     RECT  56.704 14.496 59.939 14.52 ;
     RECT  59.852 21.408 59.965 21.96 ;
     RECT  59.713 30.144 59.965 30.168 ;
     RECT  59.713 36.864 60.577 36.888 ;
     RECT  59.281 32.304 60.613 32.328 ;
     RECT  60.577 36.672 60.649 36.888 ;
     RECT  60.721 27.168 60.829 27.192 ;
     RECT  60.037 28.272 60.829 28.296 ;
     RECT  58.853 39.216 60.865 39.24 ;
     RECT  59.857 40.56 60.865 43.944 ;
     RECT  60.613 31.68 60.937 32.328 ;
     RECT  60.649 36.672 60.937 36.936 ;
     RECT  60.865 38.4 60.937 39.24 ;
     RECT  60.865 40.56 60.937 44.232 ;
     RECT  59.785 48.912 60.937 49.848 ;
     RECT  59.965 21.408 60.973 22.776 ;
     RECT  58.889 51.36 60.973 51.384 ;
     RECT  60.937 31.44 61.009 32.328 ;
     RECT  60.973 21.36 61.045 22.776 ;
     RECT  58.889 46.272 61.045 46.872 ;
     RECT  60.937 48.624 61.045 49.848 ;
     RECT  61.009 31.44 61.052 32.856 ;
     RECT  61.009 33.936 61.052 33.96 ;
     RECT  61.045 20.976 61.381 22.776 ;
     RECT  61.381 20.16 61.441 22.776 ;
     RECT  61.441 20.16 61.477 23.352 ;
     RECT  60.109 24.48 61.477 24.504 ;
     RECT  59.821 34.992 61.477 35.16 ;
     RECT  60.937 36.672 61.573 39.24 ;
     RECT  61.477 20.16 61.808 24.504 ;
     RECT  60.829 26.64 61.808 28.296 ;
     RECT  59.965 29.664 61.808 30.168 ;
     RECT  61.052 31.44 61.808 33.96 ;
     RECT  61.477 34.992 61.808 35.496 ;
     RECT  61.573 36.672 61.808 39.288 ;
     RECT  60.937 40.416 61.808 44.472 ;
     RECT  61.045 46.272 61.808 47.352 ;
     RECT  61.045 48.48 61.808 49.848 ;
     RECT  60.973 51.12 61.808 51.384 ;
     RECT  61.808 2.148 61.912 66.972 ;
     RECT  61.912 2.418 62.104 66.702 ;
     RECT  62.104 48.96 62.165 51.384 ;
     RECT  62.104 20.976 62.201 21.72 ;
     RECT  62.104 30.672 62.741 47.352 ;
     RECT  62.741 31.68 63.133 47.352 ;
     RECT  62.165 49.584 63.241 51.384 ;
     RECT  63.241 49.536 63.349 51.384 ;
     RECT  62.104 22.848 63.445 23.736 ;
     RECT  62.201 21.072 63.457 21.72 ;
     RECT  63.445 22.848 63.457 24.072 ;
     RECT  62.104 25.824 63.491 29.592 ;
     RECT  63.133 31.68 63.497 47.88 ;
     RECT  63.349 49.344 63.605 51.384 ;
     RECT  63.497 39.216 63.677 47.88 ;
     RECT  63.457 21.072 63.731 24.072 ;
     RECT  63.731 21.072 63.893 23.352 ;
     RECT  63.677 40.704 63.893 47.88 ;
     RECT  63.497 31.68 63.929 37.608 ;
     RECT  63.893 21.36 63.965 23.352 ;
     RECT  63.491 26.88 64.073 29.592 ;
     RECT  62.741 30.672 64.105 30.696 ;
     RECT  63.605 49.536 64.109 51.384 ;
     RECT  64.073 26.88 64.217 28.968 ;
     RECT  64.105 30.144 64.285 30.696 ;
     RECT  63.929 31.68 64.285 34.248 ;
     RECT  63.929 35.472 64.325 37.608 ;
     RECT  63.491 25.824 64.361 25.896 ;
     RECT  63.893 40.704 64.433 46.296 ;
     RECT  64.109 50.016 64.469 51.384 ;
     RECT  64.285 30.144 64.541 34.248 ;
     RECT  64.469 50.016 64.541 51.096 ;
     RECT  64.325 35.472 64.649 35.496 ;
     RECT  63.677 39.216 64.753 39.336 ;
     RECT  64.433 40.704 64.753 44.232 ;
     RECT  64.217 27.984 64.757 28.968 ;
     RECT  64.433 45.264 64.757 46.296 ;
     RECT  64.217 26.88 64.793 26.904 ;
     RECT  64.541 50.016 64.829 50.664 ;
     RECT  64.325 36.864 64.865 37.608 ;
     RECT  63.673 19.92 64.901 19.944 ;
     RECT  63.965 23.328 64.901 23.352 ;
     RECT  64.757 27.984 64.901 28.008 ;
     RECT  64.541 30.144 64.901 30.456 ;
     RECT  64.541 31.728 64.901 34.248 ;
     RECT  64.757 45.984 64.901 46.296 ;
     RECT  64.829 50.16 64.901 50.664 ;
     RECT  63.965 21.36 64.973 22.296 ;
     RECT  64.865 36.864 64.973 36.888 ;
     RECT  64.753 39.216 64.973 44.232 ;
     RECT  64.901 32.88 65.009 34.248 ;
     RECT  64.973 42.528 65.009 44.232 ;
     RECT  63.893 47.28 65.009 47.88 ;
     RECT  64.973 21.36 65.081 21.48 ;
     RECT  64.973 39.888 65.081 41.4 ;
     RECT  65.081 41.376 65.117 41.4 ;
     RECT  65.081 39.888 65.189 39.912 ;
     RECT  65.081 21.456 65.225 21.48 ;
     RECT  65.009 47.28 65.257 47.688 ;
     RECT  65.009 33.744 65.261 34.248 ;
     RECT  65.257 46.752 65.549 47.688 ;
     RECT  65.077 48.816 65.837 48.84 ;
     RECT  64.901 50.16 66.161 50.28 ;
     RECT  65.261 33.744 66.193 34.104 ;
     RECT  65.009 42.528 66.193 42.888 ;
     RECT  64.901 31.728 66.481 31.752 ;
     RECT  66.193 42.048 66.553 42.888 ;
     RECT  65.797 28.176 66.697 28.2 ;
     RECT  66.481 31.728 66.697 31.896 ;
     RECT  66.445 36.912 66.697 36.936 ;
     RECT  66.661 40.08 66.697 40.104 ;
     RECT  64.361 25.824 66.7 25.848 ;
     RECT  66.553 41.952 67.201 42.888 ;
     RECT  65.009 44.208 67.201 44.232 ;
     RECT  66.697 20.016 67.237 20.04 ;
     RECT  66.697 23.856 67.237 24.744 ;
     RECT  66.7 25.824 67.237 25.896 ;
     RECT  66.697 27.12 67.237 28.2 ;
     RECT  66.697 29.232 67.237 29.256 ;
     RECT  64.901 30.432 67.237 30.456 ;
     RECT  66.193 33.648 67.237 34.104 ;
     RECT  66.697 35.76 67.237 37.416 ;
     RECT  67.201 41.952 67.237 44.232 ;
     RECT  65.549 47.232 67.237 47.688 ;
     RECT  66.697 49.008 67.237 49.704 ;
     RECT  66.697 51.12 67.237 51.144 ;
     RECT  67.237 20.016 67.273 20.808 ;
     RECT  67.237 23.856 67.273 25.896 ;
     RECT  67.237 27.12 67.273 29.256 ;
     RECT  67.237 30.384 67.273 30.456 ;
     RECT  66.697 31.728 67.273 32.52 ;
     RECT  67.237 33.648 67.273 37.704 ;
     RECT  66.697 39.216 67.273 40.584 ;
     RECT  67.237 41.616 67.273 44.232 ;
     RECT  67.237 46.512 67.273 47.688 ;
     RECT  67.237 48.816 67.273 51.144 ;
     RECT  67.273 20.016 67.309 21.48 ;
     RECT  67.273 22.608 67.309 29.256 ;
     RECT  67.273 30.288 67.741 37.704 ;
     RECT  67.273 39.216 67.741 45.096 ;
     RECT  67.273 46.128 67.741 51.144 ;
     RECT  67.309 20.016 67.777 29.256 ;
     RECT  67.741 30.288 67.777 37.992 ;
     RECT  67.741 39.216 67.777 51.144 ;
     RECT  67.777 19.92 67.849 37.992 ;
     RECT  67.777 39.12 67.849 51.144 ;
     RECT  67.849 19.92 68.353 51.144 ;
     RECT  68.353 19.92 69.001 51.24 ;
     RECT  69.001 19.92 69.084 51.336 ;
    LAYER M5 ;
     RECT  32.208 0.016 45.192 0.611 ;
     RECT  32.304 0.611 45.192 1.813 ;
     RECT  32.304 1.813 45.384 2.137 ;
     RECT  2.4 2.137 2.52 2.151 ;
     RECT  7.8 2.137 7.92 2.151 ;
     RECT  13.2 2.137 13.32 2.151 ;
     RECT  18.6 2.137 18.72 2.151 ;
     RECT  24 2.137 24.12 2.151 ;
     RECT  29.4 2.137 29.52 2.151 ;
     RECT  32.304 2.137 45.72 2.151 ;
     RECT  51 2.137 51.12 2.151 ;
     RECT  56.4 2.137 56.52 2.151 ;
     RECT  61.8 2.137 61.92 2.151 ;
     RECT  32.304 2.151 45.912 2.197 ;
     RECT  32.304 2.197 46.776 2.243 ;
     RECT  32.4 2.243 46.776 2.245 ;
     RECT  32.4 2.245 47.016 2.771 ;
     RECT  32.4 2.771 45.912 2.867 ;
     RECT  46.896 2.771 47.016 2.867 ;
     RECT  32.4 2.867 44.616 4.211 ;
     RECT  32.4 4.211 44.232 4.595 ;
     RECT  45.6 2.867 45.912 5.269 ;
     RECT  33.024 4.595 44.232 5.603 ;
     RECT  34.32 5.603 44.232 5.747 ;
     RECT  34.416 5.747 44.232 5.795 ;
     RECT  34.8 5.795 44.232 6.277 ;
     RECT  45.312 5.269 45.912 6.277 ;
     RECT  34.8 6.277 45.912 6.611 ;
     RECT  34.8 6.611 43.944 6.707 ;
     RECT  43.44 6.707 43.944 6.755 ;
     RECT  43.536 6.755 43.944 6.803 ;
     RECT  34.8 6.707 42.36 6.899 ;
     RECT  43.584 6.803 43.944 6.899 ;
     RECT  45.312 6.611 45.912 6.899 ;
     RECT  34.8 6.899 42.12 6.947 ;
     RECT  33.024 5.603 33.048 6.995 ;
     RECT  39.792 6.947 41.736 7.283 ;
     RECT  24 2.151 24.312 7.333 ;
     RECT  34.8 6.947 38.52 7.475 ;
     RECT  39.792 7.283 41.304 7.475 ;
     RECT  39.792 7.475 40.968 7.571 ;
     RECT  39.792 7.571 40.632 7.715 ;
     RECT  39.888 7.715 40.632 7.811 ;
     RECT  43.584 6.899 43.8 7.811 ;
     RECT  34.8 7.475 35.352 8.003 ;
     RECT  39.888 7.811 40.512 8.003 ;
     RECT  36.912 7.475 38.52 8.195 ;
     RECT  39.936 8.003 40.512 8.195 ;
     RECT  36.912 8.195 37.608 8.435 ;
     RECT  37.008 8.435 37.608 8.579 ;
     RECT  37.008 8.579 37.032 10.883 ;
     RECT  46.992 2.867 47.016 14.675 ;
     RECT  34.8 8.003 35.208 14.821 ;
     RECT  7.8 2.151 8.112 18.181 ;
     RECT  2.4 2.151 2.712 18.229 ;
     RECT  2.304 18.229 2.712 18.419 ;
     RECT  7.8 18.181 8.52 19.333 ;
     RECT  23.04 7.333 24.312 19.523 ;
     RECT  6.864 19.333 8.52 19.619 ;
     RECT  43.584 7.811 43.608 19.811 ;
     RECT  7.296 19.619 8.52 20.003 ;
     RECT  61.8 2.151 62.112 20.149 ;
     RECT  7.296 20.003 8.112 20.579 ;
     RECT  61.392 20.149 62.112 21.011 ;
     RECT  34.8 14.821 35.352 21.395 ;
     RECT  54.48 14.773 54.504 21.443 ;
     RECT  59.904 14.485 59.928 21.971 ;
     RECT  7.344 20.579 8.112 22.741 ;
     RECT  7.344 22.741 8.232 23.459 ;
     RECT  7.8 23.459 8.232 23.987 ;
     RECT  63.696 21.397 63.72 24.037 ;
     RECT  63.456 24.037 63.72 24.083 ;
     RECT  7.8 23.987 8.112 25.093 ;
     RECT  5.088 23.413 5.112 25.765 ;
     RECT  4.752 25.765 5.112 25.811 ;
     RECT  6.912 25.093 8.112 26.243 ;
     RECT  4.752 25.811 4.776 26.677 ;
     RECT  4.512 26.677 4.776 27.059 ;
     RECT  2.4 18.419 2.712 27.157 ;
     RECT  61.8 21.011 62.112 27.685 ;
     RECT  2.304 27.157 2.712 27.971 ;
     RECT  61.8 27.685 62.232 28.163 ;
     RECT  7.8 26.243 8.112 28.453 ;
     RECT  63.456 24.083 63.48 28.547 ;
     RECT  7.68 28.453 8.112 29.075 ;
     RECT  4.752 27.059 4.776 29.219 ;
     RECT  2.4 27.971 2.712 29.557 ;
     RECT  7.8 29.075 8.112 29.893 ;
     RECT  2.4 29.557 3.432 30.851 ;
     RECT  7.8 29.893 8.232 30.899 ;
     RECT  68.928 30.757 68.952 30.947 ;
     RECT  4.704 29.605 4.728 31.667 ;
     RECT  63.408 28.837 63.432 31.669 ;
     RECT  63.264 31.669 63.432 31.715 ;
     RECT  2.4 30.851 2.856 31.765 ;
     RECT  2.304 31.765 2.856 31.861 ;
     RECT  2.304 31.861 2.904 31.955 ;
     RECT  5.28 32.725 5.304 32.915 ;
     RECT  2.4 31.955 2.904 33.011 ;
     RECT  61.8 28.163 62.112 33.013 ;
     RECT  63.264 31.715 63.288 33.107 ;
     RECT  61.104 33.013 62.112 33.971 ;
     RECT  4.704 33.541 4.728 34.259 ;
     RECT  4.464 34.789 4.488 35.363 ;
     RECT  7.8 30.899 8.112 36.613 ;
     RECT  6.864 36.613 8.112 36.851 ;
     RECT  45.6 6.899 45.912 38.485 ;
     RECT  45.12 38.485 45.912 38.771 ;
     RECT  61.8 33.971 62.112 39.253 ;
     RECT  61.584 39.253 62.112 40.451 ;
     RECT  4.512 36.469 4.536 41.125 ;
     RECT  26.784 41.221 26.808 41.747 ;
     RECT  0.144 41.749 0.168 41.939 ;
     RECT  4.512 41.125 4.68 41.939 ;
     RECT  7.8 36.851 8.112 41.989 ;
     RECT  61.8 40.451 62.112 43.237 ;
     RECT  4.512 41.939 4.536 43.427 ;
     RECT  61.8 43.237 62.232 43.955 ;
     RECT  61.8 43.955 62.112 44.101 ;
     RECT  5.424 44.053 5.448 44.243 ;
     RECT  63.216 36.901 63.24 44.483 ;
     RECT  7.392 41.989 8.112 44.821 ;
     RECT  2.4 33.011 2.712 45.781 ;
     RECT  2.304 45.781 2.712 45.971 ;
     RECT  6.816 44.821 8.112 45.971 ;
     RECT  0.144 46.501 0.168 46.691 ;
     RECT  0.144 47.653 0.168 47.843 ;
     RECT  7.68 45.971 8.112 47.845 ;
     RECT  6.816 47.845 8.112 48.467 ;
     RECT  61.056 44.101 62.112 48.661 ;
     RECT  1.152 48.757 1.176 49.043 ;
     RECT  0.144 48.997 0.168 49.187 ;
     RECT  61.008 48.661 62.112 49.859 ;
     RECT  20.928 48.133 20.952 50.197 ;
     RECT  20.928 50.197 21.048 50.243 ;
     RECT  34.8 21.395 35.256 50.387 ;
     RECT  40.2 8.195 40.512 62.005 ;
     RECT  48.24 50.101 48.264 62.149 ;
     RECT  48.048 62.149 48.264 62.195 ;
     RECT  39.792 62.005 40.512 62.581 ;
     RECT  39.6 62.581 40.872 62.629 ;
     RECT  52.8 51.349 52.824 62.771 ;
     RECT  27.792 62.725 27.816 62.821 ;
     RECT  29.4 2.151 29.712 62.821 ;
     RECT  42.432 62.629 42.456 62.821 ;
     RECT  25.584 62.821 26.568 62.869 ;
     RECT  33.36 62.821 33.384 62.869 ;
     RECT  39.504 62.629 40.872 63.013 ;
     RECT  37.728 62.629 37.752 63.061 ;
     RECT  39.504 63.013 41.352 63.061 ;
     RECT  45.6 38.771 45.912 63.061 ;
     RECT  21.024 50.243 21.048 63.109 ;
     RECT  22.8 34.645 22.824 63.109 ;
     RECT  25.584 62.869 26.76 63.109 ;
     RECT  27.792 62.821 29.712 63.109 ;
     RECT  37.728 63.061 41.352 63.109 ;
     RECT  42.432 62.821 43.752 63.109 ;
     RECT  21.024 63.109 22.824 63.157 ;
     RECT  24 19.523 24.312 63.157 ;
     RECT  48.048 62.195 48.072 63.157 ;
     RECT  21.024 63.157 24.312 63.205 ;
     RECT  25.344 63.109 29.712 63.205 ;
     RECT  34.8 50.387 35.112 63.205 ;
     RECT  37.728 63.109 44.232 63.205 ;
     RECT  45.312 63.061 45.912 63.205 ;
     RECT  47.568 63.157 48.072 63.205 ;
     RECT  34.8 63.205 35.832 63.253 ;
     RECT  37.248 63.205 46.008 63.253 ;
     RECT  47.472 63.205 48.072 63.253 ;
     RECT  21.024 63.205 29.712 63.637 ;
     RECT  34.8 63.253 48.072 63.637 ;
     RECT  34.8 63.637 48.36 63.781 ;
     RECT  21.024 63.637 30.12 63.829 ;
     RECT  21.024 63.829 30.6 64.357 ;
     RECT  52.752 63.685 52.776 64.643 ;
     RECT  20.544 64.357 30.6 65.699 ;
     RECT  34.704 63.781 48.36 65.797 ;
     RECT  18.6 2.151 18.912 66.517 ;
     RECT  18.6 66.517 19.752 66.661 ;
     RECT  18.288 66.661 19.752 66.709 ;
     RECT  21.456 65.699 30.6 66.709 ;
     RECT  31.824 63.205 31.848 66.709 ;
     RECT  33.36 62.869 33.48 66.709 ;
     RECT  34.704 65.797 48.552 66.709 ;
     RECT  17.712 66.709 31.848 66.901 ;
     RECT  33.168 66.709 49.128 66.901 ;
     RECT  2.4 45.971 2.712 66.969 ;
     RECT  7.8 48.467 8.112 66.969 ;
     RECT  13.2 2.151 13.512 66.969 ;
     RECT  51 2.151 51.312 66.969 ;
     RECT  56.4 2.151 56.712 66.969 ;
     RECT  61.8 49.859 62.112 66.969 ;
     RECT  2.4 66.969 2.52 66.983 ;
     RECT  7.8 66.969 7.92 66.983 ;
     RECT  13.2 66.969 13.32 66.983 ;
     RECT  51 66.969 51.12 66.983 ;
     RECT  56.4 66.969 56.52 66.983 ;
     RECT  61.8 66.969 61.92 66.983 ;
     RECT  17.712 66.901 49.128 69.072 ;
  END
END ot_hbm_host_cfg_leaf_sw
END LIBRARY
